VERSION 5.8 ;
BUSBITCHARS "[]" ;
DIVIDERCHAR "/" ;
UNITS
    DATABASE MICRONS 1000 ;
END UNITS

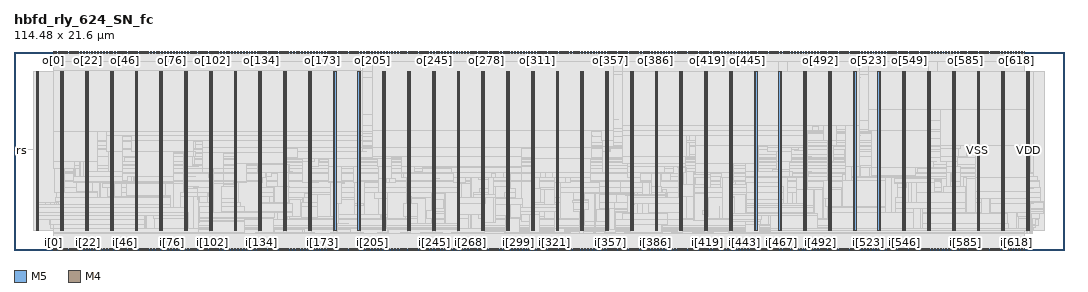
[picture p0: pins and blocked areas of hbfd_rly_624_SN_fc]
MACRO hbfd_rly_624_SN_fc
  FOREIGN hbfd_rly_624_SN_fc 0 0 ;
  CLASS BLOCK ;
  SIZE 114.48 BY 21.6 ;
  PIN clk_in
    DIRECTION INPUT ;
    USE SIGNAL ;
    PORT
      LAYER M5 ;
        RECT  57.216 0 57.24 0.192 ;
    END
  END clk_in
  PIN clk_out
    DIRECTION OUTPUT ;
    USE SIGNAL ;
    PORT
      LAYER M5 ;
        RECT  57.216 21.408 57.24 21.6 ;
    END
  END clk_out
  PIN i[0]
    DIRECTION INPUT ;
    USE SIGNAL ;
    PORT
      LAYER M5 ;
        RECT  4.32 0 4.344 0.192 ;
    END
  END i[0]
  PIN i[100]
    DIRECTION INPUT ;
    USE SIGNAL ;
    PORT
      LAYER M5 ;
        RECT  21.264 0 21.288 0.192 ;
    END
  END i[100]
  PIN i[101]
    DIRECTION INPUT ;
    USE SIGNAL ;
    PORT
      LAYER M5 ;
        RECT  21.456 0 21.48 0.192 ;
    END
  END i[101]
  PIN i[102]
    DIRECTION INPUT ;
    USE SIGNAL ;
    PORT
      LAYER M5 ;
        RECT  21.6 0 21.624 0.192 ;
    END
  END i[102]
  PIN i[103]
    DIRECTION INPUT ;
    USE SIGNAL ;
    PORT
      LAYER M5 ;
        RECT  21.792 0 21.816 0.192 ;
    END
  END i[103]
  PIN i[104]
    DIRECTION INPUT ;
    USE SIGNAL ;
    PORT
      LAYER M5 ;
        RECT  21.936 0 21.96 0.192 ;
    END
  END i[104]
  PIN i[105]
    DIRECTION INPUT ;
    USE SIGNAL ;
    PORT
      LAYER M5 ;
        RECT  22.128 0 22.152 0.192 ;
    END
  END i[105]
  PIN i[106]
    DIRECTION INPUT ;
    USE SIGNAL ;
    PORT
      LAYER M5 ;
        RECT  22.272 0 22.296 0.192 ;
    END
  END i[106]
  PIN i[107]
    DIRECTION INPUT ;
    USE SIGNAL ;
    PORT
      LAYER M5 ;
        RECT  22.464 0 22.488 0.192 ;
    END
  END i[107]
  PIN i[108]
    DIRECTION INPUT ;
    USE SIGNAL ;
    PORT
      LAYER M5 ;
        RECT  22.608 0 22.632 0.192 ;
    END
  END i[108]
  PIN i[109]
    DIRECTION INPUT ;
    USE SIGNAL ;
    PORT
      LAYER M5 ;
        RECT  22.8 0 22.824 0.192 ;
    END
  END i[109]
  PIN i[10]
    DIRECTION INPUT ;
    USE SIGNAL ;
    PORT
      LAYER M5 ;
        RECT  6 0 6.024 0.192 ;
    END
  END i[10]
  PIN i[110]
    DIRECTION INPUT ;
    USE SIGNAL ;
    PORT
      LAYER M5 ;
        RECT  22.944 0 22.968 0.192 ;
    END
  END i[110]
  PIN i[111]
    DIRECTION INPUT ;
    USE SIGNAL ;
    PORT
      LAYER M5 ;
        RECT  23.136 0 23.16 0.192 ;
    END
  END i[111]
  PIN i[112]
    DIRECTION INPUT ;
    USE SIGNAL ;
    PORT
      LAYER M5 ;
        RECT  23.328 0 23.352 0.192 ;
    END
  END i[112]
  PIN i[113]
    DIRECTION INPUT ;
    USE SIGNAL ;
    PORT
      LAYER M5 ;
        RECT  23.472 0 23.496 0.192 ;
    END
  END i[113]
  PIN i[114]
    DIRECTION INPUT ;
    USE SIGNAL ;
    PORT
      LAYER M5 ;
        RECT  23.664 0 23.688 0.192 ;
    END
  END i[114]
  PIN i[115]
    DIRECTION INPUT ;
    USE SIGNAL ;
    PORT
      LAYER M5 ;
        RECT  23.808 0 23.832 0.192 ;
    END
  END i[115]
  PIN i[116]
    DIRECTION INPUT ;
    USE SIGNAL ;
    PORT
      LAYER M5 ;
        RECT  24 0 24.024 0.192 ;
    END
  END i[116]
  PIN i[117]
    DIRECTION INPUT ;
    USE SIGNAL ;
    PORT
      LAYER M5 ;
        RECT  24.144 0 24.168 0.192 ;
    END
  END i[117]
  PIN i[118]
    DIRECTION INPUT ;
    USE SIGNAL ;
    PORT
      LAYER M5 ;
        RECT  24.336 0 24.36 0.192 ;
    END
  END i[118]
  PIN i[119]
    DIRECTION INPUT ;
    USE SIGNAL ;
    PORT
      LAYER M5 ;
        RECT  24.48 0 24.504 0.192 ;
    END
  END i[119]
  PIN i[11]
    DIRECTION INPUT ;
    USE SIGNAL ;
    PORT
      LAYER M5 ;
        RECT  6.192 0 6.216 0.192 ;
    END
  END i[11]
  PIN i[120]
    DIRECTION INPUT ;
    USE SIGNAL ;
    PORT
      LAYER M5 ;
        RECT  24.672 0 24.696 0.192 ;
    END
  END i[120]
  PIN i[121]
    DIRECTION INPUT ;
    USE SIGNAL ;
    PORT
      LAYER M5 ;
        RECT  24.816 0 24.84 0.192 ;
    END
  END i[121]
  PIN i[122]
    DIRECTION INPUT ;
    USE SIGNAL ;
    PORT
      LAYER M5 ;
        RECT  25.008 0 25.032 0.192 ;
    END
  END i[122]
  PIN i[123]
    DIRECTION INPUT ;
    USE SIGNAL ;
    PORT
      LAYER M5 ;
        RECT  25.152 0 25.176 0.192 ;
    END
  END i[123]
  PIN i[124]
    DIRECTION INPUT ;
    USE SIGNAL ;
    PORT
      LAYER M5 ;
        RECT  25.344 0 25.368 0.192 ;
    END
  END i[124]
  PIN i[125]
    DIRECTION INPUT ;
    USE SIGNAL ;
    PORT
      LAYER M5 ;
        RECT  25.488 0 25.512 0.192 ;
    END
  END i[125]
  PIN i[126]
    DIRECTION INPUT ;
    USE SIGNAL ;
    PORT
      LAYER M5 ;
        RECT  25.68 0 25.704 0.192 ;
    END
  END i[126]
  PIN i[127]
    DIRECTION INPUT ;
    USE SIGNAL ;
    PORT
      LAYER M5 ;
        RECT  25.872 0 25.896 0.192 ;
    END
  END i[127]
  PIN i[128]
    DIRECTION INPUT ;
    USE SIGNAL ;
    PORT
      LAYER M5 ;
        RECT  26.016 0 26.04 0.192 ;
    END
  END i[128]
  PIN i[129]
    DIRECTION INPUT ;
    USE SIGNAL ;
    PORT
      LAYER M5 ;
        RECT  26.208 0 26.232 0.192 ;
    END
  END i[129]
  PIN i[12]
    DIRECTION INPUT ;
    USE SIGNAL ;
    PORT
      LAYER M5 ;
        RECT  6.336 0 6.36 0.192 ;
    END
  END i[12]
  PIN i[130]
    DIRECTION INPUT ;
    USE SIGNAL ;
    PORT
      LAYER M5 ;
        RECT  26.352 0 26.376 0.192 ;
    END
  END i[130]
  PIN i[131]
    DIRECTION INPUT ;
    USE SIGNAL ;
    PORT
      LAYER M5 ;
        RECT  26.544 0 26.568 0.192 ;
    END
  END i[131]
  PIN i[132]
    DIRECTION INPUT ;
    USE SIGNAL ;
    PORT
      LAYER M5 ;
        RECT  26.688 0 26.712 0.192 ;
    END
  END i[132]
  PIN i[133]
    DIRECTION INPUT ;
    USE SIGNAL ;
    PORT
      LAYER M5 ;
        RECT  26.88 0 26.904 0.192 ;
    END
  END i[133]
  PIN i[134]
    DIRECTION INPUT ;
    USE SIGNAL ;
    PORT
      LAYER M5 ;
        RECT  27.024 0 27.048 0.192 ;
    END
  END i[134]
  PIN i[135]
    DIRECTION INPUT ;
    USE SIGNAL ;
    PORT
      LAYER M5 ;
        RECT  27.216 0 27.24 0.192 ;
    END
  END i[135]
  PIN i[136]
    DIRECTION INPUT ;
    USE SIGNAL ;
    PORT
      LAYER M5 ;
        RECT  27.36 0 27.384 0.192 ;
    END
  END i[136]
  PIN i[137]
    DIRECTION INPUT ;
    USE SIGNAL ;
    PORT
      LAYER M5 ;
        RECT  27.552 0 27.576 0.192 ;
    END
  END i[137]
  PIN i[138]
    DIRECTION INPUT ;
    USE SIGNAL ;
    PORT
      LAYER M5 ;
        RECT  27.696 0 27.72 0.192 ;
    END
  END i[138]
  PIN i[139]
    DIRECTION INPUT ;
    USE SIGNAL ;
    PORT
      LAYER M5 ;
        RECT  27.888 0 27.912 0.192 ;
    END
  END i[139]
  PIN i[13]
    DIRECTION INPUT ;
    USE SIGNAL ;
    PORT
      LAYER M5 ;
        RECT  6.528 0 6.552 0.192 ;
    END
  END i[13]
  PIN i[140]
    DIRECTION INPUT ;
    USE SIGNAL ;
    PORT
      LAYER M5 ;
        RECT  28.032 0 28.056 0.192 ;
    END
  END i[140]
  PIN i[141]
    DIRECTION INPUT ;
    USE SIGNAL ;
    PORT
      LAYER M5 ;
        RECT  28.224 0 28.248 0.192 ;
    END
  END i[141]
  PIN i[142]
    DIRECTION INPUT ;
    USE SIGNAL ;
    PORT
      LAYER M5 ;
        RECT  28.416 0 28.44 0.192 ;
    END
  END i[142]
  PIN i[143]
    DIRECTION INPUT ;
    USE SIGNAL ;
    PORT
      LAYER M5 ;
        RECT  28.56 0 28.584 0.192 ;
    END
  END i[143]
  PIN i[144]
    DIRECTION INPUT ;
    USE SIGNAL ;
    PORT
      LAYER M5 ;
        RECT  28.752 0 28.776 0.192 ;
    END
  END i[144]
  PIN i[145]
    DIRECTION INPUT ;
    USE SIGNAL ;
    PORT
      LAYER M5 ;
        RECT  28.896 0 28.92 0.192 ;
    END
  END i[145]
  PIN i[146]
    DIRECTION INPUT ;
    USE SIGNAL ;
    PORT
      LAYER M5 ;
        RECT  29.088 0 29.112 0.192 ;
    END
  END i[146]
  PIN i[147]
    DIRECTION INPUT ;
    USE SIGNAL ;
    PORT
      LAYER M5 ;
        RECT  29.232 0 29.256 0.192 ;
    END
  END i[147]
  PIN i[148]
    DIRECTION INPUT ;
    USE SIGNAL ;
    PORT
      LAYER M5 ;
        RECT  29.424 0 29.448 0.192 ;
    END
  END i[148]
  PIN i[149]
    DIRECTION INPUT ;
    USE SIGNAL ;
    PORT
      LAYER M5 ;
        RECT  29.568 0 29.592 0.192 ;
    END
  END i[149]
  PIN i[14]
    DIRECTION INPUT ;
    USE SIGNAL ;
    PORT
      LAYER M5 ;
        RECT  6.672 0 6.696 0.192 ;
    END
  END i[14]
  PIN i[150]
    DIRECTION INPUT ;
    USE SIGNAL ;
    PORT
      LAYER M5 ;
        RECT  29.76 0 29.784 0.192 ;
    END
  END i[150]
  PIN i[151]
    DIRECTION INPUT ;
    USE SIGNAL ;
    PORT
      LAYER M5 ;
        RECT  29.904 0 29.928 0.192 ;
    END
  END i[151]
  PIN i[152]
    DIRECTION INPUT ;
    USE SIGNAL ;
    PORT
      LAYER M5 ;
        RECT  30.096 0 30.12 0.192 ;
    END
  END i[152]
  PIN i[153]
    DIRECTION INPUT ;
    USE SIGNAL ;
    PORT
      LAYER M5 ;
        RECT  30.24 0 30.264 0.192 ;
    END
  END i[153]
  PIN i[154]
    DIRECTION INPUT ;
    USE SIGNAL ;
    PORT
      LAYER M5 ;
        RECT  30.432 0 30.456 0.192 ;
    END
  END i[154]
  PIN i[155]
    DIRECTION INPUT ;
    USE SIGNAL ;
    PORT
      LAYER M5 ;
        RECT  30.576 0 30.6 0.192 ;
    END
  END i[155]
  PIN i[156]
    DIRECTION INPUT ;
    USE SIGNAL ;
    PORT
      LAYER M5 ;
        RECT  30.768 0 30.792 0.192 ;
    END
  END i[156]
  PIN i[157]
    DIRECTION INPUT ;
    USE SIGNAL ;
    PORT
      LAYER M5 ;
        RECT  30.96 0 30.984 0.192 ;
    END
  END i[157]
  PIN i[158]
    DIRECTION INPUT ;
    USE SIGNAL ;
    PORT
      LAYER M5 ;
        RECT  31.104 0 31.128 0.192 ;
    END
  END i[158]
  PIN i[159]
    DIRECTION INPUT ;
    USE SIGNAL ;
    PORT
      LAYER M5 ;
        RECT  31.296 0 31.32 0.192 ;
    END
  END i[159]
  PIN i[15]
    DIRECTION INPUT ;
    USE SIGNAL ;
    PORT
      LAYER M5 ;
        RECT  6.864 0 6.888 0.192 ;
    END
  END i[15]
  PIN i[160]
    DIRECTION INPUT ;
    USE SIGNAL ;
    PORT
      LAYER M5 ;
        RECT  31.44 0 31.464 0.192 ;
    END
  END i[160]
  PIN i[161]
    DIRECTION INPUT ;
    USE SIGNAL ;
    PORT
      LAYER M5 ;
        RECT  31.632 0 31.656 0.192 ;
    END
  END i[161]
  PIN i[162]
    DIRECTION INPUT ;
    USE SIGNAL ;
    PORT
      LAYER M5 ;
        RECT  31.776 0 31.8 0.192 ;
    END
  END i[162]
  PIN i[163]
    DIRECTION INPUT ;
    USE SIGNAL ;
    PORT
      LAYER M5 ;
        RECT  31.968 0 31.992 0.192 ;
    END
  END i[163]
  PIN i[164]
    DIRECTION INPUT ;
    USE SIGNAL ;
    PORT
      LAYER M5 ;
        RECT  32.112 0 32.136 0.192 ;
    END
  END i[164]
  PIN i[165]
    DIRECTION INPUT ;
    USE SIGNAL ;
    PORT
      LAYER M5 ;
        RECT  32.304 0 32.328 0.192 ;
    END
  END i[165]
  PIN i[166]
    DIRECTION INPUT ;
    USE SIGNAL ;
    PORT
      LAYER M5 ;
        RECT  32.448 0 32.472 0.192 ;
    END
  END i[166]
  PIN i[167]
    DIRECTION INPUT ;
    USE SIGNAL ;
    PORT
      LAYER M5 ;
        RECT  32.64 0 32.664 0.192 ;
    END
  END i[167]
  PIN i[168]
    DIRECTION INPUT ;
    USE SIGNAL ;
    PORT
      LAYER M5 ;
        RECT  32.784 0 32.808 0.192 ;
    END
  END i[168]
  PIN i[169]
    DIRECTION INPUT ;
    USE SIGNAL ;
    PORT
      LAYER M5 ;
        RECT  32.976 0 33 0.192 ;
    END
  END i[169]
  PIN i[16]
    DIRECTION INPUT ;
    USE SIGNAL ;
    PORT
      LAYER M5 ;
        RECT  7.008 0 7.032 0.192 ;
    END
  END i[16]
  PIN i[170]
    DIRECTION INPUT ;
    USE SIGNAL ;
    PORT
      LAYER M5 ;
        RECT  33.12 0 33.144 0.192 ;
    END
  END i[170]
  PIN i[171]
    DIRECTION INPUT ;
    USE SIGNAL ;
    PORT
      LAYER M5 ;
        RECT  33.312 0 33.336 0.192 ;
    END
  END i[171]
  PIN i[172]
    DIRECTION INPUT ;
    USE SIGNAL ;
    PORT
      LAYER M5 ;
        RECT  33.504 0 33.528 0.192 ;
    END
  END i[172]
  PIN i[173]
    DIRECTION INPUT ;
    USE SIGNAL ;
    PORT
      LAYER M5 ;
        RECT  33.648 0 33.672 0.192 ;
    END
  END i[173]
  PIN i[174]
    DIRECTION INPUT ;
    USE SIGNAL ;
    PORT
      LAYER M5 ;
        RECT  33.84 0 33.864 0.192 ;
    END
  END i[174]
  PIN i[175]
    DIRECTION INPUT ;
    USE SIGNAL ;
    PORT
      LAYER M5 ;
        RECT  33.984 0 34.008 0.192 ;
    END
  END i[175]
  PIN i[176]
    DIRECTION INPUT ;
    USE SIGNAL ;
    PORT
      LAYER M5 ;
        RECT  34.176 0 34.2 0.192 ;
    END
  END i[176]
  PIN i[177]
    DIRECTION INPUT ;
    USE SIGNAL ;
    PORT
      LAYER M5 ;
        RECT  34.32 0 34.344 0.192 ;
    END
  END i[177]
  PIN i[178]
    DIRECTION INPUT ;
    USE SIGNAL ;
    PORT
      LAYER M5 ;
        RECT  34.512 0 34.536 0.192 ;
    END
  END i[178]
  PIN i[179]
    DIRECTION INPUT ;
    USE SIGNAL ;
    PORT
      LAYER M5 ;
        RECT  34.656 0 34.68 0.192 ;
    END
  END i[179]
  PIN i[17]
    DIRECTION INPUT ;
    USE SIGNAL ;
    PORT
      LAYER M5 ;
        RECT  7.2 0 7.224 0.192 ;
    END
  END i[17]
  PIN i[180]
    DIRECTION INPUT ;
    USE SIGNAL ;
    PORT
      LAYER M5 ;
        RECT  34.848 0 34.872 0.192 ;
    END
  END i[180]
  PIN i[181]
    DIRECTION INPUT ;
    USE SIGNAL ;
    PORT
      LAYER M5 ;
        RECT  34.992 0 35.016 0.192 ;
    END
  END i[181]
  PIN i[182]
    DIRECTION INPUT ;
    USE SIGNAL ;
    PORT
      LAYER M5 ;
        RECT  35.184 0 35.208 0.192 ;
    END
  END i[182]
  PIN i[183]
    DIRECTION INPUT ;
    USE SIGNAL ;
    PORT
      LAYER M5 ;
        RECT  35.328 0 35.352 0.192 ;
    END
  END i[183]
  PIN i[184]
    DIRECTION INPUT ;
    USE SIGNAL ;
    PORT
      LAYER M5 ;
        RECT  35.52 0 35.544 0.192 ;
    END
  END i[184]
  PIN i[185]
    DIRECTION INPUT ;
    USE SIGNAL ;
    PORT
      LAYER M5 ;
        RECT  35.664 0 35.688 0.192 ;
    END
  END i[185]
  PIN i[186]
    DIRECTION INPUT ;
    USE SIGNAL ;
    PORT
      LAYER M5 ;
        RECT  35.856 0 35.88 0.192 ;
    END
  END i[186]
  PIN i[187]
    DIRECTION INPUT ;
    USE SIGNAL ;
    PORT
      LAYER M5 ;
        RECT  36.048 0 36.072 0.192 ;
    END
  END i[187]
  PIN i[188]
    DIRECTION INPUT ;
    USE SIGNAL ;
    PORT
      LAYER M5 ;
        RECT  36.192 0 36.216 0.192 ;
    END
  END i[188]
  PIN i[189]
    DIRECTION INPUT ;
    USE SIGNAL ;
    PORT
      LAYER M5 ;
        RECT  36.384 0 36.408 0.192 ;
    END
  END i[189]
  PIN i[18]
    DIRECTION INPUT ;
    USE SIGNAL ;
    PORT
      LAYER M5 ;
        RECT  7.344 0 7.368 0.192 ;
    END
  END i[18]
  PIN i[190]
    DIRECTION INPUT ;
    USE SIGNAL ;
    PORT
      LAYER M5 ;
        RECT  36.528 0 36.552 0.192 ;
    END
  END i[190]
  PIN i[191]
    DIRECTION INPUT ;
    USE SIGNAL ;
    PORT
      LAYER M5 ;
        RECT  36.72 0 36.744 0.192 ;
    END
  END i[191]
  PIN i[192]
    DIRECTION INPUT ;
    USE SIGNAL ;
    PORT
      LAYER M5 ;
        RECT  36.864 0 36.888 0.192 ;
    END
  END i[192]
  PIN i[193]
    DIRECTION INPUT ;
    USE SIGNAL ;
    PORT
      LAYER M5 ;
        RECT  37.056 0 37.08 0.192 ;
    END
  END i[193]
  PIN i[194]
    DIRECTION INPUT ;
    USE SIGNAL ;
    PORT
      LAYER M5 ;
        RECT  37.2 0 37.224 0.192 ;
    END
  END i[194]
  PIN i[195]
    DIRECTION INPUT ;
    USE SIGNAL ;
    PORT
      LAYER M5 ;
        RECT  37.392 0 37.416 0.192 ;
    END
  END i[195]
  PIN i[196]
    DIRECTION INPUT ;
    USE SIGNAL ;
    PORT
      LAYER M5 ;
        RECT  37.536 0 37.56 0.192 ;
    END
  END i[196]
  PIN i[197]
    DIRECTION INPUT ;
    USE SIGNAL ;
    PORT
      LAYER M5 ;
        RECT  37.728 0 37.752 0.192 ;
    END
  END i[197]
  PIN i[198]
    DIRECTION INPUT ;
    USE SIGNAL ;
    PORT
      LAYER M5 ;
        RECT  37.872 0 37.896 0.192 ;
    END
  END i[198]
  PIN i[199]
    DIRECTION INPUT ;
    USE SIGNAL ;
    PORT
      LAYER M5 ;
        RECT  38.064 0 38.088 0.192 ;
    END
  END i[199]
  PIN i[19]
    DIRECTION INPUT ;
    USE SIGNAL ;
    PORT
      LAYER M5 ;
        RECT  7.536 0 7.56 0.192 ;
    END
  END i[19]
  PIN i[1]
    DIRECTION INPUT ;
    USE SIGNAL ;
    PORT
      LAYER M5 ;
        RECT  4.464 0 4.488 0.192 ;
    END
  END i[1]
  PIN i[200]
    DIRECTION INPUT ;
    USE SIGNAL ;
    PORT
      LAYER M5 ;
        RECT  38.208 0 38.232 0.192 ;
    END
  END i[200]
  PIN i[201]
    DIRECTION INPUT ;
    USE SIGNAL ;
    PORT
      LAYER M5 ;
        RECT  38.4 0 38.424 0.192 ;
    END
  END i[201]
  PIN i[202]
    DIRECTION INPUT ;
    USE SIGNAL ;
    PORT
      LAYER M5 ;
        RECT  38.592 0 38.616 0.192 ;
    END
  END i[202]
  PIN i[203]
    DIRECTION INPUT ;
    USE SIGNAL ;
    PORT
      LAYER M5 ;
        RECT  38.736 0 38.76 0.192 ;
    END
  END i[203]
  PIN i[204]
    DIRECTION INPUT ;
    USE SIGNAL ;
    PORT
      LAYER M5 ;
        RECT  38.928 0 38.952 0.192 ;
    END
  END i[204]
  PIN i[205]
    DIRECTION INPUT ;
    USE SIGNAL ;
    PORT
      LAYER M5 ;
        RECT  39.072 0 39.096 0.192 ;
    END
  END i[205]
  PIN i[206]
    DIRECTION INPUT ;
    USE SIGNAL ;
    PORT
      LAYER M5 ;
        RECT  39.264 0 39.288 0.192 ;
    END
  END i[206]
  PIN i[207]
    DIRECTION INPUT ;
    USE SIGNAL ;
    PORT
      LAYER M5 ;
        RECT  39.408 0 39.432 0.192 ;
    END
  END i[207]
  PIN i[208]
    DIRECTION INPUT ;
    USE SIGNAL ;
    PORT
      LAYER M5 ;
        RECT  39.6 0 39.624 0.192 ;
    END
  END i[208]
  PIN i[209]
    DIRECTION INPUT ;
    USE SIGNAL ;
    PORT
      LAYER M5 ;
        RECT  39.744 0 39.768 0.192 ;
    END
  END i[209]
  PIN i[20]
    DIRECTION INPUT ;
    USE SIGNAL ;
    PORT
      LAYER M5 ;
        RECT  7.68 0 7.704 0.192 ;
    END
  END i[20]
  PIN i[210]
    DIRECTION INPUT ;
    USE SIGNAL ;
    PORT
      LAYER M5 ;
        RECT  39.936 0 39.96 0.192 ;
    END
  END i[210]
  PIN i[211]
    DIRECTION INPUT ;
    USE SIGNAL ;
    PORT
      LAYER M5 ;
        RECT  40.08 0 40.104 0.192 ;
    END
  END i[211]
  PIN i[212]
    DIRECTION INPUT ;
    USE SIGNAL ;
    PORT
      LAYER M5 ;
        RECT  40.272 0 40.296 0.192 ;
    END
  END i[212]
  PIN i[213]
    DIRECTION INPUT ;
    USE SIGNAL ;
    PORT
      LAYER M5 ;
        RECT  40.416 0 40.44 0.192 ;
    END
  END i[213]
  PIN i[214]
    DIRECTION INPUT ;
    USE SIGNAL ;
    PORT
      LAYER M5 ;
        RECT  40.608 0 40.632 0.192 ;
    END
  END i[214]
  PIN i[215]
    DIRECTION INPUT ;
    USE SIGNAL ;
    PORT
      LAYER M5 ;
        RECT  40.752 0 40.776 0.192 ;
    END
  END i[215]
  PIN i[216]
    DIRECTION INPUT ;
    USE SIGNAL ;
    PORT
      LAYER M5 ;
        RECT  40.944 0 40.968 0.192 ;
    END
  END i[216]
  PIN i[217]
    DIRECTION INPUT ;
    USE SIGNAL ;
    PORT
      LAYER M5 ;
        RECT  41.136 0 41.16 0.192 ;
    END
  END i[217]
  PIN i[218]
    DIRECTION INPUT ;
    USE SIGNAL ;
    PORT
      LAYER M5 ;
        RECT  41.28 0 41.304 0.192 ;
    END
  END i[218]
  PIN i[219]
    DIRECTION INPUT ;
    USE SIGNAL ;
    PORT
      LAYER M5 ;
        RECT  41.472 0 41.496 0.192 ;
    END
  END i[219]
  PIN i[21]
    DIRECTION INPUT ;
    USE SIGNAL ;
    PORT
      LAYER M5 ;
        RECT  7.872 0 7.896 0.192 ;
    END
  END i[21]
  PIN i[220]
    DIRECTION INPUT ;
    USE SIGNAL ;
    PORT
      LAYER M5 ;
        RECT  41.616 0 41.64 0.192 ;
    END
  END i[220]
  PIN i[221]
    DIRECTION INPUT ;
    USE SIGNAL ;
    PORT
      LAYER M5 ;
        RECT  41.808 0 41.832 0.192 ;
    END
  END i[221]
  PIN i[222]
    DIRECTION INPUT ;
    USE SIGNAL ;
    PORT
      LAYER M5 ;
        RECT  41.952 0 41.976 0.192 ;
    END
  END i[222]
  PIN i[223]
    DIRECTION INPUT ;
    USE SIGNAL ;
    PORT
      LAYER M5 ;
        RECT  42.144 0 42.168 0.192 ;
    END
  END i[223]
  PIN i[224]
    DIRECTION INPUT ;
    USE SIGNAL ;
    PORT
      LAYER M5 ;
        RECT  42.288 0 42.312 0.192 ;
    END
  END i[224]
  PIN i[225]
    DIRECTION INPUT ;
    USE SIGNAL ;
    PORT
      LAYER M5 ;
        RECT  42.48 0 42.504 0.192 ;
    END
  END i[225]
  PIN i[226]
    DIRECTION INPUT ;
    USE SIGNAL ;
    PORT
      LAYER M5 ;
        RECT  42.624 0 42.648 0.192 ;
    END
  END i[226]
  PIN i[227]
    DIRECTION INPUT ;
    USE SIGNAL ;
    PORT
      LAYER M5 ;
        RECT  42.816 0 42.84 0.192 ;
    END
  END i[227]
  PIN i[228]
    DIRECTION INPUT ;
    USE SIGNAL ;
    PORT
      LAYER M5 ;
        RECT  42.96 0 42.984 0.192 ;
    END
  END i[228]
  PIN i[229]
    DIRECTION INPUT ;
    USE SIGNAL ;
    PORT
      LAYER M5 ;
        RECT  43.152 0 43.176 0.192 ;
    END
  END i[229]
  PIN i[22]
    DIRECTION INPUT ;
    USE SIGNAL ;
    PORT
      LAYER M5 ;
        RECT  8.016 0 8.04 0.192 ;
    END
  END i[22]
  PIN i[230]
    DIRECTION INPUT ;
    USE SIGNAL ;
    PORT
      LAYER M5 ;
        RECT  43.296 0 43.32 0.192 ;
    END
  END i[230]
  PIN i[231]
    DIRECTION INPUT ;
    USE SIGNAL ;
    PORT
      LAYER M5 ;
        RECT  43.488 0 43.512 0.192 ;
    END
  END i[231]
  PIN i[232]
    DIRECTION INPUT ;
    USE SIGNAL ;
    PORT
      LAYER M5 ;
        RECT  43.68 0 43.704 0.192 ;
    END
  END i[232]
  PIN i[233]
    DIRECTION INPUT ;
    USE SIGNAL ;
    PORT
      LAYER M5 ;
        RECT  43.824 0 43.848 0.192 ;
    END
  END i[233]
  PIN i[234]
    DIRECTION INPUT ;
    USE SIGNAL ;
    PORT
      LAYER M5 ;
        RECT  44.016 0 44.04 0.192 ;
    END
  END i[234]
  PIN i[235]
    DIRECTION INPUT ;
    USE SIGNAL ;
    PORT
      LAYER M5 ;
        RECT  44.16 0 44.184 0.192 ;
    END
  END i[235]
  PIN i[236]
    DIRECTION INPUT ;
    USE SIGNAL ;
    PORT
      LAYER M5 ;
        RECT  44.352 0 44.376 0.192 ;
    END
  END i[236]
  PIN i[237]
    DIRECTION INPUT ;
    USE SIGNAL ;
    PORT
      LAYER M5 ;
        RECT  44.496 0 44.52 0.192 ;
    END
  END i[237]
  PIN i[238]
    DIRECTION INPUT ;
    USE SIGNAL ;
    PORT
      LAYER M5 ;
        RECT  44.688 0 44.712 0.192 ;
    END
  END i[238]
  PIN i[239]
    DIRECTION INPUT ;
    USE SIGNAL ;
    PORT
      LAYER M5 ;
        RECT  44.832 0 44.856 0.192 ;
    END
  END i[239]
  PIN i[23]
    DIRECTION INPUT ;
    USE SIGNAL ;
    PORT
      LAYER M5 ;
        RECT  8.208 0 8.232 0.192 ;
    END
  END i[23]
  PIN i[240]
    DIRECTION INPUT ;
    USE SIGNAL ;
    PORT
      LAYER M5 ;
        RECT  45.024 0 45.048 0.192 ;
    END
  END i[240]
  PIN i[241]
    DIRECTION INPUT ;
    USE SIGNAL ;
    PORT
      LAYER M5 ;
        RECT  45.168 0 45.192 0.192 ;
    END
  END i[241]
  PIN i[242]
    DIRECTION INPUT ;
    USE SIGNAL ;
    PORT
      LAYER M5 ;
        RECT  45.36 0 45.384 0.192 ;
    END
  END i[242]
  PIN i[243]
    DIRECTION INPUT ;
    USE SIGNAL ;
    PORT
      LAYER M5 ;
        RECT  45.504 0 45.528 0.192 ;
    END
  END i[243]
  PIN i[244]
    DIRECTION INPUT ;
    USE SIGNAL ;
    PORT
      LAYER M5 ;
        RECT  45.696 0 45.72 0.192 ;
    END
  END i[244]
  PIN i[245]
    DIRECTION INPUT ;
    USE SIGNAL ;
    PORT
      LAYER M5 ;
        RECT  45.84 0 45.864 0.192 ;
    END
  END i[245]
  PIN i[246]
    DIRECTION INPUT ;
    USE SIGNAL ;
    PORT
      LAYER M5 ;
        RECT  46.032 0 46.056 0.192 ;
    END
  END i[246]
  PIN i[247]
    DIRECTION INPUT ;
    USE SIGNAL ;
    PORT
      LAYER M5 ;
        RECT  46.224 0 46.248 0.192 ;
    END
  END i[247]
  PIN i[248]
    DIRECTION INPUT ;
    USE SIGNAL ;
    PORT
      LAYER M5 ;
        RECT  46.368 0 46.392 0.192 ;
    END
  END i[248]
  PIN i[249]
    DIRECTION INPUT ;
    USE SIGNAL ;
    PORT
      LAYER M5 ;
        RECT  46.56 0 46.584 0.192 ;
    END
  END i[249]
  PIN i[24]
    DIRECTION INPUT ;
    USE SIGNAL ;
    PORT
      LAYER M5 ;
        RECT  8.4 0 8.424 0.192 ;
    END
  END i[24]
  PIN i[250]
    DIRECTION INPUT ;
    USE SIGNAL ;
    PORT
      LAYER M5 ;
        RECT  46.704 0 46.728 0.192 ;
    END
  END i[250]
  PIN i[251]
    DIRECTION INPUT ;
    USE SIGNAL ;
    PORT
      LAYER M5 ;
        RECT  46.896 0 46.92 0.192 ;
    END
  END i[251]
  PIN i[252]
    DIRECTION INPUT ;
    USE SIGNAL ;
    PORT
      LAYER M5 ;
        RECT  47.04 0 47.064 0.192 ;
    END
  END i[252]
  PIN i[253]
    DIRECTION INPUT ;
    USE SIGNAL ;
    PORT
      LAYER M5 ;
        RECT  47.232 0 47.256 0.192 ;
    END
  END i[253]
  PIN i[254]
    DIRECTION INPUT ;
    USE SIGNAL ;
    PORT
      LAYER M5 ;
        RECT  47.376 0 47.4 0.192 ;
    END
  END i[254]
  PIN i[255]
    DIRECTION INPUT ;
    USE SIGNAL ;
    PORT
      LAYER M5 ;
        RECT  47.568 0 47.592 0.192 ;
    END
  END i[255]
  PIN i[256]
    DIRECTION INPUT ;
    USE SIGNAL ;
    PORT
      LAYER M5 ;
        RECT  47.712 0 47.736 0.192 ;
    END
  END i[256]
  PIN i[257]
    DIRECTION INPUT ;
    USE SIGNAL ;
    PORT
      LAYER M5 ;
        RECT  47.904 0 47.928 0.192 ;
    END
  END i[257]
  PIN i[258]
    DIRECTION INPUT ;
    USE SIGNAL ;
    PORT
      LAYER M5 ;
        RECT  48.048 0 48.072 0.192 ;
    END
  END i[258]
  PIN i[259]
    DIRECTION INPUT ;
    USE SIGNAL ;
    PORT
      LAYER M5 ;
        RECT  48.24 0 48.264 0.192 ;
    END
  END i[259]
  PIN i[25]
    DIRECTION INPUT ;
    USE SIGNAL ;
    PORT
      LAYER M5 ;
        RECT  8.544 0 8.568 0.192 ;
    END
  END i[25]
  PIN i[260]
    DIRECTION INPUT ;
    USE SIGNAL ;
    PORT
      LAYER M5 ;
        RECT  48.384 0 48.408 0.192 ;
    END
  END i[260]
  PIN i[261]
    DIRECTION INPUT ;
    USE SIGNAL ;
    PORT
      LAYER M5 ;
        RECT  48.576 0 48.6 0.192 ;
    END
  END i[261]
  PIN i[262]
    DIRECTION INPUT ;
    USE SIGNAL ;
    PORT
      LAYER M5 ;
        RECT  48.768 0 48.792 0.192 ;
    END
  END i[262]
  PIN i[263]
    DIRECTION INPUT ;
    USE SIGNAL ;
    PORT
      LAYER M5 ;
        RECT  48.912 0 48.936 0.192 ;
    END
  END i[263]
  PIN i[264]
    DIRECTION INPUT ;
    USE SIGNAL ;
    PORT
      LAYER M5 ;
        RECT  49.104 0 49.128 0.192 ;
    END
  END i[264]
  PIN i[265]
    DIRECTION INPUT ;
    USE SIGNAL ;
    PORT
      LAYER M5 ;
        RECT  49.248 0 49.272 0.192 ;
    END
  END i[265]
  PIN i[266]
    DIRECTION INPUT ;
    USE SIGNAL ;
    PORT
      LAYER M5 ;
        RECT  49.44 0 49.464 0.192 ;
    END
  END i[266]
  PIN i[267]
    DIRECTION INPUT ;
    USE SIGNAL ;
    PORT
      LAYER M5 ;
        RECT  49.584 0 49.608 0.192 ;
    END
  END i[267]
  PIN i[268]
    DIRECTION INPUT ;
    USE SIGNAL ;
    PORT
      LAYER M5 ;
        RECT  49.776 0 49.8 0.192 ;
    END
  END i[268]
  PIN i[269]
    DIRECTION INPUT ;
    USE SIGNAL ;
    PORT
      LAYER M5 ;
        RECT  49.92 0 49.944 0.192 ;
    END
  END i[269]
  PIN i[26]
    DIRECTION INPUT ;
    USE SIGNAL ;
    PORT
      LAYER M5 ;
        RECT  8.736 0 8.76 0.192 ;
    END
  END i[26]
  PIN i[270]
    DIRECTION INPUT ;
    USE SIGNAL ;
    PORT
      LAYER M5 ;
        RECT  50.112 0 50.136 0.192 ;
    END
  END i[270]
  PIN i[271]
    DIRECTION INPUT ;
    USE SIGNAL ;
    PORT
      LAYER M5 ;
        RECT  50.256 0 50.28 0.192 ;
    END
  END i[271]
  PIN i[272]
    DIRECTION INPUT ;
    USE SIGNAL ;
    PORT
      LAYER M5 ;
        RECT  50.448 0 50.472 0.192 ;
    END
  END i[272]
  PIN i[273]
    DIRECTION INPUT ;
    USE SIGNAL ;
    PORT
      LAYER M5 ;
        RECT  50.592 0 50.616 0.192 ;
    END
  END i[273]
  PIN i[274]
    DIRECTION INPUT ;
    USE SIGNAL ;
    PORT
      LAYER M5 ;
        RECT  50.784 0 50.808 0.192 ;
    END
  END i[274]
  PIN i[275]
    DIRECTION INPUT ;
    USE SIGNAL ;
    PORT
      LAYER M5 ;
        RECT  50.976 0 51 0.192 ;
    END
  END i[275]
  PIN i[276]
    DIRECTION INPUT ;
    USE SIGNAL ;
    PORT
      LAYER M5 ;
        RECT  51.12 0 51.144 0.192 ;
    END
  END i[276]
  PIN i[277]
    DIRECTION INPUT ;
    USE SIGNAL ;
    PORT
      LAYER M5 ;
        RECT  51.312 0 51.336 0.192 ;
    END
  END i[277]
  PIN i[278]
    DIRECTION INPUT ;
    USE SIGNAL ;
    PORT
      LAYER M5 ;
        RECT  51.456 0 51.48 0.192 ;
    END
  END i[278]
  PIN i[279]
    DIRECTION INPUT ;
    USE SIGNAL ;
    PORT
      LAYER M5 ;
        RECT  51.648 0 51.672 0.192 ;
    END
  END i[279]
  PIN i[27]
    DIRECTION INPUT ;
    USE SIGNAL ;
    PORT
      LAYER M5 ;
        RECT  8.88 0 8.904 0.192 ;
    END
  END i[27]
  PIN i[280]
    DIRECTION INPUT ;
    USE SIGNAL ;
    PORT
      LAYER M5 ;
        RECT  51.792 0 51.816 0.192 ;
    END
  END i[280]
  PIN i[281]
    DIRECTION INPUT ;
    USE SIGNAL ;
    PORT
      LAYER M5 ;
        RECT  51.984 0 52.008 0.192 ;
    END
  END i[281]
  PIN i[282]
    DIRECTION INPUT ;
    USE SIGNAL ;
    PORT
      LAYER M5 ;
        RECT  52.128 0 52.152 0.192 ;
    END
  END i[282]
  PIN i[283]
    DIRECTION INPUT ;
    USE SIGNAL ;
    PORT
      LAYER M5 ;
        RECT  52.32 0 52.344 0.192 ;
    END
  END i[283]
  PIN i[284]
    DIRECTION INPUT ;
    USE SIGNAL ;
    PORT
      LAYER M5 ;
        RECT  52.464 0 52.488 0.192 ;
    END
  END i[284]
  PIN i[285]
    DIRECTION INPUT ;
    USE SIGNAL ;
    PORT
      LAYER M5 ;
        RECT  52.656 0 52.68 0.192 ;
    END
  END i[285]
  PIN i[286]
    DIRECTION INPUT ;
    USE SIGNAL ;
    PORT
      LAYER M5 ;
        RECT  52.8 0 52.824 0.192 ;
    END
  END i[286]
  PIN i[287]
    DIRECTION INPUT ;
    USE SIGNAL ;
    PORT
      LAYER M5 ;
        RECT  52.992 0 53.016 0.192 ;
    END
  END i[287]
  PIN i[288]
    DIRECTION INPUT ;
    USE SIGNAL ;
    PORT
      LAYER M5 ;
        RECT  53.136 0 53.16 0.192 ;
    END
  END i[288]
  PIN i[289]
    DIRECTION INPUT ;
    USE SIGNAL ;
    PORT
      LAYER M5 ;
        RECT  53.328 0 53.352 0.192 ;
    END
  END i[289]
  PIN i[28]
    DIRECTION INPUT ;
    USE SIGNAL ;
    PORT
      LAYER M5 ;
        RECT  9.072 0 9.096 0.192 ;
    END
  END i[28]
  PIN i[290]
    DIRECTION INPUT ;
    USE SIGNAL ;
    PORT
      LAYER M5 ;
        RECT  53.52 0 53.544 0.192 ;
    END
  END i[290]
  PIN i[291]
    DIRECTION INPUT ;
    USE SIGNAL ;
    PORT
      LAYER M5 ;
        RECT  53.664 0 53.688 0.192 ;
    END
  END i[291]
  PIN i[292]
    DIRECTION INPUT ;
    USE SIGNAL ;
    PORT
      LAYER M5 ;
        RECT  53.856 0 53.88 0.192 ;
    END
  END i[292]
  PIN i[293]
    DIRECTION INPUT ;
    USE SIGNAL ;
    PORT
      LAYER M5 ;
        RECT  54 0 54.024 0.192 ;
    END
  END i[293]
  PIN i[294]
    DIRECTION INPUT ;
    USE SIGNAL ;
    PORT
      LAYER M5 ;
        RECT  54.192 0 54.216 0.192 ;
    END
  END i[294]
  PIN i[295]
    DIRECTION INPUT ;
    USE SIGNAL ;
    PORT
      LAYER M5 ;
        RECT  54.336 0 54.36 0.192 ;
    END
  END i[295]
  PIN i[296]
    DIRECTION INPUT ;
    USE SIGNAL ;
    PORT
      LAYER M5 ;
        RECT  54.528 0 54.552 0.192 ;
    END
  END i[296]
  PIN i[297]
    DIRECTION INPUT ;
    USE SIGNAL ;
    PORT
      LAYER M5 ;
        RECT  54.672 0 54.696 0.192 ;
    END
  END i[297]
  PIN i[298]
    DIRECTION INPUT ;
    USE SIGNAL ;
    PORT
      LAYER M5 ;
        RECT  54.864 0 54.888 0.192 ;
    END
  END i[298]
  PIN i[299]
    DIRECTION INPUT ;
    USE SIGNAL ;
    PORT
      LAYER M5 ;
        RECT  55.008 0 55.032 0.192 ;
    END
  END i[299]
  PIN i[29]
    DIRECTION INPUT ;
    USE SIGNAL ;
    PORT
      LAYER M5 ;
        RECT  9.216 0 9.24 0.192 ;
    END
  END i[29]
  PIN i[2]
    DIRECTION INPUT ;
    USE SIGNAL ;
    PORT
      LAYER M5 ;
        RECT  4.656 0 4.68 0.192 ;
    END
  END i[2]
  PIN i[300]
    DIRECTION INPUT ;
    USE SIGNAL ;
    PORT
      LAYER M5 ;
        RECT  55.2 0 55.224 0.192 ;
    END
  END i[300]
  PIN i[301]
    DIRECTION INPUT ;
    USE SIGNAL ;
    PORT
      LAYER M5 ;
        RECT  55.344 0 55.368 0.192 ;
    END
  END i[301]
  PIN i[302]
    DIRECTION INPUT ;
    USE SIGNAL ;
    PORT
      LAYER M5 ;
        RECT  55.536 0 55.56 0.192 ;
    END
  END i[302]
  PIN i[303]
    DIRECTION INPUT ;
    USE SIGNAL ;
    PORT
      LAYER M5 ;
        RECT  55.68 0 55.704 0.192 ;
    END
  END i[303]
  PIN i[304]
    DIRECTION INPUT ;
    USE SIGNAL ;
    PORT
      LAYER M5 ;
        RECT  55.872 0 55.896 0.192 ;
    END
  END i[304]
  PIN i[305]
    DIRECTION INPUT ;
    USE SIGNAL ;
    PORT
      LAYER M5 ;
        RECT  56.064 0 56.088 0.192 ;
    END
  END i[305]
  PIN i[306]
    DIRECTION INPUT ;
    USE SIGNAL ;
    PORT
      LAYER M5 ;
        RECT  56.208 0 56.232 0.192 ;
    END
  END i[306]
  PIN i[307]
    DIRECTION INPUT ;
    USE SIGNAL ;
    PORT
      LAYER M5 ;
        RECT  56.4 0 56.424 0.192 ;
    END
  END i[307]
  PIN i[308]
    DIRECTION INPUT ;
    USE SIGNAL ;
    PORT
      LAYER M5 ;
        RECT  56.544 0 56.568 0.192 ;
    END
  END i[308]
  PIN i[309]
    DIRECTION INPUT ;
    USE SIGNAL ;
    PORT
      LAYER M5 ;
        RECT  56.736 0 56.76 0.192 ;
    END
  END i[309]
  PIN i[30]
    DIRECTION INPUT ;
    USE SIGNAL ;
    PORT
      LAYER M5 ;
        RECT  9.408 0 9.432 0.192 ;
    END
  END i[30]
  PIN i[310]
    DIRECTION INPUT ;
    USE SIGNAL ;
    PORT
      LAYER M5 ;
        RECT  56.88 0 56.904 0.192 ;
    END
  END i[310]
  PIN i[311]
    DIRECTION INPUT ;
    USE SIGNAL ;
    PORT
      LAYER M5 ;
        RECT  57.072 0 57.096 0.192 ;
    END
  END i[311]
  PIN i[312]
    DIRECTION INPUT ;
    USE SIGNAL ;
    PORT
      LAYER M5 ;
        RECT  57.408 0 57.432 0.192 ;
    END
  END i[312]
  PIN i[313]
    DIRECTION INPUT ;
    USE SIGNAL ;
    PORT
      LAYER M5 ;
        RECT  57.552 0 57.576 0.192 ;
    END
  END i[313]
  PIN i[314]
    DIRECTION INPUT ;
    USE SIGNAL ;
    PORT
      LAYER M5 ;
        RECT  57.744 0 57.768 0.192 ;
    END
  END i[314]
  PIN i[315]
    DIRECTION INPUT ;
    USE SIGNAL ;
    PORT
      LAYER M5 ;
        RECT  57.888 0 57.912 0.192 ;
    END
  END i[315]
  PIN i[316]
    DIRECTION INPUT ;
    USE SIGNAL ;
    PORT
      LAYER M5 ;
        RECT  58.08 0 58.104 0.192 ;
    END
  END i[316]
  PIN i[317]
    DIRECTION INPUT ;
    USE SIGNAL ;
    PORT
      LAYER M5 ;
        RECT  58.224 0 58.248 0.192 ;
    END
  END i[317]
  PIN i[318]
    DIRECTION INPUT ;
    USE SIGNAL ;
    PORT
      LAYER M5 ;
        RECT  58.416 0 58.44 0.192 ;
    END
  END i[318]
  PIN i[319]
    DIRECTION INPUT ;
    USE SIGNAL ;
    PORT
      LAYER M5 ;
        RECT  58.608 0 58.632 0.192 ;
    END
  END i[319]
  PIN i[31]
    DIRECTION INPUT ;
    USE SIGNAL ;
    PORT
      LAYER M5 ;
        RECT  9.552 0 9.576 0.192 ;
    END
  END i[31]
  PIN i[320]
    DIRECTION INPUT ;
    USE SIGNAL ;
    PORT
      LAYER M5 ;
        RECT  58.752 0 58.776 0.192 ;
    END
  END i[320]
  PIN i[321]
    DIRECTION INPUT ;
    USE SIGNAL ;
    PORT
      LAYER M5 ;
        RECT  58.944 0 58.968 0.192 ;
    END
  END i[321]
  PIN i[322]
    DIRECTION INPUT ;
    USE SIGNAL ;
    PORT
      LAYER M5 ;
        RECT  59.088 0 59.112 0.192 ;
    END
  END i[322]
  PIN i[323]
    DIRECTION INPUT ;
    USE SIGNAL ;
    PORT
      LAYER M5 ;
        RECT  59.28 0 59.304 0.192 ;
    END
  END i[323]
  PIN i[324]
    DIRECTION INPUT ;
    USE SIGNAL ;
    PORT
      LAYER M5 ;
        RECT  59.424 0 59.448 0.192 ;
    END
  END i[324]
  PIN i[325]
    DIRECTION INPUT ;
    USE SIGNAL ;
    PORT
      LAYER M5 ;
        RECT  59.616 0 59.64 0.192 ;
    END
  END i[325]
  PIN i[326]
    DIRECTION INPUT ;
    USE SIGNAL ;
    PORT
      LAYER M5 ;
        RECT  59.76 0 59.784 0.192 ;
    END
  END i[326]
  PIN i[327]
    DIRECTION INPUT ;
    USE SIGNAL ;
    PORT
      LAYER M5 ;
        RECT  59.952 0 59.976 0.192 ;
    END
  END i[327]
  PIN i[328]
    DIRECTION INPUT ;
    USE SIGNAL ;
    PORT
      LAYER M5 ;
        RECT  60.096 0 60.12 0.192 ;
    END
  END i[328]
  PIN i[329]
    DIRECTION INPUT ;
    USE SIGNAL ;
    PORT
      LAYER M5 ;
        RECT  60.288 0 60.312 0.192 ;
    END
  END i[329]
  PIN i[32]
    DIRECTION INPUT ;
    USE SIGNAL ;
    PORT
      LAYER M5 ;
        RECT  9.744 0 9.768 0.192 ;
    END
  END i[32]
  PIN i[330]
    DIRECTION INPUT ;
    USE SIGNAL ;
    PORT
      LAYER M5 ;
        RECT  60.432 0 60.456 0.192 ;
    END
  END i[330]
  PIN i[331]
    DIRECTION INPUT ;
    USE SIGNAL ;
    PORT
      LAYER M5 ;
        RECT  60.624 0 60.648 0.192 ;
    END
  END i[331]
  PIN i[332]
    DIRECTION INPUT ;
    USE SIGNAL ;
    PORT
      LAYER M5 ;
        RECT  60.768 0 60.792 0.192 ;
    END
  END i[332]
  PIN i[333]
    DIRECTION INPUT ;
    USE SIGNAL ;
    PORT
      LAYER M5 ;
        RECT  60.96 0 60.984 0.192 ;
    END
  END i[333]
  PIN i[334]
    DIRECTION INPUT ;
    USE SIGNAL ;
    PORT
      LAYER M5 ;
        RECT  61.152 0 61.176 0.192 ;
    END
  END i[334]
  PIN i[335]
    DIRECTION INPUT ;
    USE SIGNAL ;
    PORT
      LAYER M5 ;
        RECT  61.296 0 61.32 0.192 ;
    END
  END i[335]
  PIN i[336]
    DIRECTION INPUT ;
    USE SIGNAL ;
    PORT
      LAYER M5 ;
        RECT  61.488 0 61.512 0.192 ;
    END
  END i[336]
  PIN i[337]
    DIRECTION INPUT ;
    USE SIGNAL ;
    PORT
      LAYER M5 ;
        RECT  61.632 0 61.656 0.192 ;
    END
  END i[337]
  PIN i[338]
    DIRECTION INPUT ;
    USE SIGNAL ;
    PORT
      LAYER M5 ;
        RECT  61.824 0 61.848 0.192 ;
    END
  END i[338]
  PIN i[339]
    DIRECTION INPUT ;
    USE SIGNAL ;
    PORT
      LAYER M5 ;
        RECT  61.968 0 61.992 0.192 ;
    END
  END i[339]
  PIN i[33]
    DIRECTION INPUT ;
    USE SIGNAL ;
    PORT
      LAYER M5 ;
        RECT  9.888 0 9.912 0.192 ;
    END
  END i[33]
  PIN i[340]
    DIRECTION INPUT ;
    USE SIGNAL ;
    PORT
      LAYER M5 ;
        RECT  62.16 0 62.184 0.192 ;
    END
  END i[340]
  PIN i[341]
    DIRECTION INPUT ;
    USE SIGNAL ;
    PORT
      LAYER M5 ;
        RECT  62.304 0 62.328 0.192 ;
    END
  END i[341]
  PIN i[342]
    DIRECTION INPUT ;
    USE SIGNAL ;
    PORT
      LAYER M5 ;
        RECT  62.496 0 62.52 0.192 ;
    END
  END i[342]
  PIN i[343]
    DIRECTION INPUT ;
    USE SIGNAL ;
    PORT
      LAYER M5 ;
        RECT  62.64 0 62.664 0.192 ;
    END
  END i[343]
  PIN i[344]
    DIRECTION INPUT ;
    USE SIGNAL ;
    PORT
      LAYER M5 ;
        RECT  62.832 0 62.856 0.192 ;
    END
  END i[344]
  PIN i[345]
    DIRECTION INPUT ;
    USE SIGNAL ;
    PORT
      LAYER M5 ;
        RECT  62.976 0 63 0.192 ;
    END
  END i[345]
  PIN i[346]
    DIRECTION INPUT ;
    USE SIGNAL ;
    PORT
      LAYER M5 ;
        RECT  63.168 0 63.192 0.192 ;
    END
  END i[346]
  PIN i[347]
    DIRECTION INPUT ;
    USE SIGNAL ;
    PORT
      LAYER M5 ;
        RECT  63.312 0 63.336 0.192 ;
    END
  END i[347]
  PIN i[348]
    DIRECTION INPUT ;
    USE SIGNAL ;
    PORT
      LAYER M5 ;
        RECT  63.504 0 63.528 0.192 ;
    END
  END i[348]
  PIN i[349]
    DIRECTION INPUT ;
    USE SIGNAL ;
    PORT
      LAYER M5 ;
        RECT  63.696 0 63.72 0.192 ;
    END
  END i[349]
  PIN i[34]
    DIRECTION INPUT ;
    USE SIGNAL ;
    PORT
      LAYER M5 ;
        RECT  10.08 0 10.104 0.192 ;
    END
  END i[34]
  PIN i[350]
    DIRECTION INPUT ;
    USE SIGNAL ;
    PORT
      LAYER M5 ;
        RECT  63.84 0 63.864 0.192 ;
    END
  END i[350]
  PIN i[351]
    DIRECTION INPUT ;
    USE SIGNAL ;
    PORT
      LAYER M5 ;
        RECT  64.032 0 64.056 0.192 ;
    END
  END i[351]
  PIN i[352]
    DIRECTION INPUT ;
    USE SIGNAL ;
    PORT
      LAYER M5 ;
        RECT  64.176 0 64.2 0.192 ;
    END
  END i[352]
  PIN i[353]
    DIRECTION INPUT ;
    USE SIGNAL ;
    PORT
      LAYER M5 ;
        RECT  64.368 0 64.392 0.192 ;
    END
  END i[353]
  PIN i[354]
    DIRECTION INPUT ;
    USE SIGNAL ;
    PORT
      LAYER M5 ;
        RECT  64.512 0 64.536 0.192 ;
    END
  END i[354]
  PIN i[355]
    DIRECTION INPUT ;
    USE SIGNAL ;
    PORT
      LAYER M5 ;
        RECT  64.704 0 64.728 0.192 ;
    END
  END i[355]
  PIN i[356]
    DIRECTION INPUT ;
    USE SIGNAL ;
    PORT
      LAYER M5 ;
        RECT  64.848 0 64.872 0.192 ;
    END
  END i[356]
  PIN i[357]
    DIRECTION INPUT ;
    USE SIGNAL ;
    PORT
      LAYER M5 ;
        RECT  65.04 0 65.064 0.192 ;
    END
  END i[357]
  PIN i[358]
    DIRECTION INPUT ;
    USE SIGNAL ;
    PORT
      LAYER M5 ;
        RECT  65.184 0 65.208 0.192 ;
    END
  END i[358]
  PIN i[359]
    DIRECTION INPUT ;
    USE SIGNAL ;
    PORT
      LAYER M5 ;
        RECT  65.376 0 65.4 0.192 ;
    END
  END i[359]
  PIN i[35]
    DIRECTION INPUT ;
    USE SIGNAL ;
    PORT
      LAYER M5 ;
        RECT  10.224 0 10.248 0.192 ;
    END
  END i[35]
  PIN i[360]
    DIRECTION INPUT ;
    USE SIGNAL ;
    PORT
      LAYER M5 ;
        RECT  65.52 0 65.544 0.192 ;
    END
  END i[360]
  PIN i[361]
    DIRECTION INPUT ;
    USE SIGNAL ;
    PORT
      LAYER M5 ;
        RECT  65.712 0 65.736 0.192 ;
    END
  END i[361]
  PIN i[362]
    DIRECTION INPUT ;
    USE SIGNAL ;
    PORT
      LAYER M5 ;
        RECT  65.856 0 65.88 0.192 ;
    END
  END i[362]
  PIN i[363]
    DIRECTION INPUT ;
    USE SIGNAL ;
    PORT
      LAYER M5 ;
        RECT  66.048 0 66.072 0.192 ;
    END
  END i[363]
  PIN i[364]
    DIRECTION INPUT ;
    USE SIGNAL ;
    PORT
      LAYER M5 ;
        RECT  66.24 0 66.264 0.192 ;
    END
  END i[364]
  PIN i[365]
    DIRECTION INPUT ;
    USE SIGNAL ;
    PORT
      LAYER M5 ;
        RECT  66.384 0 66.408 0.192 ;
    END
  END i[365]
  PIN i[366]
    DIRECTION INPUT ;
    USE SIGNAL ;
    PORT
      LAYER M5 ;
        RECT  66.576 0 66.6 0.192 ;
    END
  END i[366]
  PIN i[367]
    DIRECTION INPUT ;
    USE SIGNAL ;
    PORT
      LAYER M5 ;
        RECT  66.72 0 66.744 0.192 ;
    END
  END i[367]
  PIN i[368]
    DIRECTION INPUT ;
    USE SIGNAL ;
    PORT
      LAYER M5 ;
        RECT  66.912 0 66.936 0.192 ;
    END
  END i[368]
  PIN i[369]
    DIRECTION INPUT ;
    USE SIGNAL ;
    PORT
      LAYER M5 ;
        RECT  67.056 0 67.08 0.192 ;
    END
  END i[369]
  PIN i[36]
    DIRECTION INPUT ;
    USE SIGNAL ;
    PORT
      LAYER M5 ;
        RECT  10.416 0 10.44 0.192 ;
    END
  END i[36]
  PIN i[370]
    DIRECTION INPUT ;
    USE SIGNAL ;
    PORT
      LAYER M5 ;
        RECT  67.248 0 67.272 0.192 ;
    END
  END i[370]
  PIN i[371]
    DIRECTION INPUT ;
    USE SIGNAL ;
    PORT
      LAYER M5 ;
        RECT  67.392 0 67.416 0.192 ;
    END
  END i[371]
  PIN i[372]
    DIRECTION INPUT ;
    USE SIGNAL ;
    PORT
      LAYER M5 ;
        RECT  67.584 0 67.608 0.192 ;
    END
  END i[372]
  PIN i[373]
    DIRECTION INPUT ;
    USE SIGNAL ;
    PORT
      LAYER M5 ;
        RECT  67.728 0 67.752 0.192 ;
    END
  END i[373]
  PIN i[374]
    DIRECTION INPUT ;
    USE SIGNAL ;
    PORT
      LAYER M5 ;
        RECT  67.92 0 67.944 0.192 ;
    END
  END i[374]
  PIN i[375]
    DIRECTION INPUT ;
    USE SIGNAL ;
    PORT
      LAYER M5 ;
        RECT  68.064 0 68.088 0.192 ;
    END
  END i[375]
  PIN i[376]
    DIRECTION INPUT ;
    USE SIGNAL ;
    PORT
      LAYER M5 ;
        RECT  68.256 0 68.28 0.192 ;
    END
  END i[376]
  PIN i[377]
    DIRECTION INPUT ;
    USE SIGNAL ;
    PORT
      LAYER M5 ;
        RECT  68.4 0 68.424 0.192 ;
    END
  END i[377]
  PIN i[378]
    DIRECTION INPUT ;
    USE SIGNAL ;
    PORT
      LAYER M5 ;
        RECT  68.592 0 68.616 0.192 ;
    END
  END i[378]
  PIN i[379]
    DIRECTION INPUT ;
    USE SIGNAL ;
    PORT
      LAYER M5 ;
        RECT  68.784 0 68.808 0.192 ;
    END
  END i[379]
  PIN i[37]
    DIRECTION INPUT ;
    USE SIGNAL ;
    PORT
      LAYER M5 ;
        RECT  10.56 0 10.584 0.192 ;
    END
  END i[37]
  PIN i[380]
    DIRECTION INPUT ;
    USE SIGNAL ;
    PORT
      LAYER M5 ;
        RECT  68.928 0 68.952 0.192 ;
    END
  END i[380]
  PIN i[381]
    DIRECTION INPUT ;
    USE SIGNAL ;
    PORT
      LAYER M5 ;
        RECT  69.12 0 69.144 0.192 ;
    END
  END i[381]
  PIN i[382]
    DIRECTION INPUT ;
    USE SIGNAL ;
    PORT
      LAYER M5 ;
        RECT  69.264 0 69.288 0.192 ;
    END
  END i[382]
  PIN i[383]
    DIRECTION INPUT ;
    USE SIGNAL ;
    PORT
      LAYER M5 ;
        RECT  69.456 0 69.48 0.192 ;
    END
  END i[383]
  PIN i[384]
    DIRECTION INPUT ;
    USE SIGNAL ;
    PORT
      LAYER M5 ;
        RECT  69.6 0 69.624 0.192 ;
    END
  END i[384]
  PIN i[385]
    DIRECTION INPUT ;
    USE SIGNAL ;
    PORT
      LAYER M5 ;
        RECT  69.792 0 69.816 0.192 ;
    END
  END i[385]
  PIN i[386]
    DIRECTION INPUT ;
    USE SIGNAL ;
    PORT
      LAYER M5 ;
        RECT  69.936 0 69.96 0.192 ;
    END
  END i[386]
  PIN i[387]
    DIRECTION INPUT ;
    USE SIGNAL ;
    PORT
      LAYER M5 ;
        RECT  70.128 0 70.152 0.192 ;
    END
  END i[387]
  PIN i[388]
    DIRECTION INPUT ;
    USE SIGNAL ;
    PORT
      LAYER M5 ;
        RECT  70.272 0 70.296 0.192 ;
    END
  END i[388]
  PIN i[389]
    DIRECTION INPUT ;
    USE SIGNAL ;
    PORT
      LAYER M5 ;
        RECT  70.464 0 70.488 0.192 ;
    END
  END i[389]
  PIN i[38]
    DIRECTION INPUT ;
    USE SIGNAL ;
    PORT
      LAYER M5 ;
        RECT  10.752 0 10.776 0.192 ;
    END
  END i[38]
  PIN i[390]
    DIRECTION INPUT ;
    USE SIGNAL ;
    PORT
      LAYER M5 ;
        RECT  70.608 0 70.632 0.192 ;
    END
  END i[390]
  PIN i[391]
    DIRECTION INPUT ;
    USE SIGNAL ;
    PORT
      LAYER M5 ;
        RECT  70.8 0 70.824 0.192 ;
    END
  END i[391]
  PIN i[392]
    DIRECTION INPUT ;
    USE SIGNAL ;
    PORT
      LAYER M5 ;
        RECT  70.944 0 70.968 0.192 ;
    END
  END i[392]
  PIN i[393]
    DIRECTION INPUT ;
    USE SIGNAL ;
    PORT
      LAYER M5 ;
        RECT  71.136 0 71.16 0.192 ;
    END
  END i[393]
  PIN i[394]
    DIRECTION INPUT ;
    USE SIGNAL ;
    PORT
      LAYER M5 ;
        RECT  71.328 0 71.352 0.192 ;
    END
  END i[394]
  PIN i[395]
    DIRECTION INPUT ;
    USE SIGNAL ;
    PORT
      LAYER M5 ;
        RECT  71.472 0 71.496 0.192 ;
    END
  END i[395]
  PIN i[396]
    DIRECTION INPUT ;
    USE SIGNAL ;
    PORT
      LAYER M5 ;
        RECT  71.664 0 71.688 0.192 ;
    END
  END i[396]
  PIN i[397]
    DIRECTION INPUT ;
    USE SIGNAL ;
    PORT
      LAYER M5 ;
        RECT  71.808 0 71.832 0.192 ;
    END
  END i[397]
  PIN i[398]
    DIRECTION INPUT ;
    USE SIGNAL ;
    PORT
      LAYER M5 ;
        RECT  72 0 72.024 0.192 ;
    END
  END i[398]
  PIN i[399]
    DIRECTION INPUT ;
    USE SIGNAL ;
    PORT
      LAYER M5 ;
        RECT  72.144 0 72.168 0.192 ;
    END
  END i[399]
  PIN i[39]
    DIRECTION INPUT ;
    USE SIGNAL ;
    PORT
      LAYER M5 ;
        RECT  10.944 0 10.968 0.192 ;
    END
  END i[39]
  PIN i[3]
    DIRECTION INPUT ;
    USE SIGNAL ;
    PORT
      LAYER M5 ;
        RECT  4.8 0 4.824 0.192 ;
    END
  END i[3]
  PIN i[400]
    DIRECTION INPUT ;
    USE SIGNAL ;
    PORT
      LAYER M5 ;
        RECT  72.336 0 72.36 0.192 ;
    END
  END i[400]
  PIN i[401]
    DIRECTION INPUT ;
    USE SIGNAL ;
    PORT
      LAYER M5 ;
        RECT  72.48 0 72.504 0.192 ;
    END
  END i[401]
  PIN i[402]
    DIRECTION INPUT ;
    USE SIGNAL ;
    PORT
      LAYER M5 ;
        RECT  72.672 0 72.696 0.192 ;
    END
  END i[402]
  PIN i[403]
    DIRECTION INPUT ;
    USE SIGNAL ;
    PORT
      LAYER M5 ;
        RECT  72.816 0 72.84 0.192 ;
    END
  END i[403]
  PIN i[404]
    DIRECTION INPUT ;
    USE SIGNAL ;
    PORT
      LAYER M5 ;
        RECT  73.008 0 73.032 0.192 ;
    END
  END i[404]
  PIN i[405]
    DIRECTION INPUT ;
    USE SIGNAL ;
    PORT
      LAYER M5 ;
        RECT  73.152 0 73.176 0.192 ;
    END
  END i[405]
  PIN i[406]
    DIRECTION INPUT ;
    USE SIGNAL ;
    PORT
      LAYER M5 ;
        RECT  73.344 0 73.368 0.192 ;
    END
  END i[406]
  PIN i[407]
    DIRECTION INPUT ;
    USE SIGNAL ;
    PORT
      LAYER M5 ;
        RECT  73.488 0 73.512 0.192 ;
    END
  END i[407]
  PIN i[408]
    DIRECTION INPUT ;
    USE SIGNAL ;
    PORT
      LAYER M5 ;
        RECT  73.68 0 73.704 0.192 ;
    END
  END i[408]
  PIN i[409]
    DIRECTION INPUT ;
    USE SIGNAL ;
    PORT
      LAYER M5 ;
        RECT  73.872 0 73.896 0.192 ;
    END
  END i[409]
  PIN i[40]
    DIRECTION INPUT ;
    USE SIGNAL ;
    PORT
      LAYER M5 ;
        RECT  11.088 0 11.112 0.192 ;
    END
  END i[40]
  PIN i[410]
    DIRECTION INPUT ;
    USE SIGNAL ;
    PORT
      LAYER M5 ;
        RECT  74.016 0 74.04 0.192 ;
    END
  END i[410]
  PIN i[411]
    DIRECTION INPUT ;
    USE SIGNAL ;
    PORT
      LAYER M5 ;
        RECT  74.208 0 74.232 0.192 ;
    END
  END i[411]
  PIN i[412]
    DIRECTION INPUT ;
    USE SIGNAL ;
    PORT
      LAYER M5 ;
        RECT  74.352 0 74.376 0.192 ;
    END
  END i[412]
  PIN i[413]
    DIRECTION INPUT ;
    USE SIGNAL ;
    PORT
      LAYER M5 ;
        RECT  74.544 0 74.568 0.192 ;
    END
  END i[413]
  PIN i[414]
    DIRECTION INPUT ;
    USE SIGNAL ;
    PORT
      LAYER M5 ;
        RECT  74.688 0 74.712 0.192 ;
    END
  END i[414]
  PIN i[415]
    DIRECTION INPUT ;
    USE SIGNAL ;
    PORT
      LAYER M5 ;
        RECT  74.88 0 74.904 0.192 ;
    END
  END i[415]
  PIN i[416]
    DIRECTION INPUT ;
    USE SIGNAL ;
    PORT
      LAYER M5 ;
        RECT  75.024 0 75.048 0.192 ;
    END
  END i[416]
  PIN i[417]
    DIRECTION INPUT ;
    USE SIGNAL ;
    PORT
      LAYER M5 ;
        RECT  75.216 0 75.24 0.192 ;
    END
  END i[417]
  PIN i[418]
    DIRECTION INPUT ;
    USE SIGNAL ;
    PORT
      LAYER M5 ;
        RECT  75.36 0 75.384 0.192 ;
    END
  END i[418]
  PIN i[419]
    DIRECTION INPUT ;
    USE SIGNAL ;
    PORT
      LAYER M5 ;
        RECT  75.552 0 75.576 0.192 ;
    END
  END i[419]
  PIN i[41]
    DIRECTION INPUT ;
    USE SIGNAL ;
    PORT
      LAYER M5 ;
        RECT  11.28 0 11.304 0.192 ;
    END
  END i[41]
  PIN i[420]
    DIRECTION INPUT ;
    USE SIGNAL ;
    PORT
      LAYER M5 ;
        RECT  75.696 0 75.72 0.192 ;
    END
  END i[420]
  PIN i[421]
    DIRECTION INPUT ;
    USE SIGNAL ;
    PORT
      LAYER M5 ;
        RECT  75.888 0 75.912 0.192 ;
    END
  END i[421]
  PIN i[422]
    DIRECTION INPUT ;
    USE SIGNAL ;
    PORT
      LAYER M5 ;
        RECT  76.032 0 76.056 0.192 ;
    END
  END i[422]
  PIN i[423]
    DIRECTION INPUT ;
    USE SIGNAL ;
    PORT
      LAYER M5 ;
        RECT  76.224 0 76.248 0.192 ;
    END
  END i[423]
  PIN i[424]
    DIRECTION INPUT ;
    USE SIGNAL ;
    PORT
      LAYER M5 ;
        RECT  76.416 0 76.44 0.192 ;
    END
  END i[424]
  PIN i[425]
    DIRECTION INPUT ;
    USE SIGNAL ;
    PORT
      LAYER M5 ;
        RECT  76.56 0 76.584 0.192 ;
    END
  END i[425]
  PIN i[426]
    DIRECTION INPUT ;
    USE SIGNAL ;
    PORT
      LAYER M5 ;
        RECT  76.752 0 76.776 0.192 ;
    END
  END i[426]
  PIN i[427]
    DIRECTION INPUT ;
    USE SIGNAL ;
    PORT
      LAYER M5 ;
        RECT  76.896 0 76.92 0.192 ;
    END
  END i[427]
  PIN i[428]
    DIRECTION INPUT ;
    USE SIGNAL ;
    PORT
      LAYER M5 ;
        RECT  77.088 0 77.112 0.192 ;
    END
  END i[428]
  PIN i[429]
    DIRECTION INPUT ;
    USE SIGNAL ;
    PORT
      LAYER M5 ;
        RECT  77.232 0 77.256 0.192 ;
    END
  END i[429]
  PIN i[42]
    DIRECTION INPUT ;
    USE SIGNAL ;
    PORT
      LAYER M5 ;
        RECT  11.424 0 11.448 0.192 ;
    END
  END i[42]
  PIN i[430]
    DIRECTION INPUT ;
    USE SIGNAL ;
    PORT
      LAYER M5 ;
        RECT  77.424 0 77.448 0.192 ;
    END
  END i[430]
  PIN i[431]
    DIRECTION INPUT ;
    USE SIGNAL ;
    PORT
      LAYER M5 ;
        RECT  77.568 0 77.592 0.192 ;
    END
  END i[431]
  PIN i[432]
    DIRECTION INPUT ;
    USE SIGNAL ;
    PORT
      LAYER M5 ;
        RECT  77.76 0 77.784 0.192 ;
    END
  END i[432]
  PIN i[433]
    DIRECTION INPUT ;
    USE SIGNAL ;
    PORT
      LAYER M5 ;
        RECT  77.904 0 77.928 0.192 ;
    END
  END i[433]
  PIN i[434]
    DIRECTION INPUT ;
    USE SIGNAL ;
    PORT
      LAYER M5 ;
        RECT  78.096 0 78.12 0.192 ;
    END
  END i[434]
  PIN i[435]
    DIRECTION INPUT ;
    USE SIGNAL ;
    PORT
      LAYER M5 ;
        RECT  78.24 0 78.264 0.192 ;
    END
  END i[435]
  PIN i[436]
    DIRECTION INPUT ;
    USE SIGNAL ;
    PORT
      LAYER M5 ;
        RECT  78.432 0 78.456 0.192 ;
    END
  END i[436]
  PIN i[437]
    DIRECTION INPUT ;
    USE SIGNAL ;
    PORT
      LAYER M5 ;
        RECT  78.576 0 78.6 0.192 ;
    END
  END i[437]
  PIN i[438]
    DIRECTION INPUT ;
    USE SIGNAL ;
    PORT
      LAYER M5 ;
        RECT  78.768 0 78.792 0.192 ;
    END
  END i[438]
  PIN i[439]
    DIRECTION INPUT ;
    USE SIGNAL ;
    PORT
      LAYER M5 ;
        RECT  78.96 0 78.984 0.192 ;
    END
  END i[439]
  PIN i[43]
    DIRECTION INPUT ;
    USE SIGNAL ;
    PORT
      LAYER M5 ;
        RECT  11.616 0 11.64 0.192 ;
    END
  END i[43]
  PIN i[440]
    DIRECTION INPUT ;
    USE SIGNAL ;
    PORT
      LAYER M5 ;
        RECT  79.104 0 79.128 0.192 ;
    END
  END i[440]
  PIN i[441]
    DIRECTION INPUT ;
    USE SIGNAL ;
    PORT
      LAYER M5 ;
        RECT  79.296 0 79.32 0.192 ;
    END
  END i[441]
  PIN i[442]
    DIRECTION INPUT ;
    USE SIGNAL ;
    PORT
      LAYER M5 ;
        RECT  79.44 0 79.464 0.192 ;
    END
  END i[442]
  PIN i[443]
    DIRECTION INPUT ;
    USE SIGNAL ;
    PORT
      LAYER M5 ;
        RECT  79.632 0 79.656 0.192 ;
    END
  END i[443]
  PIN i[444]
    DIRECTION INPUT ;
    USE SIGNAL ;
    PORT
      LAYER M5 ;
        RECT  79.776 0 79.8 0.192 ;
    END
  END i[444]
  PIN i[445]
    DIRECTION INPUT ;
    USE SIGNAL ;
    PORT
      LAYER M5 ;
        RECT  79.968 0 79.992 0.192 ;
    END
  END i[445]
  PIN i[446]
    DIRECTION INPUT ;
    USE SIGNAL ;
    PORT
      LAYER M5 ;
        RECT  80.112 0 80.136 0.192 ;
    END
  END i[446]
  PIN i[447]
    DIRECTION INPUT ;
    USE SIGNAL ;
    PORT
      LAYER M5 ;
        RECT  80.304 0 80.328 0.192 ;
    END
  END i[447]
  PIN i[448]
    DIRECTION INPUT ;
    USE SIGNAL ;
    PORT
      LAYER M5 ;
        RECT  80.448 0 80.472 0.192 ;
    END
  END i[448]
  PIN i[449]
    DIRECTION INPUT ;
    USE SIGNAL ;
    PORT
      LAYER M5 ;
        RECT  80.64 0 80.664 0.192 ;
    END
  END i[449]
  PIN i[44]
    DIRECTION INPUT ;
    USE SIGNAL ;
    PORT
      LAYER M5 ;
        RECT  11.76 0 11.784 0.192 ;
    END
  END i[44]
  PIN i[450]
    DIRECTION INPUT ;
    USE SIGNAL ;
    PORT
      LAYER M5 ;
        RECT  80.784 0 80.808 0.192 ;
    END
  END i[450]
  PIN i[451]
    DIRECTION INPUT ;
    USE SIGNAL ;
    PORT
      LAYER M5 ;
        RECT  80.976 0 81 0.192 ;
    END
  END i[451]
  PIN i[452]
    DIRECTION INPUT ;
    USE SIGNAL ;
    PORT
      LAYER M5 ;
        RECT  81.12 0 81.144 0.192 ;
    END
  END i[452]
  PIN i[453]
    DIRECTION INPUT ;
    USE SIGNAL ;
    PORT
      LAYER M5 ;
        RECT  81.312 0 81.336 0.192 ;
    END
  END i[453]
  PIN i[454]
    DIRECTION INPUT ;
    USE SIGNAL ;
    PORT
      LAYER M5 ;
        RECT  81.504 0 81.528 0.192 ;
    END
  END i[454]
  PIN i[455]
    DIRECTION INPUT ;
    USE SIGNAL ;
    PORT
      LAYER M5 ;
        RECT  81.648 0 81.672 0.192 ;
    END
  END i[455]
  PIN i[456]
    DIRECTION INPUT ;
    USE SIGNAL ;
    PORT
      LAYER M5 ;
        RECT  81.84 0 81.864 0.192 ;
    END
  END i[456]
  PIN i[457]
    DIRECTION INPUT ;
    USE SIGNAL ;
    PORT
      LAYER M5 ;
        RECT  81.984 0 82.008 0.192 ;
    END
  END i[457]
  PIN i[458]
    DIRECTION INPUT ;
    USE SIGNAL ;
    PORT
      LAYER M5 ;
        RECT  82.176 0 82.2 0.192 ;
    END
  END i[458]
  PIN i[459]
    DIRECTION INPUT ;
    USE SIGNAL ;
    PORT
      LAYER M5 ;
        RECT  82.32 0 82.344 0.192 ;
    END
  END i[459]
  PIN i[45]
    DIRECTION INPUT ;
    USE SIGNAL ;
    PORT
      LAYER M5 ;
        RECT  11.952 0 11.976 0.192 ;
    END
  END i[45]
  PIN i[460]
    DIRECTION INPUT ;
    USE SIGNAL ;
    PORT
      LAYER M5 ;
        RECT  82.512 0 82.536 0.192 ;
    END
  END i[460]
  PIN i[461]
    DIRECTION INPUT ;
    USE SIGNAL ;
    PORT
      LAYER M5 ;
        RECT  82.656 0 82.68 0.192 ;
    END
  END i[461]
  PIN i[462]
    DIRECTION INPUT ;
    USE SIGNAL ;
    PORT
      LAYER M5 ;
        RECT  82.848 0 82.872 0.192 ;
    END
  END i[462]
  PIN i[463]
    DIRECTION INPUT ;
    USE SIGNAL ;
    PORT
      LAYER M5 ;
        RECT  82.992 0 83.016 0.192 ;
    END
  END i[463]
  PIN i[464]
    DIRECTION INPUT ;
    USE SIGNAL ;
    PORT
      LAYER M5 ;
        RECT  83.184 0 83.208 0.192 ;
    END
  END i[464]
  PIN i[465]
    DIRECTION INPUT ;
    USE SIGNAL ;
    PORT
      LAYER M5 ;
        RECT  83.328 0 83.352 0.192 ;
    END
  END i[465]
  PIN i[466]
    DIRECTION INPUT ;
    USE SIGNAL ;
    PORT
      LAYER M5 ;
        RECT  83.52 0 83.544 0.192 ;
    END
  END i[466]
  PIN i[467]
    DIRECTION INPUT ;
    USE SIGNAL ;
    PORT
      LAYER M5 ;
        RECT  83.664 0 83.688 0.192 ;
    END
  END i[467]
  PIN i[468]
    DIRECTION INPUT ;
    USE SIGNAL ;
    PORT
      LAYER M5 ;
        RECT  83.856 0 83.88 0.192 ;
    END
  END i[468]
  PIN i[469]
    DIRECTION INPUT ;
    USE SIGNAL ;
    PORT
      LAYER M5 ;
        RECT  84.048 0 84.072 0.192 ;
    END
  END i[469]
  PIN i[46]
    DIRECTION INPUT ;
    USE SIGNAL ;
    PORT
      LAYER M5 ;
        RECT  12.096 0 12.12 0.192 ;
    END
  END i[46]
  PIN i[470]
    DIRECTION INPUT ;
    USE SIGNAL ;
    PORT
      LAYER M5 ;
        RECT  84.192 0 84.216 0.192 ;
    END
  END i[470]
  PIN i[471]
    DIRECTION INPUT ;
    USE SIGNAL ;
    PORT
      LAYER M5 ;
        RECT  84.384 0 84.408 0.192 ;
    END
  END i[471]
  PIN i[472]
    DIRECTION INPUT ;
    USE SIGNAL ;
    PORT
      LAYER M5 ;
        RECT  84.528 0 84.552 0.192 ;
    END
  END i[472]
  PIN i[473]
    DIRECTION INPUT ;
    USE SIGNAL ;
    PORT
      LAYER M5 ;
        RECT  84.72 0 84.744 0.192 ;
    END
  END i[473]
  PIN i[474]
    DIRECTION INPUT ;
    USE SIGNAL ;
    PORT
      LAYER M5 ;
        RECT  84.864 0 84.888 0.192 ;
    END
  END i[474]
  PIN i[475]
    DIRECTION INPUT ;
    USE SIGNAL ;
    PORT
      LAYER M5 ;
        RECT  85.056 0 85.08 0.192 ;
    END
  END i[475]
  PIN i[476]
    DIRECTION INPUT ;
    USE SIGNAL ;
    PORT
      LAYER M5 ;
        RECT  85.2 0 85.224 0.192 ;
    END
  END i[476]
  PIN i[477]
    DIRECTION INPUT ;
    USE SIGNAL ;
    PORT
      LAYER M5 ;
        RECT  85.392 0 85.416 0.192 ;
    END
  END i[477]
  PIN i[478]
    DIRECTION INPUT ;
    USE SIGNAL ;
    PORT
      LAYER M5 ;
        RECT  85.536 0 85.56 0.192 ;
    END
  END i[478]
  PIN i[479]
    DIRECTION INPUT ;
    USE SIGNAL ;
    PORT
      LAYER M5 ;
        RECT  85.728 0 85.752 0.192 ;
    END
  END i[479]
  PIN i[47]
    DIRECTION INPUT ;
    USE SIGNAL ;
    PORT
      LAYER M5 ;
        RECT  12.288 0 12.312 0.192 ;
    END
  END i[47]
  PIN i[480]
    DIRECTION INPUT ;
    USE SIGNAL ;
    PORT
      LAYER M5 ;
        RECT  85.872 0 85.896 0.192 ;
    END
  END i[480]
  PIN i[481]
    DIRECTION INPUT ;
    USE SIGNAL ;
    PORT
      LAYER M5 ;
        RECT  86.064 0 86.088 0.192 ;
    END
  END i[481]
  PIN i[482]
    DIRECTION INPUT ;
    USE SIGNAL ;
    PORT
      LAYER M5 ;
        RECT  86.256 0 86.28 0.192 ;
    END
  END i[482]
  PIN i[483]
    DIRECTION INPUT ;
    USE SIGNAL ;
    PORT
      LAYER M5 ;
        RECT  86.4 0 86.424 0.192 ;
    END
  END i[483]
  PIN i[484]
    DIRECTION INPUT ;
    USE SIGNAL ;
    PORT
      LAYER M5 ;
        RECT  86.592 0 86.616 0.192 ;
    END
  END i[484]
  PIN i[485]
    DIRECTION INPUT ;
    USE SIGNAL ;
    PORT
      LAYER M5 ;
        RECT  86.736 0 86.76 0.192 ;
    END
  END i[485]
  PIN i[486]
    DIRECTION INPUT ;
    USE SIGNAL ;
    PORT
      LAYER M5 ;
        RECT  86.928 0 86.952 0.192 ;
    END
  END i[486]
  PIN i[487]
    DIRECTION INPUT ;
    USE SIGNAL ;
    PORT
      LAYER M5 ;
        RECT  87.072 0 87.096 0.192 ;
    END
  END i[487]
  PIN i[488]
    DIRECTION INPUT ;
    USE SIGNAL ;
    PORT
      LAYER M5 ;
        RECT  87.264 0 87.288 0.192 ;
    END
  END i[488]
  PIN i[489]
    DIRECTION INPUT ;
    USE SIGNAL ;
    PORT
      LAYER M5 ;
        RECT  87.408 0 87.432 0.192 ;
    END
  END i[489]
  PIN i[48]
    DIRECTION INPUT ;
    USE SIGNAL ;
    PORT
      LAYER M5 ;
        RECT  12.432 0 12.456 0.192 ;
    END
  END i[48]
  PIN i[490]
    DIRECTION INPUT ;
    USE SIGNAL ;
    PORT
      LAYER M5 ;
        RECT  87.6 0 87.624 0.192 ;
    END
  END i[490]
  PIN i[491]
    DIRECTION INPUT ;
    USE SIGNAL ;
    PORT
      LAYER M5 ;
        RECT  87.744 0 87.768 0.192 ;
    END
  END i[491]
  PIN i[492]
    DIRECTION INPUT ;
    USE SIGNAL ;
    PORT
      LAYER M5 ;
        RECT  87.936 0 87.96 0.192 ;
    END
  END i[492]
  PIN i[493]
    DIRECTION INPUT ;
    USE SIGNAL ;
    PORT
      LAYER M5 ;
        RECT  88.08 0 88.104 0.192 ;
    END
  END i[493]
  PIN i[494]
    DIRECTION INPUT ;
    USE SIGNAL ;
    PORT
      LAYER M5 ;
        RECT  88.272 0 88.296 0.192 ;
    END
  END i[494]
  PIN i[495]
    DIRECTION INPUT ;
    USE SIGNAL ;
    PORT
      LAYER M5 ;
        RECT  88.416 0 88.44 0.192 ;
    END
  END i[495]
  PIN i[496]
    DIRECTION INPUT ;
    USE SIGNAL ;
    PORT
      LAYER M5 ;
        RECT  88.608 0 88.632 0.192 ;
    END
  END i[496]
  PIN i[497]
    DIRECTION INPUT ;
    USE SIGNAL ;
    PORT
      LAYER M5 ;
        RECT  88.8 0 88.824 0.192 ;
    END
  END i[497]
  PIN i[498]
    DIRECTION INPUT ;
    USE SIGNAL ;
    PORT
      LAYER M5 ;
        RECT  88.944 0 88.968 0.192 ;
    END
  END i[498]
  PIN i[499]
    DIRECTION INPUT ;
    USE SIGNAL ;
    PORT
      LAYER M5 ;
        RECT  89.136 0 89.16 0.192 ;
    END
  END i[499]
  PIN i[49]
    DIRECTION INPUT ;
    USE SIGNAL ;
    PORT
      LAYER M5 ;
        RECT  12.624 0 12.648 0.192 ;
    END
  END i[49]
  PIN i[4]
    DIRECTION INPUT ;
    USE SIGNAL ;
    PORT
      LAYER M5 ;
        RECT  4.992 0 5.016 0.192 ;
    END
  END i[4]
  PIN i[500]
    DIRECTION INPUT ;
    USE SIGNAL ;
    PORT
      LAYER M5 ;
        RECT  89.28 0 89.304 0.192 ;
    END
  END i[500]
  PIN i[501]
    DIRECTION INPUT ;
    USE SIGNAL ;
    PORT
      LAYER M5 ;
        RECT  89.472 0 89.496 0.192 ;
    END
  END i[501]
  PIN i[502]
    DIRECTION INPUT ;
    USE SIGNAL ;
    PORT
      LAYER M5 ;
        RECT  89.616 0 89.64 0.192 ;
    END
  END i[502]
  PIN i[503]
    DIRECTION INPUT ;
    USE SIGNAL ;
    PORT
      LAYER M5 ;
        RECT  89.808 0 89.832 0.192 ;
    END
  END i[503]
  PIN i[504]
    DIRECTION INPUT ;
    USE SIGNAL ;
    PORT
      LAYER M5 ;
        RECT  89.952 0 89.976 0.192 ;
    END
  END i[504]
  PIN i[505]
    DIRECTION INPUT ;
    USE SIGNAL ;
    PORT
      LAYER M5 ;
        RECT  90.144 0 90.168 0.192 ;
    END
  END i[505]
  PIN i[506]
    DIRECTION INPUT ;
    USE SIGNAL ;
    PORT
      LAYER M5 ;
        RECT  90.288 0 90.312 0.192 ;
    END
  END i[506]
  PIN i[507]
    DIRECTION INPUT ;
    USE SIGNAL ;
    PORT
      LAYER M5 ;
        RECT  90.48 0 90.504 0.192 ;
    END
  END i[507]
  PIN i[508]
    DIRECTION INPUT ;
    USE SIGNAL ;
    PORT
      LAYER M5 ;
        RECT  90.624 0 90.648 0.192 ;
    END
  END i[508]
  PIN i[509]
    DIRECTION INPUT ;
    USE SIGNAL ;
    PORT
      LAYER M5 ;
        RECT  90.816 0 90.84 0.192 ;
    END
  END i[509]
  PIN i[50]
    DIRECTION INPUT ;
    USE SIGNAL ;
    PORT
      LAYER M5 ;
        RECT  12.768 0 12.792 0.192 ;
    END
  END i[50]
  PIN i[510]
    DIRECTION INPUT ;
    USE SIGNAL ;
    PORT
      LAYER M5 ;
        RECT  90.96 0 90.984 0.192 ;
    END
  END i[510]
  PIN i[511]
    DIRECTION INPUT ;
    USE SIGNAL ;
    PORT
      LAYER M5 ;
        RECT  91.152 0 91.176 0.192 ;
    END
  END i[511]
  PIN i[512]
    DIRECTION INPUT ;
    USE SIGNAL ;
    PORT
      LAYER M5 ;
        RECT  91.344 0 91.368 0.192 ;
    END
  END i[512]
  PIN i[513]
    DIRECTION INPUT ;
    USE SIGNAL ;
    PORT
      LAYER M5 ;
        RECT  91.488 0 91.512 0.192 ;
    END
  END i[513]
  PIN i[514]
    DIRECTION INPUT ;
    USE SIGNAL ;
    PORT
      LAYER M5 ;
        RECT  91.68 0 91.704 0.192 ;
    END
  END i[514]
  PIN i[515]
    DIRECTION INPUT ;
    USE SIGNAL ;
    PORT
      LAYER M5 ;
        RECT  91.824 0 91.848 0.192 ;
    END
  END i[515]
  PIN i[516]
    DIRECTION INPUT ;
    USE SIGNAL ;
    PORT
      LAYER M5 ;
        RECT  92.016 0 92.04 0.192 ;
    END
  END i[516]
  PIN i[517]
    DIRECTION INPUT ;
    USE SIGNAL ;
    PORT
      LAYER M5 ;
        RECT  92.16 0 92.184 0.192 ;
    END
  END i[517]
  PIN i[518]
    DIRECTION INPUT ;
    USE SIGNAL ;
    PORT
      LAYER M5 ;
        RECT  92.352 0 92.376 0.192 ;
    END
  END i[518]
  PIN i[519]
    DIRECTION INPUT ;
    USE SIGNAL ;
    PORT
      LAYER M5 ;
        RECT  92.496 0 92.52 0.192 ;
    END
  END i[519]
  PIN i[51]
    DIRECTION INPUT ;
    USE SIGNAL ;
    PORT
      LAYER M5 ;
        RECT  12.96 0 12.984 0.192 ;
    END
  END i[51]
  PIN i[520]
    DIRECTION INPUT ;
    USE SIGNAL ;
    PORT
      LAYER M5 ;
        RECT  92.688 0 92.712 0.192 ;
    END
  END i[520]
  PIN i[521]
    DIRECTION INPUT ;
    USE SIGNAL ;
    PORT
      LAYER M5 ;
        RECT  92.832 0 92.856 0.192 ;
    END
  END i[521]
  PIN i[522]
    DIRECTION INPUT ;
    USE SIGNAL ;
    PORT
      LAYER M5 ;
        RECT  93.024 0 93.048 0.192 ;
    END
  END i[522]
  PIN i[523]
    DIRECTION INPUT ;
    USE SIGNAL ;
    PORT
      LAYER M5 ;
        RECT  93.168 0 93.192 0.192 ;
    END
  END i[523]
  PIN i[524]
    DIRECTION INPUT ;
    USE SIGNAL ;
    PORT
      LAYER M5 ;
        RECT  93.36 0 93.384 0.192 ;
    END
  END i[524]
  PIN i[525]
    DIRECTION INPUT ;
    USE SIGNAL ;
    PORT
      LAYER M5 ;
        RECT  93.504 0 93.528 0.192 ;
    END
  END i[525]
  PIN i[526]
    DIRECTION INPUT ;
    USE SIGNAL ;
    PORT
      LAYER M5 ;
        RECT  93.696 0 93.72 0.192 ;
    END
  END i[526]
  PIN i[527]
    DIRECTION INPUT ;
    USE SIGNAL ;
    PORT
      LAYER M5 ;
        RECT  93.888 0 93.912 0.192 ;
    END
  END i[527]
  PIN i[528]
    DIRECTION INPUT ;
    USE SIGNAL ;
    PORT
      LAYER M5 ;
        RECT  94.032 0 94.056 0.192 ;
    END
  END i[528]
  PIN i[529]
    DIRECTION INPUT ;
    USE SIGNAL ;
    PORT
      LAYER M5 ;
        RECT  94.224 0 94.248 0.192 ;
    END
  END i[529]
  PIN i[52]
    DIRECTION INPUT ;
    USE SIGNAL ;
    PORT
      LAYER M5 ;
        RECT  13.152 0 13.176 0.192 ;
    END
  END i[52]
  PIN i[530]
    DIRECTION INPUT ;
    USE SIGNAL ;
    PORT
      LAYER M5 ;
        RECT  94.368 0 94.392 0.192 ;
    END
  END i[530]
  PIN i[531]
    DIRECTION INPUT ;
    USE SIGNAL ;
    PORT
      LAYER M5 ;
        RECT  94.56 0 94.584 0.192 ;
    END
  END i[531]
  PIN i[532]
    DIRECTION INPUT ;
    USE SIGNAL ;
    PORT
      LAYER M5 ;
        RECT  94.704 0 94.728 0.192 ;
    END
  END i[532]
  PIN i[533]
    DIRECTION INPUT ;
    USE SIGNAL ;
    PORT
      LAYER M5 ;
        RECT  94.896 0 94.92 0.192 ;
    END
  END i[533]
  PIN i[534]
    DIRECTION INPUT ;
    USE SIGNAL ;
    PORT
      LAYER M5 ;
        RECT  95.04 0 95.064 0.192 ;
    END
  END i[534]
  PIN i[535]
    DIRECTION INPUT ;
    USE SIGNAL ;
    PORT
      LAYER M5 ;
        RECT  95.232 0 95.256 0.192 ;
    END
  END i[535]
  PIN i[536]
    DIRECTION INPUT ;
    USE SIGNAL ;
    PORT
      LAYER M5 ;
        RECT  95.376 0 95.4 0.192 ;
    END
  END i[536]
  PIN i[537]
    DIRECTION INPUT ;
    USE SIGNAL ;
    PORT
      LAYER M5 ;
        RECT  95.568 0 95.592 0.192 ;
    END
  END i[537]
  PIN i[538]
    DIRECTION INPUT ;
    USE SIGNAL ;
    PORT
      LAYER M5 ;
        RECT  95.712 0 95.736 0.192 ;
    END
  END i[538]
  PIN i[539]
    DIRECTION INPUT ;
    USE SIGNAL ;
    PORT
      LAYER M5 ;
        RECT  95.904 0 95.928 0.192 ;
    END
  END i[539]
  PIN i[53]
    DIRECTION INPUT ;
    USE SIGNAL ;
    PORT
      LAYER M5 ;
        RECT  13.296 0 13.32 0.192 ;
    END
  END i[53]
  PIN i[540]
    DIRECTION INPUT ;
    USE SIGNAL ;
    PORT
      LAYER M5 ;
        RECT  96.048 0 96.072 0.192 ;
    END
  END i[540]
  PIN i[541]
    DIRECTION INPUT ;
    USE SIGNAL ;
    PORT
      LAYER M5 ;
        RECT  96.24 0 96.264 0.192 ;
    END
  END i[541]
  PIN i[542]
    DIRECTION INPUT ;
    USE SIGNAL ;
    PORT
      LAYER M5 ;
        RECT  96.432 0 96.456 0.192 ;
    END
  END i[542]
  PIN i[543]
    DIRECTION INPUT ;
    USE SIGNAL ;
    PORT
      LAYER M5 ;
        RECT  96.576 0 96.6 0.192 ;
    END
  END i[543]
  PIN i[544]
    DIRECTION INPUT ;
    USE SIGNAL ;
    PORT
      LAYER M5 ;
        RECT  96.768 0 96.792 0.192 ;
    END
  END i[544]
  PIN i[545]
    DIRECTION INPUT ;
    USE SIGNAL ;
    PORT
      LAYER M5 ;
        RECT  96.912 0 96.936 0.192 ;
    END
  END i[545]
  PIN i[546]
    DIRECTION INPUT ;
    USE SIGNAL ;
    PORT
      LAYER M5 ;
        RECT  97.104 0 97.128 0.192 ;
    END
  END i[546]
  PIN i[547]
    DIRECTION INPUT ;
    USE SIGNAL ;
    PORT
      LAYER M5 ;
        RECT  97.248 0 97.272 0.192 ;
    END
  END i[547]
  PIN i[548]
    DIRECTION INPUT ;
    USE SIGNAL ;
    PORT
      LAYER M5 ;
        RECT  97.44 0 97.464 0.192 ;
    END
  END i[548]
  PIN i[549]
    DIRECTION INPUT ;
    USE SIGNAL ;
    PORT
      LAYER M5 ;
        RECT  97.584 0 97.608 0.192 ;
    END
  END i[549]
  PIN i[54]
    DIRECTION INPUT ;
    USE SIGNAL ;
    PORT
      LAYER M5 ;
        RECT  13.488 0 13.512 0.192 ;
    END
  END i[54]
  PIN i[550]
    DIRECTION INPUT ;
    USE SIGNAL ;
    PORT
      LAYER M5 ;
        RECT  97.776 0 97.8 0.192 ;
    END
  END i[550]
  PIN i[551]
    DIRECTION INPUT ;
    USE SIGNAL ;
    PORT
      LAYER M5 ;
        RECT  97.92 0 97.944 0.192 ;
    END
  END i[551]
  PIN i[552]
    DIRECTION INPUT ;
    USE SIGNAL ;
    PORT
      LAYER M5 ;
        RECT  98.112 0 98.136 0.192 ;
    END
  END i[552]
  PIN i[553]
    DIRECTION INPUT ;
    USE SIGNAL ;
    PORT
      LAYER M5 ;
        RECT  98.256 0 98.28 0.192 ;
    END
  END i[553]
  PIN i[554]
    DIRECTION INPUT ;
    USE SIGNAL ;
    PORT
      LAYER M5 ;
        RECT  98.448 0 98.472 0.192 ;
    END
  END i[554]
  PIN i[555]
    DIRECTION INPUT ;
    USE SIGNAL ;
    PORT
      LAYER M5 ;
        RECT  98.592 0 98.616 0.192 ;
    END
  END i[555]
  PIN i[556]
    DIRECTION INPUT ;
    USE SIGNAL ;
    PORT
      LAYER M5 ;
        RECT  98.784 0 98.808 0.192 ;
    END
  END i[556]
  PIN i[557]
    DIRECTION INPUT ;
    USE SIGNAL ;
    PORT
      LAYER M5 ;
        RECT  98.976 0 99 0.192 ;
    END
  END i[557]
  PIN i[558]
    DIRECTION INPUT ;
    USE SIGNAL ;
    PORT
      LAYER M5 ;
        RECT  99.12 0 99.144 0.192 ;
    END
  END i[558]
  PIN i[559]
    DIRECTION INPUT ;
    USE SIGNAL ;
    PORT
      LAYER M5 ;
        RECT  99.312 0 99.336 0.192 ;
    END
  END i[559]
  PIN i[55]
    DIRECTION INPUT ;
    USE SIGNAL ;
    PORT
      LAYER M5 ;
        RECT  13.632 0 13.656 0.192 ;
    END
  END i[55]
  PIN i[560]
    DIRECTION INPUT ;
    USE SIGNAL ;
    PORT
      LAYER M5 ;
        RECT  99.456 0 99.48 0.192 ;
    END
  END i[560]
  PIN i[561]
    DIRECTION INPUT ;
    USE SIGNAL ;
    PORT
      LAYER M5 ;
        RECT  99.648 0 99.672 0.192 ;
    END
  END i[561]
  PIN i[562]
    DIRECTION INPUT ;
    USE SIGNAL ;
    PORT
      LAYER M5 ;
        RECT  99.792 0 99.816 0.192 ;
    END
  END i[562]
  PIN i[563]
    DIRECTION INPUT ;
    USE SIGNAL ;
    PORT
      LAYER M5 ;
        RECT  99.984 0 100.008 0.192 ;
    END
  END i[563]
  PIN i[564]
    DIRECTION INPUT ;
    USE SIGNAL ;
    PORT
      LAYER M5 ;
        RECT  100.128 0 100.152 0.192 ;
    END
  END i[564]
  PIN i[565]
    DIRECTION INPUT ;
    USE SIGNAL ;
    PORT
      LAYER M5 ;
        RECT  100.32 0 100.344 0.192 ;
    END
  END i[565]
  PIN i[566]
    DIRECTION INPUT ;
    USE SIGNAL ;
    PORT
      LAYER M5 ;
        RECT  100.464 0 100.488 0.192 ;
    END
  END i[566]
  PIN i[567]
    DIRECTION INPUT ;
    USE SIGNAL ;
    PORT
      LAYER M5 ;
        RECT  100.656 0 100.68 0.192 ;
    END
  END i[567]
  PIN i[568]
    DIRECTION INPUT ;
    USE SIGNAL ;
    PORT
      LAYER M5 ;
        RECT  100.8 0 100.824 0.192 ;
    END
  END i[568]
  PIN i[569]
    DIRECTION INPUT ;
    USE SIGNAL ;
    PORT
      LAYER M5 ;
        RECT  100.992 0 101.016 0.192 ;
    END
  END i[569]
  PIN i[56]
    DIRECTION INPUT ;
    USE SIGNAL ;
    PORT
      LAYER M5 ;
        RECT  13.824 0 13.848 0.192 ;
    END
  END i[56]
  PIN i[570]
    DIRECTION INPUT ;
    USE SIGNAL ;
    PORT
      LAYER M5 ;
        RECT  101.136 0 101.16 0.192 ;
    END
  END i[570]
  PIN i[571]
    DIRECTION INPUT ;
    USE SIGNAL ;
    PORT
      LAYER M5 ;
        RECT  101.328 0 101.352 0.192 ;
    END
  END i[571]
  PIN i[572]
    DIRECTION INPUT ;
    USE SIGNAL ;
    PORT
      LAYER M5 ;
        RECT  101.52 0 101.544 0.192 ;
    END
  END i[572]
  PIN i[573]
    DIRECTION INPUT ;
    USE SIGNAL ;
    PORT
      LAYER M5 ;
        RECT  101.664 0 101.688 0.192 ;
    END
  END i[573]
  PIN i[574]
    DIRECTION INPUT ;
    USE SIGNAL ;
    PORT
      LAYER M5 ;
        RECT  101.856 0 101.88 0.192 ;
    END
  END i[574]
  PIN i[575]
    DIRECTION INPUT ;
    USE SIGNAL ;
    PORT
      LAYER M5 ;
        RECT  102 0 102.024 0.192 ;
    END
  END i[575]
  PIN i[576]
    DIRECTION INPUT ;
    USE SIGNAL ;
    PORT
      LAYER M5 ;
        RECT  102.192 0 102.216 0.192 ;
    END
  END i[576]
  PIN i[577]
    DIRECTION INPUT ;
    USE SIGNAL ;
    PORT
      LAYER M5 ;
        RECT  102.336 0 102.36 0.192 ;
    END
  END i[577]
  PIN i[578]
    DIRECTION INPUT ;
    USE SIGNAL ;
    PORT
      LAYER M5 ;
        RECT  102.528 0 102.552 0.192 ;
    END
  END i[578]
  PIN i[579]
    DIRECTION INPUT ;
    USE SIGNAL ;
    PORT
      LAYER M5 ;
        RECT  102.672 0 102.696 0.192 ;
    END
  END i[579]
  PIN i[57]
    DIRECTION INPUT ;
    USE SIGNAL ;
    PORT
      LAYER M5 ;
        RECT  13.968 0 13.992 0.192 ;
    END
  END i[57]
  PIN i[580]
    DIRECTION INPUT ;
    USE SIGNAL ;
    PORT
      LAYER M5 ;
        RECT  102.864 0 102.888 0.192 ;
    END
  END i[580]
  PIN i[581]
    DIRECTION INPUT ;
    USE SIGNAL ;
    PORT
      LAYER M5 ;
        RECT  103.008 0 103.032 0.192 ;
    END
  END i[581]
  PIN i[582]
    DIRECTION INPUT ;
    USE SIGNAL ;
    PORT
      LAYER M5 ;
        RECT  103.2 0 103.224 0.192 ;
    END
  END i[582]
  PIN i[583]
    DIRECTION INPUT ;
    USE SIGNAL ;
    PORT
      LAYER M5 ;
        RECT  103.344 0 103.368 0.192 ;
    END
  END i[583]
  PIN i[584]
    DIRECTION INPUT ;
    USE SIGNAL ;
    PORT
      LAYER M5 ;
        RECT  103.536 0 103.56 0.192 ;
    END
  END i[584]
  PIN i[585]
    DIRECTION INPUT ;
    USE SIGNAL ;
    PORT
      LAYER M5 ;
        RECT  103.68 0 103.704 0.192 ;
    END
  END i[585]
  PIN i[586]
    DIRECTION INPUT ;
    USE SIGNAL ;
    PORT
      LAYER M5 ;
        RECT  103.872 0 103.896 0.192 ;
    END
  END i[586]
  PIN i[587]
    DIRECTION INPUT ;
    USE SIGNAL ;
    PORT
      LAYER M5 ;
        RECT  104.064 0 104.088 0.192 ;
    END
  END i[587]
  PIN i[588]
    DIRECTION INPUT ;
    USE SIGNAL ;
    PORT
      LAYER M5 ;
        RECT  104.208 0 104.232 0.192 ;
    END
  END i[588]
  PIN i[589]
    DIRECTION INPUT ;
    USE SIGNAL ;
    PORT
      LAYER M5 ;
        RECT  104.4 0 104.424 0.192 ;
    END
  END i[589]
  PIN i[58]
    DIRECTION INPUT ;
    USE SIGNAL ;
    PORT
      LAYER M5 ;
        RECT  14.16 0 14.184 0.192 ;
    END
  END i[58]
  PIN i[590]
    DIRECTION INPUT ;
    USE SIGNAL ;
    PORT
      LAYER M5 ;
        RECT  104.544 0 104.568 0.192 ;
    END
  END i[590]
  PIN i[591]
    DIRECTION INPUT ;
    USE SIGNAL ;
    PORT
      LAYER M5 ;
        RECT  104.736 0 104.76 0.192 ;
    END
  END i[591]
  PIN i[592]
    DIRECTION INPUT ;
    USE SIGNAL ;
    PORT
      LAYER M5 ;
        RECT  104.88 0 104.904 0.192 ;
    END
  END i[592]
  PIN i[593]
    DIRECTION INPUT ;
    USE SIGNAL ;
    PORT
      LAYER M5 ;
        RECT  105.072 0 105.096 0.192 ;
    END
  END i[593]
  PIN i[594]
    DIRECTION INPUT ;
    USE SIGNAL ;
    PORT
      LAYER M5 ;
        RECT  105.216 0 105.24 0.192 ;
    END
  END i[594]
  PIN i[595]
    DIRECTION INPUT ;
    USE SIGNAL ;
    PORT
      LAYER M5 ;
        RECT  105.408 0 105.432 0.192 ;
    END
  END i[595]
  PIN i[596]
    DIRECTION INPUT ;
    USE SIGNAL ;
    PORT
      LAYER M5 ;
        RECT  105.552 0 105.576 0.192 ;
    END
  END i[596]
  PIN i[597]
    DIRECTION INPUT ;
    USE SIGNAL ;
    PORT
      LAYER M5 ;
        RECT  105.744 0 105.768 0.192 ;
    END
  END i[597]
  PIN i[598]
    DIRECTION INPUT ;
    USE SIGNAL ;
    PORT
      LAYER M5 ;
        RECT  105.888 0 105.912 0.192 ;
    END
  END i[598]
  PIN i[599]
    DIRECTION INPUT ;
    USE SIGNAL ;
    PORT
      LAYER M5 ;
        RECT  106.08 0 106.104 0.192 ;
    END
  END i[599]
  PIN i[59]
    DIRECTION INPUT ;
    USE SIGNAL ;
    PORT
      LAYER M5 ;
        RECT  14.304 0 14.328 0.192 ;
    END
  END i[59]
  PIN i[5]
    DIRECTION INPUT ;
    USE SIGNAL ;
    PORT
      LAYER M5 ;
        RECT  5.136 0 5.16 0.192 ;
    END
  END i[5]
  PIN i[600]
    DIRECTION INPUT ;
    USE SIGNAL ;
    PORT
      LAYER M5 ;
        RECT  106.224 0 106.248 0.192 ;
    END
  END i[600]
  PIN i[601]
    DIRECTION INPUT ;
    USE SIGNAL ;
    PORT
      LAYER M5 ;
        RECT  106.416 0 106.44 0.192 ;
    END
  END i[601]
  PIN i[602]
    DIRECTION INPUT ;
    USE SIGNAL ;
    PORT
      LAYER M5 ;
        RECT  106.608 0 106.632 0.192 ;
    END
  END i[602]
  PIN i[603]
    DIRECTION INPUT ;
    USE SIGNAL ;
    PORT
      LAYER M5 ;
        RECT  106.752 0 106.776 0.192 ;
    END
  END i[603]
  PIN i[604]
    DIRECTION INPUT ;
    USE SIGNAL ;
    PORT
      LAYER M5 ;
        RECT  106.944 0 106.968 0.192 ;
    END
  END i[604]
  PIN i[605]
    DIRECTION INPUT ;
    USE SIGNAL ;
    PORT
      LAYER M5 ;
        RECT  107.088 0 107.112 0.192 ;
    END
  END i[605]
  PIN i[606]
    DIRECTION INPUT ;
    USE SIGNAL ;
    PORT
      LAYER M5 ;
        RECT  107.28 0 107.304 0.192 ;
    END
  END i[606]
  PIN i[607]
    DIRECTION INPUT ;
    USE SIGNAL ;
    PORT
      LAYER M5 ;
        RECT  107.424 0 107.448 0.192 ;
    END
  END i[607]
  PIN i[608]
    DIRECTION INPUT ;
    USE SIGNAL ;
    PORT
      LAYER M5 ;
        RECT  107.616 0 107.64 0.192 ;
    END
  END i[608]
  PIN i[609]
    DIRECTION INPUT ;
    USE SIGNAL ;
    PORT
      LAYER M5 ;
        RECT  107.76 0 107.784 0.192 ;
    END
  END i[609]
  PIN i[60]
    DIRECTION INPUT ;
    USE SIGNAL ;
    PORT
      LAYER M5 ;
        RECT  14.496 0 14.52 0.192 ;
    END
  END i[60]
  PIN i[610]
    DIRECTION INPUT ;
    USE SIGNAL ;
    PORT
      LAYER M5 ;
        RECT  107.952 0 107.976 0.192 ;
    END
  END i[610]
  PIN i[611]
    DIRECTION INPUT ;
    USE SIGNAL ;
    PORT
      LAYER M5 ;
        RECT  108.096 0 108.12 0.192 ;
    END
  END i[611]
  PIN i[612]
    DIRECTION INPUT ;
    USE SIGNAL ;
    PORT
      LAYER M5 ;
        RECT  108.288 0 108.312 0.192 ;
    END
  END i[612]
  PIN i[613]
    DIRECTION INPUT ;
    USE SIGNAL ;
    PORT
      LAYER M5 ;
        RECT  108.432 0 108.456 0.192 ;
    END
  END i[613]
  PIN i[614]
    DIRECTION INPUT ;
    USE SIGNAL ;
    PORT
      LAYER M5 ;
        RECT  108.624 0 108.648 0.192 ;
    END
  END i[614]
  PIN i[615]
    DIRECTION INPUT ;
    USE SIGNAL ;
    PORT
      LAYER M5 ;
        RECT  108.768 0 108.792 0.192 ;
    END
  END i[615]
  PIN i[616]
    DIRECTION INPUT ;
    USE SIGNAL ;
    PORT
      LAYER M5 ;
        RECT  108.96 0 108.984 0.192 ;
    END
  END i[616]
  PIN i[617]
    DIRECTION INPUT ;
    USE SIGNAL ;
    PORT
      LAYER M5 ;
        RECT  109.152 0 109.176 0.192 ;
    END
  END i[617]
  PIN i[618]
    DIRECTION INPUT ;
    USE SIGNAL ;
    PORT
      LAYER M5 ;
        RECT  109.296 0 109.32 0.192 ;
    END
  END i[618]
  PIN i[619]
    DIRECTION INPUT ;
    USE SIGNAL ;
    PORT
      LAYER M5 ;
        RECT  109.488 0 109.512 0.192 ;
    END
  END i[619]
  PIN i[61]
    DIRECTION INPUT ;
    USE SIGNAL ;
    PORT
      LAYER M5 ;
        RECT  14.64 0 14.664 0.192 ;
    END
  END i[61]
  PIN i[620]
    DIRECTION INPUT ;
    USE SIGNAL ;
    PORT
      LAYER M5 ;
        RECT  109.632 0 109.656 0.192 ;
    END
  END i[620]
  PIN i[621]
    DIRECTION INPUT ;
    USE SIGNAL ;
    PORT
      LAYER M5 ;
        RECT  109.824 0 109.848 0.192 ;
    END
  END i[621]
  PIN i[622]
    DIRECTION INPUT ;
    USE SIGNAL ;
    PORT
      LAYER M5 ;
        RECT  109.968 0 109.992 0.192 ;
    END
  END i[622]
  PIN i[623]
    DIRECTION INPUT ;
    USE SIGNAL ;
    PORT
      LAYER M5 ;
        RECT  110.16 0 110.184 0.192 ;
    END
  END i[623]
  PIN i[62]
    DIRECTION INPUT ;
    USE SIGNAL ;
    PORT
      LAYER M5 ;
        RECT  14.832 0 14.856 0.192 ;
    END
  END i[62]
  PIN i[63]
    DIRECTION INPUT ;
    USE SIGNAL ;
    PORT
      LAYER M5 ;
        RECT  14.976 0 15 0.192 ;
    END
  END i[63]
  PIN i[64]
    DIRECTION INPUT ;
    USE SIGNAL ;
    PORT
      LAYER M5 ;
        RECT  15.168 0 15.192 0.192 ;
    END
  END i[64]
  PIN i[65]
    DIRECTION INPUT ;
    USE SIGNAL ;
    PORT
      LAYER M5 ;
        RECT  15.312 0 15.336 0.192 ;
    END
  END i[65]
  PIN i[66]
    DIRECTION INPUT ;
    USE SIGNAL ;
    PORT
      LAYER M5 ;
        RECT  15.504 0 15.528 0.192 ;
    END
  END i[66]
  PIN i[67]
    DIRECTION INPUT ;
    USE SIGNAL ;
    PORT
      LAYER M5 ;
        RECT  15.696 0 15.72 0.192 ;
    END
  END i[67]
  PIN i[68]
    DIRECTION INPUT ;
    USE SIGNAL ;
    PORT
      LAYER M5 ;
        RECT  15.84 0 15.864 0.192 ;
    END
  END i[68]
  PIN i[69]
    DIRECTION INPUT ;
    USE SIGNAL ;
    PORT
      LAYER M5 ;
        RECT  16.032 0 16.056 0.192 ;
    END
  END i[69]
  PIN i[6]
    DIRECTION INPUT ;
    USE SIGNAL ;
    PORT
      LAYER M5 ;
        RECT  5.328 0 5.352 0.192 ;
    END
  END i[6]
  PIN i[70]
    DIRECTION INPUT ;
    USE SIGNAL ;
    PORT
      LAYER M5 ;
        RECT  16.176 0 16.2 0.192 ;
    END
  END i[70]
  PIN i[71]
    DIRECTION INPUT ;
    USE SIGNAL ;
    PORT
      LAYER M5 ;
        RECT  16.368 0 16.392 0.192 ;
    END
  END i[71]
  PIN i[72]
    DIRECTION INPUT ;
    USE SIGNAL ;
    PORT
      LAYER M5 ;
        RECT  16.512 0 16.536 0.192 ;
    END
  END i[72]
  PIN i[73]
    DIRECTION INPUT ;
    USE SIGNAL ;
    PORT
      LAYER M5 ;
        RECT  16.704 0 16.728 0.192 ;
    END
  END i[73]
  PIN i[74]
    DIRECTION INPUT ;
    USE SIGNAL ;
    PORT
      LAYER M5 ;
        RECT  16.848 0 16.872 0.192 ;
    END
  END i[74]
  PIN i[75]
    DIRECTION INPUT ;
    USE SIGNAL ;
    PORT
      LAYER M5 ;
        RECT  17.04 0 17.064 0.192 ;
    END
  END i[75]
  PIN i[76]
    DIRECTION INPUT ;
    USE SIGNAL ;
    PORT
      LAYER M5 ;
        RECT  17.184 0 17.208 0.192 ;
    END
  END i[76]
  PIN i[77]
    DIRECTION INPUT ;
    USE SIGNAL ;
    PORT
      LAYER M5 ;
        RECT  17.376 0 17.4 0.192 ;
    END
  END i[77]
  PIN i[78]
    DIRECTION INPUT ;
    USE SIGNAL ;
    PORT
      LAYER M5 ;
        RECT  17.52 0 17.544 0.192 ;
    END
  END i[78]
  PIN i[79]
    DIRECTION INPUT ;
    USE SIGNAL ;
    PORT
      LAYER M5 ;
        RECT  17.712 0 17.736 0.192 ;
    END
  END i[79]
  PIN i[7]
    DIRECTION INPUT ;
    USE SIGNAL ;
    PORT
      LAYER M5 ;
        RECT  5.472 0 5.496 0.192 ;
    END
  END i[7]
  PIN i[80]
    DIRECTION INPUT ;
    USE SIGNAL ;
    PORT
      LAYER M5 ;
        RECT  17.856 0 17.88 0.192 ;
    END
  END i[80]
  PIN i[81]
    DIRECTION INPUT ;
    USE SIGNAL ;
    PORT
      LAYER M5 ;
        RECT  18.048 0 18.072 0.192 ;
    END
  END i[81]
  PIN i[82]
    DIRECTION INPUT ;
    USE SIGNAL ;
    PORT
      LAYER M5 ;
        RECT  18.24 0 18.264 0.192 ;
    END
  END i[82]
  PIN i[83]
    DIRECTION INPUT ;
    USE SIGNAL ;
    PORT
      LAYER M5 ;
        RECT  18.384 0 18.408 0.192 ;
    END
  END i[83]
  PIN i[84]
    DIRECTION INPUT ;
    USE SIGNAL ;
    PORT
      LAYER M5 ;
        RECT  18.576 0 18.6 0.192 ;
    END
  END i[84]
  PIN i[85]
    DIRECTION INPUT ;
    USE SIGNAL ;
    PORT
      LAYER M5 ;
        RECT  18.72 0 18.744 0.192 ;
    END
  END i[85]
  PIN i[86]
    DIRECTION INPUT ;
    USE SIGNAL ;
    PORT
      LAYER M5 ;
        RECT  18.912 0 18.936 0.192 ;
    END
  END i[86]
  PIN i[87]
    DIRECTION INPUT ;
    USE SIGNAL ;
    PORT
      LAYER M5 ;
        RECT  19.056 0 19.08 0.192 ;
    END
  END i[87]
  PIN i[88]
    DIRECTION INPUT ;
    USE SIGNAL ;
    PORT
      LAYER M5 ;
        RECT  19.248 0 19.272 0.192 ;
    END
  END i[88]
  PIN i[89]
    DIRECTION INPUT ;
    USE SIGNAL ;
    PORT
      LAYER M5 ;
        RECT  19.392 0 19.416 0.192 ;
    END
  END i[89]
  PIN i[8]
    DIRECTION INPUT ;
    USE SIGNAL ;
    PORT
      LAYER M5 ;
        RECT  5.664 0 5.688 0.192 ;
    END
  END i[8]
  PIN i[90]
    DIRECTION INPUT ;
    USE SIGNAL ;
    PORT
      LAYER M5 ;
        RECT  19.584 0 19.608 0.192 ;
    END
  END i[90]
  PIN i[91]
    DIRECTION INPUT ;
    USE SIGNAL ;
    PORT
      LAYER M5 ;
        RECT  19.728 0 19.752 0.192 ;
    END
  END i[91]
  PIN i[92]
    DIRECTION INPUT ;
    USE SIGNAL ;
    PORT
      LAYER M5 ;
        RECT  19.92 0 19.944 0.192 ;
    END
  END i[92]
  PIN i[93]
    DIRECTION INPUT ;
    USE SIGNAL ;
    PORT
      LAYER M5 ;
        RECT  20.064 0 20.088 0.192 ;
    END
  END i[93]
  PIN i[94]
    DIRECTION INPUT ;
    USE SIGNAL ;
    PORT
      LAYER M5 ;
        RECT  20.256 0 20.28 0.192 ;
    END
  END i[94]
  PIN i[95]
    DIRECTION INPUT ;
    USE SIGNAL ;
    PORT
      LAYER M5 ;
        RECT  20.4 0 20.424 0.192 ;
    END
  END i[95]
  PIN i[96]
    DIRECTION INPUT ;
    USE SIGNAL ;
    PORT
      LAYER M5 ;
        RECT  20.592 0 20.616 0.192 ;
    END
  END i[96]
  PIN i[97]
    DIRECTION INPUT ;
    USE SIGNAL ;
    PORT
      LAYER M5 ;
        RECT  20.784 0 20.808 0.192 ;
    END
  END i[97]
  PIN i[98]
    DIRECTION INPUT ;
    USE SIGNAL ;
    PORT
      LAYER M5 ;
        RECT  20.928 0 20.952 0.192 ;
    END
  END i[98]
  PIN i[99]
    DIRECTION INPUT ;
    USE SIGNAL ;
    PORT
      LAYER M5 ;
        RECT  21.12 0 21.144 0.192 ;
    END
  END i[99]
  PIN i[9]
    DIRECTION INPUT ;
    USE SIGNAL ;
    PORT
      LAYER M5 ;
        RECT  5.856 0 5.88 0.192 ;
    END
  END i[9]
  PIN o[0]
    DIRECTION OUTPUT ;
    USE SIGNAL ;
    PORT
      LAYER M5 ;
        RECT  4.32 21.408 4.344 21.6 ;
    END
  END o[0]
  PIN o[100]
    DIRECTION OUTPUT ;
    USE SIGNAL ;
    PORT
      LAYER M5 ;
        RECT  21.264 21.408 21.288 21.6 ;
    END
  END o[100]
  PIN o[101]
    DIRECTION OUTPUT ;
    USE SIGNAL ;
    PORT
      LAYER M5 ;
        RECT  21.456 21.408 21.48 21.6 ;
    END
  END o[101]
  PIN o[102]
    DIRECTION OUTPUT ;
    USE SIGNAL ;
    PORT
      LAYER M5 ;
        RECT  21.6 21.408 21.624 21.6 ;
    END
  END o[102]
  PIN o[103]
    DIRECTION OUTPUT ;
    USE SIGNAL ;
    PORT
      LAYER M5 ;
        RECT  21.792 21.408 21.816 21.6 ;
    END
  END o[103]
  PIN o[104]
    DIRECTION OUTPUT ;
    USE SIGNAL ;
    PORT
      LAYER M5 ;
        RECT  21.936 21.408 21.96 21.6 ;
    END
  END o[104]
  PIN o[105]
    DIRECTION OUTPUT ;
    USE SIGNAL ;
    PORT
      LAYER M5 ;
        RECT  22.128 21.408 22.152 21.6 ;
    END
  END o[105]
  PIN o[106]
    DIRECTION OUTPUT ;
    USE SIGNAL ;
    PORT
      LAYER M5 ;
        RECT  22.272 21.408 22.296 21.6 ;
    END
  END o[106]
  PIN o[107]
    DIRECTION OUTPUT ;
    USE SIGNAL ;
    PORT
      LAYER M5 ;
        RECT  22.464 21.408 22.488 21.6 ;
    END
  END o[107]
  PIN o[108]
    DIRECTION OUTPUT ;
    USE SIGNAL ;
    PORT
      LAYER M5 ;
        RECT  22.608 21.408 22.632 21.6 ;
    END
  END o[108]
  PIN o[109]
    DIRECTION OUTPUT ;
    USE SIGNAL ;
    PORT
      LAYER M5 ;
        RECT  22.8 21.408 22.824 21.6 ;
    END
  END o[109]
  PIN o[10]
    DIRECTION OUTPUT ;
    USE SIGNAL ;
    PORT
      LAYER M5 ;
        RECT  6 21.408 6.024 21.6 ;
    END
  END o[10]
  PIN o[110]
    DIRECTION OUTPUT ;
    USE SIGNAL ;
    PORT
      LAYER M5 ;
        RECT  22.944 21.408 22.968 21.6 ;
    END
  END o[110]
  PIN o[111]
    DIRECTION OUTPUT ;
    USE SIGNAL ;
    PORT
      LAYER M5 ;
        RECT  23.136 21.408 23.16 21.6 ;
    END
  END o[111]
  PIN o[112]
    DIRECTION OUTPUT ;
    USE SIGNAL ;
    PORT
      LAYER M5 ;
        RECT  23.328 21.408 23.352 21.6 ;
    END
  END o[112]
  PIN o[113]
    DIRECTION OUTPUT ;
    USE SIGNAL ;
    PORT
      LAYER M5 ;
        RECT  23.472 21.408 23.496 21.6 ;
    END
  END o[113]
  PIN o[114]
    DIRECTION OUTPUT ;
    USE SIGNAL ;
    PORT
      LAYER M5 ;
        RECT  23.664 21.408 23.688 21.6 ;
    END
  END o[114]
  PIN o[115]
    DIRECTION OUTPUT ;
    USE SIGNAL ;
    PORT
      LAYER M5 ;
        RECT  23.808 21.408 23.832 21.6 ;
    END
  END o[115]
  PIN o[116]
    DIRECTION OUTPUT ;
    USE SIGNAL ;
    PORT
      LAYER M5 ;
        RECT  24 21.408 24.024 21.6 ;
    END
  END o[116]
  PIN o[117]
    DIRECTION OUTPUT ;
    USE SIGNAL ;
    PORT
      LAYER M5 ;
        RECT  24.144 21.408 24.168 21.6 ;
    END
  END o[117]
  PIN o[118]
    DIRECTION OUTPUT ;
    USE SIGNAL ;
    PORT
      LAYER M5 ;
        RECT  24.336 21.408 24.36 21.6 ;
    END
  END o[118]
  PIN o[119]
    DIRECTION OUTPUT ;
    USE SIGNAL ;
    PORT
      LAYER M5 ;
        RECT  24.48 21.408 24.504 21.6 ;
    END
  END o[119]
  PIN o[11]
    DIRECTION OUTPUT ;
    USE SIGNAL ;
    PORT
      LAYER M5 ;
        RECT  6.192 21.408 6.216 21.6 ;
    END
  END o[11]
  PIN o[120]
    DIRECTION OUTPUT ;
    USE SIGNAL ;
    PORT
      LAYER M5 ;
        RECT  24.672 21.408 24.696 21.6 ;
    END
  END o[120]
  PIN o[121]
    DIRECTION OUTPUT ;
    USE SIGNAL ;
    PORT
      LAYER M5 ;
        RECT  24.816 21.408 24.84 21.6 ;
    END
  END o[121]
  PIN o[122]
    DIRECTION OUTPUT ;
    USE SIGNAL ;
    PORT
      LAYER M5 ;
        RECT  25.008 21.408 25.032 21.6 ;
    END
  END o[122]
  PIN o[123]
    DIRECTION OUTPUT ;
    USE SIGNAL ;
    PORT
      LAYER M5 ;
        RECT  25.152 21.408 25.176 21.6 ;
    END
  END o[123]
  PIN o[124]
    DIRECTION OUTPUT ;
    USE SIGNAL ;
    PORT
      LAYER M5 ;
        RECT  25.344 21.408 25.368 21.6 ;
    END
  END o[124]
  PIN o[125]
    DIRECTION OUTPUT ;
    USE SIGNAL ;
    PORT
      LAYER M5 ;
        RECT  25.488 21.408 25.512 21.6 ;
    END
  END o[125]
  PIN o[126]
    DIRECTION OUTPUT ;
    USE SIGNAL ;
    PORT
      LAYER M5 ;
        RECT  25.68 21.408 25.704 21.6 ;
    END
  END o[126]
  PIN o[127]
    DIRECTION OUTPUT ;
    USE SIGNAL ;
    PORT
      LAYER M5 ;
        RECT  25.872 21.408 25.896 21.6 ;
    END
  END o[127]
  PIN o[128]
    DIRECTION OUTPUT ;
    USE SIGNAL ;
    PORT
      LAYER M5 ;
        RECT  26.016 21.408 26.04 21.6 ;
    END
  END o[128]
  PIN o[129]
    DIRECTION OUTPUT ;
    USE SIGNAL ;
    PORT
      LAYER M5 ;
        RECT  26.208 21.408 26.232 21.6 ;
    END
  END o[129]
  PIN o[12]
    DIRECTION OUTPUT ;
    USE SIGNAL ;
    PORT
      LAYER M5 ;
        RECT  6.336 21.408 6.36 21.6 ;
    END
  END o[12]
  PIN o[130]
    DIRECTION OUTPUT ;
    USE SIGNAL ;
    PORT
      LAYER M5 ;
        RECT  26.352 21.408 26.376 21.6 ;
    END
  END o[130]
  PIN o[131]
    DIRECTION OUTPUT ;
    USE SIGNAL ;
    PORT
      LAYER M5 ;
        RECT  26.544 21.408 26.568 21.6 ;
    END
  END o[131]
  PIN o[132]
    DIRECTION OUTPUT ;
    USE SIGNAL ;
    PORT
      LAYER M5 ;
        RECT  26.688 21.408 26.712 21.6 ;
    END
  END o[132]
  PIN o[133]
    DIRECTION OUTPUT ;
    USE SIGNAL ;
    PORT
      LAYER M5 ;
        RECT  26.88 21.408 26.904 21.6 ;
    END
  END o[133]
  PIN o[134]
    DIRECTION OUTPUT ;
    USE SIGNAL ;
    PORT
      LAYER M5 ;
        RECT  27.024 21.408 27.048 21.6 ;
    END
  END o[134]
  PIN o[135]
    DIRECTION OUTPUT ;
    USE SIGNAL ;
    PORT
      LAYER M5 ;
        RECT  27.216 21.408 27.24 21.6 ;
    END
  END o[135]
  PIN o[136]
    DIRECTION OUTPUT ;
    USE SIGNAL ;
    PORT
      LAYER M5 ;
        RECT  27.36 21.408 27.384 21.6 ;
    END
  END o[136]
  PIN o[137]
    DIRECTION OUTPUT ;
    USE SIGNAL ;
    PORT
      LAYER M5 ;
        RECT  27.552 21.408 27.576 21.6 ;
    END
  END o[137]
  PIN o[138]
    DIRECTION OUTPUT ;
    USE SIGNAL ;
    PORT
      LAYER M5 ;
        RECT  27.696 21.408 27.72 21.6 ;
    END
  END o[138]
  PIN o[139]
    DIRECTION OUTPUT ;
    USE SIGNAL ;
    PORT
      LAYER M5 ;
        RECT  27.888 21.408 27.912 21.6 ;
    END
  END o[139]
  PIN o[13]
    DIRECTION OUTPUT ;
    USE SIGNAL ;
    PORT
      LAYER M5 ;
        RECT  6.528 21.408 6.552 21.6 ;
    END
  END o[13]
  PIN o[140]
    DIRECTION OUTPUT ;
    USE SIGNAL ;
    PORT
      LAYER M5 ;
        RECT  28.032 21.408 28.056 21.6 ;
    END
  END o[140]
  PIN o[141]
    DIRECTION OUTPUT ;
    USE SIGNAL ;
    PORT
      LAYER M5 ;
        RECT  28.224 21.408 28.248 21.6 ;
    END
  END o[141]
  PIN o[142]
    DIRECTION OUTPUT ;
    USE SIGNAL ;
    PORT
      LAYER M5 ;
        RECT  28.416 21.408 28.44 21.6 ;
    END
  END o[142]
  PIN o[143]
    DIRECTION OUTPUT ;
    USE SIGNAL ;
    PORT
      LAYER M5 ;
        RECT  28.56 21.408 28.584 21.6 ;
    END
  END o[143]
  PIN o[144]
    DIRECTION OUTPUT ;
    USE SIGNAL ;
    PORT
      LAYER M5 ;
        RECT  28.752 21.408 28.776 21.6 ;
    END
  END o[144]
  PIN o[145]
    DIRECTION OUTPUT ;
    USE SIGNAL ;
    PORT
      LAYER M5 ;
        RECT  28.896 21.408 28.92 21.6 ;
    END
  END o[145]
  PIN o[146]
    DIRECTION OUTPUT ;
    USE SIGNAL ;
    PORT
      LAYER M5 ;
        RECT  29.088 21.408 29.112 21.6 ;
    END
  END o[146]
  PIN o[147]
    DIRECTION OUTPUT ;
    USE SIGNAL ;
    PORT
      LAYER M5 ;
        RECT  29.232 21.408 29.256 21.6 ;
    END
  END o[147]
  PIN o[148]
    DIRECTION OUTPUT ;
    USE SIGNAL ;
    PORT
      LAYER M5 ;
        RECT  29.424 21.408 29.448 21.6 ;
    END
  END o[148]
  PIN o[149]
    DIRECTION OUTPUT ;
    USE SIGNAL ;
    PORT
      LAYER M5 ;
        RECT  29.568 21.408 29.592 21.6 ;
    END
  END o[149]
  PIN o[14]
    DIRECTION OUTPUT ;
    USE SIGNAL ;
    PORT
      LAYER M5 ;
        RECT  6.672 21.408 6.696 21.6 ;
    END
  END o[14]
  PIN o[150]
    DIRECTION OUTPUT ;
    USE SIGNAL ;
    PORT
      LAYER M5 ;
        RECT  29.76 21.408 29.784 21.6 ;
    END
  END o[150]
  PIN o[151]
    DIRECTION OUTPUT ;
    USE SIGNAL ;
    PORT
      LAYER M5 ;
        RECT  29.904 21.408 29.928 21.6 ;
    END
  END o[151]
  PIN o[152]
    DIRECTION OUTPUT ;
    USE SIGNAL ;
    PORT
      LAYER M5 ;
        RECT  30.096 21.408 30.12 21.6 ;
    END
  END o[152]
  PIN o[153]
    DIRECTION OUTPUT ;
    USE SIGNAL ;
    PORT
      LAYER M5 ;
        RECT  30.24 21.408 30.264 21.6 ;
    END
  END o[153]
  PIN o[154]
    DIRECTION OUTPUT ;
    USE SIGNAL ;
    PORT
      LAYER M5 ;
        RECT  30.432 21.408 30.456 21.6 ;
    END
  END o[154]
  PIN o[155]
    DIRECTION OUTPUT ;
    USE SIGNAL ;
    PORT
      LAYER M5 ;
        RECT  30.576 21.408 30.6 21.6 ;
    END
  END o[155]
  PIN o[156]
    DIRECTION OUTPUT ;
    USE SIGNAL ;
    PORT
      LAYER M5 ;
        RECT  30.768 21.408 30.792 21.6 ;
    END
  END o[156]
  PIN o[157]
    DIRECTION OUTPUT ;
    USE SIGNAL ;
    PORT
      LAYER M5 ;
        RECT  30.96 21.408 30.984 21.6 ;
    END
  END o[157]
  PIN o[158]
    DIRECTION OUTPUT ;
    USE SIGNAL ;
    PORT
      LAYER M5 ;
        RECT  31.104 21.408 31.128 21.6 ;
    END
  END o[158]
  PIN o[159]
    DIRECTION OUTPUT ;
    USE SIGNAL ;
    PORT
      LAYER M5 ;
        RECT  31.296 21.408 31.32 21.6 ;
    END
  END o[159]
  PIN o[15]
    DIRECTION OUTPUT ;
    USE SIGNAL ;
    PORT
      LAYER M5 ;
        RECT  6.864 21.408 6.888 21.6 ;
    END
  END o[15]
  PIN o[160]
    DIRECTION OUTPUT ;
    USE SIGNAL ;
    PORT
      LAYER M5 ;
        RECT  31.44 21.408 31.464 21.6 ;
    END
  END o[160]
  PIN o[161]
    DIRECTION OUTPUT ;
    USE SIGNAL ;
    PORT
      LAYER M5 ;
        RECT  31.632 21.408 31.656 21.6 ;
    END
  END o[161]
  PIN o[162]
    DIRECTION OUTPUT ;
    USE SIGNAL ;
    PORT
      LAYER M5 ;
        RECT  31.776 21.408 31.8 21.6 ;
    END
  END o[162]
  PIN o[163]
    DIRECTION OUTPUT ;
    USE SIGNAL ;
    PORT
      LAYER M5 ;
        RECT  31.968 21.408 31.992 21.6 ;
    END
  END o[163]
  PIN o[164]
    DIRECTION OUTPUT ;
    USE SIGNAL ;
    PORT
      LAYER M5 ;
        RECT  32.112 21.408 32.136 21.6 ;
    END
  END o[164]
  PIN o[165]
    DIRECTION OUTPUT ;
    USE SIGNAL ;
    PORT
      LAYER M5 ;
        RECT  32.304 21.408 32.328 21.6 ;
    END
  END o[165]
  PIN o[166]
    DIRECTION OUTPUT ;
    USE SIGNAL ;
    PORT
      LAYER M5 ;
        RECT  32.448 21.408 32.472 21.6 ;
    END
  END o[166]
  PIN o[167]
    DIRECTION OUTPUT ;
    USE SIGNAL ;
    PORT
      LAYER M5 ;
        RECT  32.64 21.408 32.664 21.6 ;
    END
  END o[167]
  PIN o[168]
    DIRECTION OUTPUT ;
    USE SIGNAL ;
    PORT
      LAYER M5 ;
        RECT  32.784 21.408 32.808 21.6 ;
    END
  END o[168]
  PIN o[169]
    DIRECTION OUTPUT ;
    USE SIGNAL ;
    PORT
      LAYER M5 ;
        RECT  32.976 21.408 33 21.6 ;
    END
  END o[169]
  PIN o[16]
    DIRECTION OUTPUT ;
    USE SIGNAL ;
    PORT
      LAYER M5 ;
        RECT  7.008 21.408 7.032 21.6 ;
    END
  END o[16]
  PIN o[170]
    DIRECTION OUTPUT ;
    USE SIGNAL ;
    PORT
      LAYER M5 ;
        RECT  33.12 21.408 33.144 21.6 ;
    END
  END o[170]
  PIN o[171]
    DIRECTION OUTPUT ;
    USE SIGNAL ;
    PORT
      LAYER M5 ;
        RECT  33.312 21.408 33.336 21.6 ;
    END
  END o[171]
  PIN o[172]
    DIRECTION OUTPUT ;
    USE SIGNAL ;
    PORT
      LAYER M5 ;
        RECT  33.504 21.408 33.528 21.6 ;
    END
  END o[172]
  PIN o[173]
    DIRECTION OUTPUT ;
    USE SIGNAL ;
    PORT
      LAYER M5 ;
        RECT  33.648 21.408 33.672 21.6 ;
    END
  END o[173]
  PIN o[174]
    DIRECTION OUTPUT ;
    USE SIGNAL ;
    PORT
      LAYER M5 ;
        RECT  33.84 21.408 33.864 21.6 ;
    END
  END o[174]
  PIN o[175]
    DIRECTION OUTPUT ;
    USE SIGNAL ;
    PORT
      LAYER M5 ;
        RECT  33.984 21.408 34.008 21.6 ;
    END
  END o[175]
  PIN o[176]
    DIRECTION OUTPUT ;
    USE SIGNAL ;
    PORT
      LAYER M5 ;
        RECT  34.176 21.408 34.2 21.6 ;
    END
  END o[176]
  PIN o[177]
    DIRECTION OUTPUT ;
    USE SIGNAL ;
    PORT
      LAYER M5 ;
        RECT  34.32 21.408 34.344 21.6 ;
    END
  END o[177]
  PIN o[178]
    DIRECTION OUTPUT ;
    USE SIGNAL ;
    PORT
      LAYER M5 ;
        RECT  34.512 21.408 34.536 21.6 ;
    END
  END o[178]
  PIN o[179]
    DIRECTION OUTPUT ;
    USE SIGNAL ;
    PORT
      LAYER M5 ;
        RECT  34.656 21.408 34.68 21.6 ;
    END
  END o[179]
  PIN o[17]
    DIRECTION OUTPUT ;
    USE SIGNAL ;
    PORT
      LAYER M5 ;
        RECT  7.2 21.408 7.224 21.6 ;
    END
  END o[17]
  PIN o[180]
    DIRECTION OUTPUT ;
    USE SIGNAL ;
    PORT
      LAYER M5 ;
        RECT  34.848 21.408 34.872 21.6 ;
    END
  END o[180]
  PIN o[181]
    DIRECTION OUTPUT ;
    USE SIGNAL ;
    PORT
      LAYER M5 ;
        RECT  34.992 21.408 35.016 21.6 ;
    END
  END o[181]
  PIN o[182]
    DIRECTION OUTPUT ;
    USE SIGNAL ;
    PORT
      LAYER M5 ;
        RECT  35.184 21.408 35.208 21.6 ;
    END
  END o[182]
  PIN o[183]
    DIRECTION OUTPUT ;
    USE SIGNAL ;
    PORT
      LAYER M5 ;
        RECT  35.328 21.408 35.352 21.6 ;
    END
  END o[183]
  PIN o[184]
    DIRECTION OUTPUT ;
    USE SIGNAL ;
    PORT
      LAYER M5 ;
        RECT  35.52 21.408 35.544 21.6 ;
    END
  END o[184]
  PIN o[185]
    DIRECTION OUTPUT ;
    USE SIGNAL ;
    PORT
      LAYER M5 ;
        RECT  35.664 21.408 35.688 21.6 ;
    END
  END o[185]
  PIN o[186]
    DIRECTION OUTPUT ;
    USE SIGNAL ;
    PORT
      LAYER M5 ;
        RECT  35.856 21.408 35.88 21.6 ;
    END
  END o[186]
  PIN o[187]
    DIRECTION OUTPUT ;
    USE SIGNAL ;
    PORT
      LAYER M5 ;
        RECT  36.048 21.408 36.072 21.6 ;
    END
  END o[187]
  PIN o[188]
    DIRECTION OUTPUT ;
    USE SIGNAL ;
    PORT
      LAYER M5 ;
        RECT  36.192 21.408 36.216 21.6 ;
    END
  END o[188]
  PIN o[189]
    DIRECTION OUTPUT ;
    USE SIGNAL ;
    PORT
      LAYER M5 ;
        RECT  36.384 21.408 36.408 21.6 ;
    END
  END o[189]
  PIN o[18]
    DIRECTION OUTPUT ;
    USE SIGNAL ;
    PORT
      LAYER M5 ;
        RECT  7.344 21.408 7.368 21.6 ;
    END
  END o[18]
  PIN o[190]
    DIRECTION OUTPUT ;
    USE SIGNAL ;
    PORT
      LAYER M5 ;
        RECT  36.528 21.408 36.552 21.6 ;
    END
  END o[190]
  PIN o[191]
    DIRECTION OUTPUT ;
    USE SIGNAL ;
    PORT
      LAYER M5 ;
        RECT  36.72 21.408 36.744 21.6 ;
    END
  END o[191]
  PIN o[192]
    DIRECTION OUTPUT ;
    USE SIGNAL ;
    PORT
      LAYER M5 ;
        RECT  36.864 21.408 36.888 21.6 ;
    END
  END o[192]
  PIN o[193]
    DIRECTION OUTPUT ;
    USE SIGNAL ;
    PORT
      LAYER M5 ;
        RECT  37.056 21.408 37.08 21.6 ;
    END
  END o[193]
  PIN o[194]
    DIRECTION OUTPUT ;
    USE SIGNAL ;
    PORT
      LAYER M5 ;
        RECT  37.2 21.408 37.224 21.6 ;
    END
  END o[194]
  PIN o[195]
    DIRECTION OUTPUT ;
    USE SIGNAL ;
    PORT
      LAYER M5 ;
        RECT  37.392 21.408 37.416 21.6 ;
    END
  END o[195]
  PIN o[196]
    DIRECTION OUTPUT ;
    USE SIGNAL ;
    PORT
      LAYER M5 ;
        RECT  37.536 21.408 37.56 21.6 ;
    END
  END o[196]
  PIN o[197]
    DIRECTION OUTPUT ;
    USE SIGNAL ;
    PORT
      LAYER M5 ;
        RECT  37.728 21.408 37.752 21.6 ;
    END
  END o[197]
  PIN o[198]
    DIRECTION OUTPUT ;
    USE SIGNAL ;
    PORT
      LAYER M5 ;
        RECT  37.872 21.408 37.896 21.6 ;
    END
  END o[198]
  PIN o[199]
    DIRECTION OUTPUT ;
    USE SIGNAL ;
    PORT
      LAYER M5 ;
        RECT  38.064 21.408 38.088 21.6 ;
    END
  END o[199]
  PIN o[19]
    DIRECTION OUTPUT ;
    USE SIGNAL ;
    PORT
      LAYER M5 ;
        RECT  7.536 21.408 7.56 21.6 ;
    END
  END o[19]
  PIN o[1]
    DIRECTION OUTPUT ;
    USE SIGNAL ;
    PORT
      LAYER M5 ;
        RECT  4.464 21.408 4.488 21.6 ;
    END
  END o[1]
  PIN o[200]
    DIRECTION OUTPUT ;
    USE SIGNAL ;
    PORT
      LAYER M5 ;
        RECT  38.208 21.408 38.232 21.6 ;
    END
  END o[200]
  PIN o[201]
    DIRECTION OUTPUT ;
    USE SIGNAL ;
    PORT
      LAYER M5 ;
        RECT  38.4 21.408 38.424 21.6 ;
    END
  END o[201]
  PIN o[202]
    DIRECTION OUTPUT ;
    USE SIGNAL ;
    PORT
      LAYER M5 ;
        RECT  38.592 21.408 38.616 21.6 ;
    END
  END o[202]
  PIN o[203]
    DIRECTION OUTPUT ;
    USE SIGNAL ;
    PORT
      LAYER M5 ;
        RECT  38.736 21.408 38.76 21.6 ;
    END
  END o[203]
  PIN o[204]
    DIRECTION OUTPUT ;
    USE SIGNAL ;
    PORT
      LAYER M5 ;
        RECT  38.928 21.408 38.952 21.6 ;
    END
  END o[204]
  PIN o[205]
    DIRECTION OUTPUT ;
    USE SIGNAL ;
    PORT
      LAYER M5 ;
        RECT  39.072 21.408 39.096 21.6 ;
    END
  END o[205]
  PIN o[206]
    DIRECTION OUTPUT ;
    USE SIGNAL ;
    PORT
      LAYER M5 ;
        RECT  39.264 21.408 39.288 21.6 ;
    END
  END o[206]
  PIN o[207]
    DIRECTION OUTPUT ;
    USE SIGNAL ;
    PORT
      LAYER M5 ;
        RECT  39.408 21.408 39.432 21.6 ;
    END
  END o[207]
  PIN o[208]
    DIRECTION OUTPUT ;
    USE SIGNAL ;
    PORT
      LAYER M5 ;
        RECT  39.6 21.408 39.624 21.6 ;
    END
  END o[208]
  PIN o[209]
    DIRECTION OUTPUT ;
    USE SIGNAL ;
    PORT
      LAYER M5 ;
        RECT  39.744 21.408 39.768 21.6 ;
    END
  END o[209]
  PIN o[20]
    DIRECTION OUTPUT ;
    USE SIGNAL ;
    PORT
      LAYER M5 ;
        RECT  7.68 21.408 7.704 21.6 ;
    END
  END o[20]
  PIN o[210]
    DIRECTION OUTPUT ;
    USE SIGNAL ;
    PORT
      LAYER M5 ;
        RECT  39.936 21.408 39.96 21.6 ;
    END
  END o[210]
  PIN o[211]
    DIRECTION OUTPUT ;
    USE SIGNAL ;
    PORT
      LAYER M5 ;
        RECT  40.08 21.408 40.104 21.6 ;
    END
  END o[211]
  PIN o[212]
    DIRECTION OUTPUT ;
    USE SIGNAL ;
    PORT
      LAYER M5 ;
        RECT  40.272 21.408 40.296 21.6 ;
    END
  END o[212]
  PIN o[213]
    DIRECTION OUTPUT ;
    USE SIGNAL ;
    PORT
      LAYER M5 ;
        RECT  40.416 21.408 40.44 21.6 ;
    END
  END o[213]
  PIN o[214]
    DIRECTION OUTPUT ;
    USE SIGNAL ;
    PORT
      LAYER M5 ;
        RECT  40.608 21.408 40.632 21.6 ;
    END
  END o[214]
  PIN o[215]
    DIRECTION OUTPUT ;
    USE SIGNAL ;
    PORT
      LAYER M5 ;
        RECT  40.752 21.408 40.776 21.6 ;
    END
  END o[215]
  PIN o[216]
    DIRECTION OUTPUT ;
    USE SIGNAL ;
    PORT
      LAYER M5 ;
        RECT  40.944 21.408 40.968 21.6 ;
    END
  END o[216]
  PIN o[217]
    DIRECTION OUTPUT ;
    USE SIGNAL ;
    PORT
      LAYER M5 ;
        RECT  41.136 21.408 41.16 21.6 ;
    END
  END o[217]
  PIN o[218]
    DIRECTION OUTPUT ;
    USE SIGNAL ;
    PORT
      LAYER M5 ;
        RECT  41.28 21.408 41.304 21.6 ;
    END
  END o[218]
  PIN o[219]
    DIRECTION OUTPUT ;
    USE SIGNAL ;
    PORT
      LAYER M5 ;
        RECT  41.472 21.408 41.496 21.6 ;
    END
  END o[219]
  PIN o[21]
    DIRECTION OUTPUT ;
    USE SIGNAL ;
    PORT
      LAYER M5 ;
        RECT  7.872 21.408 7.896 21.6 ;
    END
  END o[21]
  PIN o[220]
    DIRECTION OUTPUT ;
    USE SIGNAL ;
    PORT
      LAYER M5 ;
        RECT  41.616 21.408 41.64 21.6 ;
    END
  END o[220]
  PIN o[221]
    DIRECTION OUTPUT ;
    USE SIGNAL ;
    PORT
      LAYER M5 ;
        RECT  41.808 21.408 41.832 21.6 ;
    END
  END o[221]
  PIN o[222]
    DIRECTION OUTPUT ;
    USE SIGNAL ;
    PORT
      LAYER M5 ;
        RECT  41.952 21.408 41.976 21.6 ;
    END
  END o[222]
  PIN o[223]
    DIRECTION OUTPUT ;
    USE SIGNAL ;
    PORT
      LAYER M5 ;
        RECT  42.144 21.408 42.168 21.6 ;
    END
  END o[223]
  PIN o[224]
    DIRECTION OUTPUT ;
    USE SIGNAL ;
    PORT
      LAYER M5 ;
        RECT  42.288 21.408 42.312 21.6 ;
    END
  END o[224]
  PIN o[225]
    DIRECTION OUTPUT ;
    USE SIGNAL ;
    PORT
      LAYER M5 ;
        RECT  42.48 21.408 42.504 21.6 ;
    END
  END o[225]
  PIN o[226]
    DIRECTION OUTPUT ;
    USE SIGNAL ;
    PORT
      LAYER M5 ;
        RECT  42.624 21.408 42.648 21.6 ;
    END
  END o[226]
  PIN o[227]
    DIRECTION OUTPUT ;
    USE SIGNAL ;
    PORT
      LAYER M5 ;
        RECT  42.816 21.408 42.84 21.6 ;
    END
  END o[227]
  PIN o[228]
    DIRECTION OUTPUT ;
    USE SIGNAL ;
    PORT
      LAYER M5 ;
        RECT  42.96 21.408 42.984 21.6 ;
    END
  END o[228]
  PIN o[229]
    DIRECTION OUTPUT ;
    USE SIGNAL ;
    PORT
      LAYER M5 ;
        RECT  43.152 21.408 43.176 21.6 ;
    END
  END o[229]
  PIN o[22]
    DIRECTION OUTPUT ;
    USE SIGNAL ;
    PORT
      LAYER M5 ;
        RECT  8.016 21.408 8.04 21.6 ;
    END
  END o[22]
  PIN o[230]
    DIRECTION OUTPUT ;
    USE SIGNAL ;
    PORT
      LAYER M5 ;
        RECT  43.296 21.408 43.32 21.6 ;
    END
  END o[230]
  PIN o[231]
    DIRECTION OUTPUT ;
    USE SIGNAL ;
    PORT
      LAYER M5 ;
        RECT  43.488 21.408 43.512 21.6 ;
    END
  END o[231]
  PIN o[232]
    DIRECTION OUTPUT ;
    USE SIGNAL ;
    PORT
      LAYER M5 ;
        RECT  43.68 21.408 43.704 21.6 ;
    END
  END o[232]
  PIN o[233]
    DIRECTION OUTPUT ;
    USE SIGNAL ;
    PORT
      LAYER M5 ;
        RECT  43.824 21.408 43.848 21.6 ;
    END
  END o[233]
  PIN o[234]
    DIRECTION OUTPUT ;
    USE SIGNAL ;
    PORT
      LAYER M5 ;
        RECT  44.016 21.408 44.04 21.6 ;
    END
  END o[234]
  PIN o[235]
    DIRECTION OUTPUT ;
    USE SIGNAL ;
    PORT
      LAYER M5 ;
        RECT  44.16 21.408 44.184 21.6 ;
    END
  END o[235]
  PIN o[236]
    DIRECTION OUTPUT ;
    USE SIGNAL ;
    PORT
      LAYER M5 ;
        RECT  44.352 21.408 44.376 21.6 ;
    END
  END o[236]
  PIN o[237]
    DIRECTION OUTPUT ;
    USE SIGNAL ;
    PORT
      LAYER M5 ;
        RECT  44.496 21.408 44.52 21.6 ;
    END
  END o[237]
  PIN o[238]
    DIRECTION OUTPUT ;
    USE SIGNAL ;
    PORT
      LAYER M5 ;
        RECT  44.688 21.408 44.712 21.6 ;
    END
  END o[238]
  PIN o[239]
    DIRECTION OUTPUT ;
    USE SIGNAL ;
    PORT
      LAYER M5 ;
        RECT  44.832 21.408 44.856 21.6 ;
    END
  END o[239]
  PIN o[23]
    DIRECTION OUTPUT ;
    USE SIGNAL ;
    PORT
      LAYER M5 ;
        RECT  8.208 21.408 8.232 21.6 ;
    END
  END o[23]
  PIN o[240]
    DIRECTION OUTPUT ;
    USE SIGNAL ;
    PORT
      LAYER M5 ;
        RECT  45.024 21.408 45.048 21.6 ;
    END
  END o[240]
  PIN o[241]
    DIRECTION OUTPUT ;
    USE SIGNAL ;
    PORT
      LAYER M5 ;
        RECT  45.168 21.408 45.192 21.6 ;
    END
  END o[241]
  PIN o[242]
    DIRECTION OUTPUT ;
    USE SIGNAL ;
    PORT
      LAYER M5 ;
        RECT  45.36 21.408 45.384 21.6 ;
    END
  END o[242]
  PIN o[243]
    DIRECTION OUTPUT ;
    USE SIGNAL ;
    PORT
      LAYER M5 ;
        RECT  45.504 21.408 45.528 21.6 ;
    END
  END o[243]
  PIN o[244]
    DIRECTION OUTPUT ;
    USE SIGNAL ;
    PORT
      LAYER M5 ;
        RECT  45.696 21.408 45.72 21.6 ;
    END
  END o[244]
  PIN o[245]
    DIRECTION OUTPUT ;
    USE SIGNAL ;
    PORT
      LAYER M5 ;
        RECT  45.84 21.408 45.864 21.6 ;
    END
  END o[245]
  PIN o[246]
    DIRECTION OUTPUT ;
    USE SIGNAL ;
    PORT
      LAYER M5 ;
        RECT  46.032 21.408 46.056 21.6 ;
    END
  END o[246]
  PIN o[247]
    DIRECTION OUTPUT ;
    USE SIGNAL ;
    PORT
      LAYER M5 ;
        RECT  46.224 21.408 46.248 21.6 ;
    END
  END o[247]
  PIN o[248]
    DIRECTION OUTPUT ;
    USE SIGNAL ;
    PORT
      LAYER M5 ;
        RECT  46.368 21.408 46.392 21.6 ;
    END
  END o[248]
  PIN o[249]
    DIRECTION OUTPUT ;
    USE SIGNAL ;
    PORT
      LAYER M5 ;
        RECT  46.56 21.408 46.584 21.6 ;
    END
  END o[249]
  PIN o[24]
    DIRECTION OUTPUT ;
    USE SIGNAL ;
    PORT
      LAYER M5 ;
        RECT  8.4 21.408 8.424 21.6 ;
    END
  END o[24]
  PIN o[250]
    DIRECTION OUTPUT ;
    USE SIGNAL ;
    PORT
      LAYER M5 ;
        RECT  46.704 21.408 46.728 21.6 ;
    END
  END o[250]
  PIN o[251]
    DIRECTION OUTPUT ;
    USE SIGNAL ;
    PORT
      LAYER M5 ;
        RECT  46.896 21.408 46.92 21.6 ;
    END
  END o[251]
  PIN o[252]
    DIRECTION OUTPUT ;
    USE SIGNAL ;
    PORT
      LAYER M5 ;
        RECT  47.04 21.408 47.064 21.6 ;
    END
  END o[252]
  PIN o[253]
    DIRECTION OUTPUT ;
    USE SIGNAL ;
    PORT
      LAYER M5 ;
        RECT  47.232 21.408 47.256 21.6 ;
    END
  END o[253]
  PIN o[254]
    DIRECTION OUTPUT ;
    USE SIGNAL ;
    PORT
      LAYER M5 ;
        RECT  47.376 21.408 47.4 21.6 ;
    END
  END o[254]
  PIN o[255]
    DIRECTION OUTPUT ;
    USE SIGNAL ;
    PORT
      LAYER M5 ;
        RECT  47.568 21.408 47.592 21.6 ;
    END
  END o[255]
  PIN o[256]
    DIRECTION OUTPUT ;
    USE SIGNAL ;
    PORT
      LAYER M5 ;
        RECT  47.712 21.408 47.736 21.6 ;
    END
  END o[256]
  PIN o[257]
    DIRECTION OUTPUT ;
    USE SIGNAL ;
    PORT
      LAYER M5 ;
        RECT  47.904 21.408 47.928 21.6 ;
    END
  END o[257]
  PIN o[258]
    DIRECTION OUTPUT ;
    USE SIGNAL ;
    PORT
      LAYER M5 ;
        RECT  48.048 21.408 48.072 21.6 ;
    END
  END o[258]
  PIN o[259]
    DIRECTION OUTPUT ;
    USE SIGNAL ;
    PORT
      LAYER M5 ;
        RECT  48.24 21.408 48.264 21.6 ;
    END
  END o[259]
  PIN o[25]
    DIRECTION OUTPUT ;
    USE SIGNAL ;
    PORT
      LAYER M5 ;
        RECT  8.544 21.408 8.568 21.6 ;
    END
  END o[25]
  PIN o[260]
    DIRECTION OUTPUT ;
    USE SIGNAL ;
    PORT
      LAYER M5 ;
        RECT  48.384 21.408 48.408 21.6 ;
    END
  END o[260]
  PIN o[261]
    DIRECTION OUTPUT ;
    USE SIGNAL ;
    PORT
      LAYER M5 ;
        RECT  48.576 21.408 48.6 21.6 ;
    END
  END o[261]
  PIN o[262]
    DIRECTION OUTPUT ;
    USE SIGNAL ;
    PORT
      LAYER M5 ;
        RECT  48.768 21.408 48.792 21.6 ;
    END
  END o[262]
  PIN o[263]
    DIRECTION OUTPUT ;
    USE SIGNAL ;
    PORT
      LAYER M5 ;
        RECT  48.912 21.408 48.936 21.6 ;
    END
  END o[263]
  PIN o[264]
    DIRECTION OUTPUT ;
    USE SIGNAL ;
    PORT
      LAYER M5 ;
        RECT  49.104 21.408 49.128 21.6 ;
    END
  END o[264]
  PIN o[265]
    DIRECTION OUTPUT ;
    USE SIGNAL ;
    PORT
      LAYER M5 ;
        RECT  49.248 21.408 49.272 21.6 ;
    END
  END o[265]
  PIN o[266]
    DIRECTION OUTPUT ;
    USE SIGNAL ;
    PORT
      LAYER M5 ;
        RECT  49.44 21.408 49.464 21.6 ;
    END
  END o[266]
  PIN o[267]
    DIRECTION OUTPUT ;
    USE SIGNAL ;
    PORT
      LAYER M5 ;
        RECT  49.584 21.408 49.608 21.6 ;
    END
  END o[267]
  PIN o[268]
    DIRECTION OUTPUT ;
    USE SIGNAL ;
    PORT
      LAYER M5 ;
        RECT  49.776 21.408 49.8 21.6 ;
    END
  END o[268]
  PIN o[269]
    DIRECTION OUTPUT ;
    USE SIGNAL ;
    PORT
      LAYER M5 ;
        RECT  49.92 21.408 49.944 21.6 ;
    END
  END o[269]
  PIN o[26]
    DIRECTION OUTPUT ;
    USE SIGNAL ;
    PORT
      LAYER M5 ;
        RECT  8.736 21.408 8.76 21.6 ;
    END
  END o[26]
  PIN o[270]
    DIRECTION OUTPUT ;
    USE SIGNAL ;
    PORT
      LAYER M5 ;
        RECT  50.112 21.408 50.136 21.6 ;
    END
  END o[270]
  PIN o[271]
    DIRECTION OUTPUT ;
    USE SIGNAL ;
    PORT
      LAYER M5 ;
        RECT  50.256 21.408 50.28 21.6 ;
    END
  END o[271]
  PIN o[272]
    DIRECTION OUTPUT ;
    USE SIGNAL ;
    PORT
      LAYER M5 ;
        RECT  50.448 21.408 50.472 21.6 ;
    END
  END o[272]
  PIN o[273]
    DIRECTION OUTPUT ;
    USE SIGNAL ;
    PORT
      LAYER M5 ;
        RECT  50.592 21.408 50.616 21.6 ;
    END
  END o[273]
  PIN o[274]
    DIRECTION OUTPUT ;
    USE SIGNAL ;
    PORT
      LAYER M5 ;
        RECT  50.784 21.408 50.808 21.6 ;
    END
  END o[274]
  PIN o[275]
    DIRECTION OUTPUT ;
    USE SIGNAL ;
    PORT
      LAYER M5 ;
        RECT  50.976 21.408 51 21.6 ;
    END
  END o[275]
  PIN o[276]
    DIRECTION OUTPUT ;
    USE SIGNAL ;
    PORT
      LAYER M5 ;
        RECT  51.12 21.408 51.144 21.6 ;
    END
  END o[276]
  PIN o[277]
    DIRECTION OUTPUT ;
    USE SIGNAL ;
    PORT
      LAYER M5 ;
        RECT  51.312 21.408 51.336 21.6 ;
    END
  END o[277]
  PIN o[278]
    DIRECTION OUTPUT ;
    USE SIGNAL ;
    PORT
      LAYER M5 ;
        RECT  51.456 21.408 51.48 21.6 ;
    END
  END o[278]
  PIN o[279]
    DIRECTION OUTPUT ;
    USE SIGNAL ;
    PORT
      LAYER M5 ;
        RECT  51.648 21.408 51.672 21.6 ;
    END
  END o[279]
  PIN o[27]
    DIRECTION OUTPUT ;
    USE SIGNAL ;
    PORT
      LAYER M5 ;
        RECT  8.88 21.408 8.904 21.6 ;
    END
  END o[27]
  PIN o[280]
    DIRECTION OUTPUT ;
    USE SIGNAL ;
    PORT
      LAYER M5 ;
        RECT  51.792 21.408 51.816 21.6 ;
    END
  END o[280]
  PIN o[281]
    DIRECTION OUTPUT ;
    USE SIGNAL ;
    PORT
      LAYER M5 ;
        RECT  51.984 21.408 52.008 21.6 ;
    END
  END o[281]
  PIN o[282]
    DIRECTION OUTPUT ;
    USE SIGNAL ;
    PORT
      LAYER M5 ;
        RECT  52.128 21.408 52.152 21.6 ;
    END
  END o[282]
  PIN o[283]
    DIRECTION OUTPUT ;
    USE SIGNAL ;
    PORT
      LAYER M5 ;
        RECT  52.32 21.408 52.344 21.6 ;
    END
  END o[283]
  PIN o[284]
    DIRECTION OUTPUT ;
    USE SIGNAL ;
    PORT
      LAYER M5 ;
        RECT  52.464 21.408 52.488 21.6 ;
    END
  END o[284]
  PIN o[285]
    DIRECTION OUTPUT ;
    USE SIGNAL ;
    PORT
      LAYER M5 ;
        RECT  52.656 21.408 52.68 21.6 ;
    END
  END o[285]
  PIN o[286]
    DIRECTION OUTPUT ;
    USE SIGNAL ;
    PORT
      LAYER M5 ;
        RECT  52.8 21.408 52.824 21.6 ;
    END
  END o[286]
  PIN o[287]
    DIRECTION OUTPUT ;
    USE SIGNAL ;
    PORT
      LAYER M5 ;
        RECT  52.992 21.408 53.016 21.6 ;
    END
  END o[287]
  PIN o[288]
    DIRECTION OUTPUT ;
    USE SIGNAL ;
    PORT
      LAYER M5 ;
        RECT  53.136 21.408 53.16 21.6 ;
    END
  END o[288]
  PIN o[289]
    DIRECTION OUTPUT ;
    USE SIGNAL ;
    PORT
      LAYER M5 ;
        RECT  53.328 21.408 53.352 21.6 ;
    END
  END o[289]
  PIN o[28]
    DIRECTION OUTPUT ;
    USE SIGNAL ;
    PORT
      LAYER M5 ;
        RECT  9.072 21.408 9.096 21.6 ;
    END
  END o[28]
  PIN o[290]
    DIRECTION OUTPUT ;
    USE SIGNAL ;
    PORT
      LAYER M5 ;
        RECT  53.52 21.408 53.544 21.6 ;
    END
  END o[290]
  PIN o[291]
    DIRECTION OUTPUT ;
    USE SIGNAL ;
    PORT
      LAYER M5 ;
        RECT  53.664 21.408 53.688 21.6 ;
    END
  END o[291]
  PIN o[292]
    DIRECTION OUTPUT ;
    USE SIGNAL ;
    PORT
      LAYER M5 ;
        RECT  53.856 21.408 53.88 21.6 ;
    END
  END o[292]
  PIN o[293]
    DIRECTION OUTPUT ;
    USE SIGNAL ;
    PORT
      LAYER M5 ;
        RECT  54 21.408 54.024 21.6 ;
    END
  END o[293]
  PIN o[294]
    DIRECTION OUTPUT ;
    USE SIGNAL ;
    PORT
      LAYER M5 ;
        RECT  54.192 21.408 54.216 21.6 ;
    END
  END o[294]
  PIN o[295]
    DIRECTION OUTPUT ;
    USE SIGNAL ;
    PORT
      LAYER M5 ;
        RECT  54.336 21.408 54.36 21.6 ;
    END
  END o[295]
  PIN o[296]
    DIRECTION OUTPUT ;
    USE SIGNAL ;
    PORT
      LAYER M5 ;
        RECT  54.528 21.408 54.552 21.6 ;
    END
  END o[296]
  PIN o[297]
    DIRECTION OUTPUT ;
    USE SIGNAL ;
    PORT
      LAYER M5 ;
        RECT  54.672 21.408 54.696 21.6 ;
    END
  END o[297]
  PIN o[298]
    DIRECTION OUTPUT ;
    USE SIGNAL ;
    PORT
      LAYER M5 ;
        RECT  54.864 21.408 54.888 21.6 ;
    END
  END o[298]
  PIN o[299]
    DIRECTION OUTPUT ;
    USE SIGNAL ;
    PORT
      LAYER M5 ;
        RECT  55.008 21.408 55.032 21.6 ;
    END
  END o[299]
  PIN o[29]
    DIRECTION OUTPUT ;
    USE SIGNAL ;
    PORT
      LAYER M5 ;
        RECT  9.216 21.408 9.24 21.6 ;
    END
  END o[29]
  PIN o[2]
    DIRECTION OUTPUT ;
    USE SIGNAL ;
    PORT
      LAYER M5 ;
        RECT  4.656 21.408 4.68 21.6 ;
    END
  END o[2]
  PIN o[300]
    DIRECTION OUTPUT ;
    USE SIGNAL ;
    PORT
      LAYER M5 ;
        RECT  55.2 21.408 55.224 21.6 ;
    END
  END o[300]
  PIN o[301]
    DIRECTION OUTPUT ;
    USE SIGNAL ;
    PORT
      LAYER M5 ;
        RECT  55.344 21.408 55.368 21.6 ;
    END
  END o[301]
  PIN o[302]
    DIRECTION OUTPUT ;
    USE SIGNAL ;
    PORT
      LAYER M5 ;
        RECT  55.536 21.408 55.56 21.6 ;
    END
  END o[302]
  PIN o[303]
    DIRECTION OUTPUT ;
    USE SIGNAL ;
    PORT
      LAYER M5 ;
        RECT  55.68 21.408 55.704 21.6 ;
    END
  END o[303]
  PIN o[304]
    DIRECTION OUTPUT ;
    USE SIGNAL ;
    PORT
      LAYER M5 ;
        RECT  55.872 21.408 55.896 21.6 ;
    END
  END o[304]
  PIN o[305]
    DIRECTION OUTPUT ;
    USE SIGNAL ;
    PORT
      LAYER M5 ;
        RECT  56.064 21.408 56.088 21.6 ;
    END
  END o[305]
  PIN o[306]
    DIRECTION OUTPUT ;
    USE SIGNAL ;
    PORT
      LAYER M5 ;
        RECT  56.208 21.408 56.232 21.6 ;
    END
  END o[306]
  PIN o[307]
    DIRECTION OUTPUT ;
    USE SIGNAL ;
    PORT
      LAYER M5 ;
        RECT  56.4 21.408 56.424 21.6 ;
    END
  END o[307]
  PIN o[308]
    DIRECTION OUTPUT ;
    USE SIGNAL ;
    PORT
      LAYER M5 ;
        RECT  56.544 21.408 56.568 21.6 ;
    END
  END o[308]
  PIN o[309]
    DIRECTION OUTPUT ;
    USE SIGNAL ;
    PORT
      LAYER M5 ;
        RECT  56.736 21.408 56.76 21.6 ;
    END
  END o[309]
  PIN o[30]
    DIRECTION OUTPUT ;
    USE SIGNAL ;
    PORT
      LAYER M5 ;
        RECT  9.408 21.408 9.432 21.6 ;
    END
  END o[30]
  PIN o[310]
    DIRECTION OUTPUT ;
    USE SIGNAL ;
    PORT
      LAYER M5 ;
        RECT  56.88 21.408 56.904 21.6 ;
    END
  END o[310]
  PIN o[311]
    DIRECTION OUTPUT ;
    USE SIGNAL ;
    PORT
      LAYER M5 ;
        RECT  57.072 21.408 57.096 21.6 ;
    END
  END o[311]
  PIN o[312]
    DIRECTION OUTPUT ;
    USE SIGNAL ;
    PORT
      LAYER M5 ;
        RECT  57.408 21.408 57.432 21.6 ;
    END
  END o[312]
  PIN o[313]
    DIRECTION OUTPUT ;
    USE SIGNAL ;
    PORT
      LAYER M5 ;
        RECT  57.552 21.408 57.576 21.6 ;
    END
  END o[313]
  PIN o[314]
    DIRECTION OUTPUT ;
    USE SIGNAL ;
    PORT
      LAYER M5 ;
        RECT  57.744 21.408 57.768 21.6 ;
    END
  END o[314]
  PIN o[315]
    DIRECTION OUTPUT ;
    USE SIGNAL ;
    PORT
      LAYER M5 ;
        RECT  57.888 21.408 57.912 21.6 ;
    END
  END o[315]
  PIN o[316]
    DIRECTION OUTPUT ;
    USE SIGNAL ;
    PORT
      LAYER M5 ;
        RECT  58.08 21.408 58.104 21.6 ;
    END
  END o[316]
  PIN o[317]
    DIRECTION OUTPUT ;
    USE SIGNAL ;
    PORT
      LAYER M5 ;
        RECT  58.224 21.408 58.248 21.6 ;
    END
  END o[317]
  PIN o[318]
    DIRECTION OUTPUT ;
    USE SIGNAL ;
    PORT
      LAYER M5 ;
        RECT  58.416 21.408 58.44 21.6 ;
    END
  END o[318]
  PIN o[319]
    DIRECTION OUTPUT ;
    USE SIGNAL ;
    PORT
      LAYER M5 ;
        RECT  58.608 21.408 58.632 21.6 ;
    END
  END o[319]
  PIN o[31]
    DIRECTION OUTPUT ;
    USE SIGNAL ;
    PORT
      LAYER M5 ;
        RECT  9.552 21.408 9.576 21.6 ;
    END
  END o[31]
  PIN o[320]
    DIRECTION OUTPUT ;
    USE SIGNAL ;
    PORT
      LAYER M5 ;
        RECT  58.752 21.408 58.776 21.6 ;
    END
  END o[320]
  PIN o[321]
    DIRECTION OUTPUT ;
    USE SIGNAL ;
    PORT
      LAYER M5 ;
        RECT  58.944 21.408 58.968 21.6 ;
    END
  END o[321]
  PIN o[322]
    DIRECTION OUTPUT ;
    USE SIGNAL ;
    PORT
      LAYER M5 ;
        RECT  59.088 21.408 59.112 21.6 ;
    END
  END o[322]
  PIN o[323]
    DIRECTION OUTPUT ;
    USE SIGNAL ;
    PORT
      LAYER M5 ;
        RECT  59.28 21.408 59.304 21.6 ;
    END
  END o[323]
  PIN o[324]
    DIRECTION OUTPUT ;
    USE SIGNAL ;
    PORT
      LAYER M5 ;
        RECT  59.424 21.408 59.448 21.6 ;
    END
  END o[324]
  PIN o[325]
    DIRECTION OUTPUT ;
    USE SIGNAL ;
    PORT
      LAYER M5 ;
        RECT  59.616 21.408 59.64 21.6 ;
    END
  END o[325]
  PIN o[326]
    DIRECTION OUTPUT ;
    USE SIGNAL ;
    PORT
      LAYER M5 ;
        RECT  59.76 21.408 59.784 21.6 ;
    END
  END o[326]
  PIN o[327]
    DIRECTION OUTPUT ;
    USE SIGNAL ;
    PORT
      LAYER M5 ;
        RECT  59.952 21.408 59.976 21.6 ;
    END
  END o[327]
  PIN o[328]
    DIRECTION OUTPUT ;
    USE SIGNAL ;
    PORT
      LAYER M5 ;
        RECT  60.096 21.408 60.12 21.6 ;
    END
  END o[328]
  PIN o[329]
    DIRECTION OUTPUT ;
    USE SIGNAL ;
    PORT
      LAYER M5 ;
        RECT  60.288 21.408 60.312 21.6 ;
    END
  END o[329]
  PIN o[32]
    DIRECTION OUTPUT ;
    USE SIGNAL ;
    PORT
      LAYER M5 ;
        RECT  9.744 21.408 9.768 21.6 ;
    END
  END o[32]
  PIN o[330]
    DIRECTION OUTPUT ;
    USE SIGNAL ;
    PORT
      LAYER M5 ;
        RECT  60.432 21.408 60.456 21.6 ;
    END
  END o[330]
  PIN o[331]
    DIRECTION OUTPUT ;
    USE SIGNAL ;
    PORT
      LAYER M5 ;
        RECT  60.624 21.408 60.648 21.6 ;
    END
  END o[331]
  PIN o[332]
    DIRECTION OUTPUT ;
    USE SIGNAL ;
    PORT
      LAYER M5 ;
        RECT  60.768 21.408 60.792 21.6 ;
    END
  END o[332]
  PIN o[333]
    DIRECTION OUTPUT ;
    USE SIGNAL ;
    PORT
      LAYER M5 ;
        RECT  60.96 21.408 60.984 21.6 ;
    END
  END o[333]
  PIN o[334]
    DIRECTION OUTPUT ;
    USE SIGNAL ;
    PORT
      LAYER M5 ;
        RECT  61.152 21.408 61.176 21.6 ;
    END
  END o[334]
  PIN o[335]
    DIRECTION OUTPUT ;
    USE SIGNAL ;
    PORT
      LAYER M5 ;
        RECT  61.296 21.408 61.32 21.6 ;
    END
  END o[335]
  PIN o[336]
    DIRECTION OUTPUT ;
    USE SIGNAL ;
    PORT
      LAYER M5 ;
        RECT  61.488 21.408 61.512 21.6 ;
    END
  END o[336]
  PIN o[337]
    DIRECTION OUTPUT ;
    USE SIGNAL ;
    PORT
      LAYER M5 ;
        RECT  61.632 21.408 61.656 21.6 ;
    END
  END o[337]
  PIN o[338]
    DIRECTION OUTPUT ;
    USE SIGNAL ;
    PORT
      LAYER M5 ;
        RECT  61.824 21.408 61.848 21.6 ;
    END
  END o[338]
  PIN o[339]
    DIRECTION OUTPUT ;
    USE SIGNAL ;
    PORT
      LAYER M5 ;
        RECT  61.968 21.408 61.992 21.6 ;
    END
  END o[339]
  PIN o[33]
    DIRECTION OUTPUT ;
    USE SIGNAL ;
    PORT
      LAYER M5 ;
        RECT  9.888 21.408 9.912 21.6 ;
    END
  END o[33]
  PIN o[340]
    DIRECTION OUTPUT ;
    USE SIGNAL ;
    PORT
      LAYER M5 ;
        RECT  62.16 21.408 62.184 21.6 ;
    END
  END o[340]
  PIN o[341]
    DIRECTION OUTPUT ;
    USE SIGNAL ;
    PORT
      LAYER M5 ;
        RECT  62.304 21.408 62.328 21.6 ;
    END
  END o[341]
  PIN o[342]
    DIRECTION OUTPUT ;
    USE SIGNAL ;
    PORT
      LAYER M5 ;
        RECT  62.496 21.408 62.52 21.6 ;
    END
  END o[342]
  PIN o[343]
    DIRECTION OUTPUT ;
    USE SIGNAL ;
    PORT
      LAYER M5 ;
        RECT  62.64 21.408 62.664 21.6 ;
    END
  END o[343]
  PIN o[344]
    DIRECTION OUTPUT ;
    USE SIGNAL ;
    PORT
      LAYER M5 ;
        RECT  62.832 21.408 62.856 21.6 ;
    END
  END o[344]
  PIN o[345]
    DIRECTION OUTPUT ;
    USE SIGNAL ;
    PORT
      LAYER M5 ;
        RECT  62.976 21.408 63 21.6 ;
    END
  END o[345]
  PIN o[346]
    DIRECTION OUTPUT ;
    USE SIGNAL ;
    PORT
      LAYER M5 ;
        RECT  63.168 21.408 63.192 21.6 ;
    END
  END o[346]
  PIN o[347]
    DIRECTION OUTPUT ;
    USE SIGNAL ;
    PORT
      LAYER M5 ;
        RECT  63.312 21.408 63.336 21.6 ;
    END
  END o[347]
  PIN o[348]
    DIRECTION OUTPUT ;
    USE SIGNAL ;
    PORT
      LAYER M5 ;
        RECT  63.504 21.408 63.528 21.6 ;
    END
  END o[348]
  PIN o[349]
    DIRECTION OUTPUT ;
    USE SIGNAL ;
    PORT
      LAYER M5 ;
        RECT  63.696 21.408 63.72 21.6 ;
    END
  END o[349]
  PIN o[34]
    DIRECTION OUTPUT ;
    USE SIGNAL ;
    PORT
      LAYER M5 ;
        RECT  10.08 21.408 10.104 21.6 ;
    END
  END o[34]
  PIN o[350]
    DIRECTION OUTPUT ;
    USE SIGNAL ;
    PORT
      LAYER M5 ;
        RECT  63.84 21.408 63.864 21.6 ;
    END
  END o[350]
  PIN o[351]
    DIRECTION OUTPUT ;
    USE SIGNAL ;
    PORT
      LAYER M5 ;
        RECT  64.032 21.408 64.056 21.6 ;
    END
  END o[351]
  PIN o[352]
    DIRECTION OUTPUT ;
    USE SIGNAL ;
    PORT
      LAYER M5 ;
        RECT  64.176 21.408 64.2 21.6 ;
    END
  END o[352]
  PIN o[353]
    DIRECTION OUTPUT ;
    USE SIGNAL ;
    PORT
      LAYER M5 ;
        RECT  64.368 21.408 64.392 21.6 ;
    END
  END o[353]
  PIN o[354]
    DIRECTION OUTPUT ;
    USE SIGNAL ;
    PORT
      LAYER M5 ;
        RECT  64.512 21.408 64.536 21.6 ;
    END
  END o[354]
  PIN o[355]
    DIRECTION OUTPUT ;
    USE SIGNAL ;
    PORT
      LAYER M5 ;
        RECT  64.704 21.408 64.728 21.6 ;
    END
  END o[355]
  PIN o[356]
    DIRECTION OUTPUT ;
    USE SIGNAL ;
    PORT
      LAYER M5 ;
        RECT  64.848 21.408 64.872 21.6 ;
    END
  END o[356]
  PIN o[357]
    DIRECTION OUTPUT ;
    USE SIGNAL ;
    PORT
      LAYER M5 ;
        RECT  65.04 21.408 65.064 21.6 ;
    END
  END o[357]
  PIN o[358]
    DIRECTION OUTPUT ;
    USE SIGNAL ;
    PORT
      LAYER M5 ;
        RECT  65.184 21.408 65.208 21.6 ;
    END
  END o[358]
  PIN o[359]
    DIRECTION OUTPUT ;
    USE SIGNAL ;
    PORT
      LAYER M5 ;
        RECT  65.376 21.408 65.4 21.6 ;
    END
  END o[359]
  PIN o[35]
    DIRECTION OUTPUT ;
    USE SIGNAL ;
    PORT
      LAYER M5 ;
        RECT  10.224 21.408 10.248 21.6 ;
    END
  END o[35]
  PIN o[360]
    DIRECTION OUTPUT ;
    USE SIGNAL ;
    PORT
      LAYER M5 ;
        RECT  65.52 21.408 65.544 21.6 ;
    END
  END o[360]
  PIN o[361]
    DIRECTION OUTPUT ;
    USE SIGNAL ;
    PORT
      LAYER M5 ;
        RECT  65.712 21.408 65.736 21.6 ;
    END
  END o[361]
  PIN o[362]
    DIRECTION OUTPUT ;
    USE SIGNAL ;
    PORT
      LAYER M5 ;
        RECT  65.856 21.408 65.88 21.6 ;
    END
  END o[362]
  PIN o[363]
    DIRECTION OUTPUT ;
    USE SIGNAL ;
    PORT
      LAYER M5 ;
        RECT  66.048 21.408 66.072 21.6 ;
    END
  END o[363]
  PIN o[364]
    DIRECTION OUTPUT ;
    USE SIGNAL ;
    PORT
      LAYER M5 ;
        RECT  66.24 21.408 66.264 21.6 ;
    END
  END o[364]
  PIN o[365]
    DIRECTION OUTPUT ;
    USE SIGNAL ;
    PORT
      LAYER M5 ;
        RECT  66.384 21.408 66.408 21.6 ;
    END
  END o[365]
  PIN o[366]
    DIRECTION OUTPUT ;
    USE SIGNAL ;
    PORT
      LAYER M5 ;
        RECT  66.576 21.408 66.6 21.6 ;
    END
  END o[366]
  PIN o[367]
    DIRECTION OUTPUT ;
    USE SIGNAL ;
    PORT
      LAYER M5 ;
        RECT  66.72 21.408 66.744 21.6 ;
    END
  END o[367]
  PIN o[368]
    DIRECTION OUTPUT ;
    USE SIGNAL ;
    PORT
      LAYER M5 ;
        RECT  66.912 21.408 66.936 21.6 ;
    END
  END o[368]
  PIN o[369]
    DIRECTION OUTPUT ;
    USE SIGNAL ;
    PORT
      LAYER M5 ;
        RECT  67.056 21.408 67.08 21.6 ;
    END
  END o[369]
  PIN o[36]
    DIRECTION OUTPUT ;
    USE SIGNAL ;
    PORT
      LAYER M5 ;
        RECT  10.416 21.408 10.44 21.6 ;
    END
  END o[36]
  PIN o[370]
    DIRECTION OUTPUT ;
    USE SIGNAL ;
    PORT
      LAYER M5 ;
        RECT  67.248 21.408 67.272 21.6 ;
    END
  END o[370]
  PIN o[371]
    DIRECTION OUTPUT ;
    USE SIGNAL ;
    PORT
      LAYER M5 ;
        RECT  67.392 21.408 67.416 21.6 ;
    END
  END o[371]
  PIN o[372]
    DIRECTION OUTPUT ;
    USE SIGNAL ;
    PORT
      LAYER M5 ;
        RECT  67.584 21.408 67.608 21.6 ;
    END
  END o[372]
  PIN o[373]
    DIRECTION OUTPUT ;
    USE SIGNAL ;
    PORT
      LAYER M5 ;
        RECT  67.728 21.408 67.752 21.6 ;
    END
  END o[373]
  PIN o[374]
    DIRECTION OUTPUT ;
    USE SIGNAL ;
    PORT
      LAYER M5 ;
        RECT  67.92 21.408 67.944 21.6 ;
    END
  END o[374]
  PIN o[375]
    DIRECTION OUTPUT ;
    USE SIGNAL ;
    PORT
      LAYER M5 ;
        RECT  68.064 21.408 68.088 21.6 ;
    END
  END o[375]
  PIN o[376]
    DIRECTION OUTPUT ;
    USE SIGNAL ;
    PORT
      LAYER M5 ;
        RECT  68.256 21.408 68.28 21.6 ;
    END
  END o[376]
  PIN o[377]
    DIRECTION OUTPUT ;
    USE SIGNAL ;
    PORT
      LAYER M5 ;
        RECT  68.4 21.408 68.424 21.6 ;
    END
  END o[377]
  PIN o[378]
    DIRECTION OUTPUT ;
    USE SIGNAL ;
    PORT
      LAYER M5 ;
        RECT  68.592 21.408 68.616 21.6 ;
    END
  END o[378]
  PIN o[379]
    DIRECTION OUTPUT ;
    USE SIGNAL ;
    PORT
      LAYER M5 ;
        RECT  68.784 21.408 68.808 21.6 ;
    END
  END o[379]
  PIN o[37]
    DIRECTION OUTPUT ;
    USE SIGNAL ;
    PORT
      LAYER M5 ;
        RECT  10.56 21.408 10.584 21.6 ;
    END
  END o[37]
  PIN o[380]
    DIRECTION OUTPUT ;
    USE SIGNAL ;
    PORT
      LAYER M5 ;
        RECT  68.928 21.408 68.952 21.6 ;
    END
  END o[380]
  PIN o[381]
    DIRECTION OUTPUT ;
    USE SIGNAL ;
    PORT
      LAYER M5 ;
        RECT  69.12 21.408 69.144 21.6 ;
    END
  END o[381]
  PIN o[382]
    DIRECTION OUTPUT ;
    USE SIGNAL ;
    PORT
      LAYER M5 ;
        RECT  69.264 21.408 69.288 21.6 ;
    END
  END o[382]
  PIN o[383]
    DIRECTION OUTPUT ;
    USE SIGNAL ;
    PORT
      LAYER M5 ;
        RECT  69.456 21.408 69.48 21.6 ;
    END
  END o[383]
  PIN o[384]
    DIRECTION OUTPUT ;
    USE SIGNAL ;
    PORT
      LAYER M5 ;
        RECT  69.6 21.408 69.624 21.6 ;
    END
  END o[384]
  PIN o[385]
    DIRECTION OUTPUT ;
    USE SIGNAL ;
    PORT
      LAYER M5 ;
        RECT  69.792 21.408 69.816 21.6 ;
    END
  END o[385]
  PIN o[386]
    DIRECTION OUTPUT ;
    USE SIGNAL ;
    PORT
      LAYER M5 ;
        RECT  69.936 21.408 69.96 21.6 ;
    END
  END o[386]
  PIN o[387]
    DIRECTION OUTPUT ;
    USE SIGNAL ;
    PORT
      LAYER M5 ;
        RECT  70.128 21.408 70.152 21.6 ;
    END
  END o[387]
  PIN o[388]
    DIRECTION OUTPUT ;
    USE SIGNAL ;
    PORT
      LAYER M5 ;
        RECT  70.272 21.408 70.296 21.6 ;
    END
  END o[388]
  PIN o[389]
    DIRECTION OUTPUT ;
    USE SIGNAL ;
    PORT
      LAYER M5 ;
        RECT  70.464 21.408 70.488 21.6 ;
    END
  END o[389]
  PIN o[38]
    DIRECTION OUTPUT ;
    USE SIGNAL ;
    PORT
      LAYER M5 ;
        RECT  10.752 21.408 10.776 21.6 ;
    END
  END o[38]
  PIN o[390]
    DIRECTION OUTPUT ;
    USE SIGNAL ;
    PORT
      LAYER M5 ;
        RECT  70.608 21.408 70.632 21.6 ;
    END
  END o[390]
  PIN o[391]
    DIRECTION OUTPUT ;
    USE SIGNAL ;
    PORT
      LAYER M5 ;
        RECT  70.8 21.408 70.824 21.6 ;
    END
  END o[391]
  PIN o[392]
    DIRECTION OUTPUT ;
    USE SIGNAL ;
    PORT
      LAYER M5 ;
        RECT  70.944 21.408 70.968 21.6 ;
    END
  END o[392]
  PIN o[393]
    DIRECTION OUTPUT ;
    USE SIGNAL ;
    PORT
      LAYER M5 ;
        RECT  71.136 21.408 71.16 21.6 ;
    END
  END o[393]
  PIN o[394]
    DIRECTION OUTPUT ;
    USE SIGNAL ;
    PORT
      LAYER M5 ;
        RECT  71.328 21.408 71.352 21.6 ;
    END
  END o[394]
  PIN o[395]
    DIRECTION OUTPUT ;
    USE SIGNAL ;
    PORT
      LAYER M5 ;
        RECT  71.472 21.408 71.496 21.6 ;
    END
  END o[395]
  PIN o[396]
    DIRECTION OUTPUT ;
    USE SIGNAL ;
    PORT
      LAYER M5 ;
        RECT  71.664 21.408 71.688 21.6 ;
    END
  END o[396]
  PIN o[397]
    DIRECTION OUTPUT ;
    USE SIGNAL ;
    PORT
      LAYER M5 ;
        RECT  71.808 21.408 71.832 21.6 ;
    END
  END o[397]
  PIN o[398]
    DIRECTION OUTPUT ;
    USE SIGNAL ;
    PORT
      LAYER M5 ;
        RECT  72 21.408 72.024 21.6 ;
    END
  END o[398]
  PIN o[399]
    DIRECTION OUTPUT ;
    USE SIGNAL ;
    PORT
      LAYER M5 ;
        RECT  72.144 21.408 72.168 21.6 ;
    END
  END o[399]
  PIN o[39]
    DIRECTION OUTPUT ;
    USE SIGNAL ;
    PORT
      LAYER M5 ;
        RECT  10.944 21.408 10.968 21.6 ;
    END
  END o[39]
  PIN o[3]
    DIRECTION OUTPUT ;
    USE SIGNAL ;
    PORT
      LAYER M5 ;
        RECT  4.8 21.408 4.824 21.6 ;
    END
  END o[3]
  PIN o[400]
    DIRECTION OUTPUT ;
    USE SIGNAL ;
    PORT
      LAYER M5 ;
        RECT  72.336 21.408 72.36 21.6 ;
    END
  END o[400]
  PIN o[401]
    DIRECTION OUTPUT ;
    USE SIGNAL ;
    PORT
      LAYER M5 ;
        RECT  72.48 21.408 72.504 21.6 ;
    END
  END o[401]
  PIN o[402]
    DIRECTION OUTPUT ;
    USE SIGNAL ;
    PORT
      LAYER M5 ;
        RECT  72.672 21.408 72.696 21.6 ;
    END
  END o[402]
  PIN o[403]
    DIRECTION OUTPUT ;
    USE SIGNAL ;
    PORT
      LAYER M5 ;
        RECT  72.816 21.408 72.84 21.6 ;
    END
  END o[403]
  PIN o[404]
    DIRECTION OUTPUT ;
    USE SIGNAL ;
    PORT
      LAYER M5 ;
        RECT  73.008 21.408 73.032 21.6 ;
    END
  END o[404]
  PIN o[405]
    DIRECTION OUTPUT ;
    USE SIGNAL ;
    PORT
      LAYER M5 ;
        RECT  73.152 21.408 73.176 21.6 ;
    END
  END o[405]
  PIN o[406]
    DIRECTION OUTPUT ;
    USE SIGNAL ;
    PORT
      LAYER M5 ;
        RECT  73.344 21.408 73.368 21.6 ;
    END
  END o[406]
  PIN o[407]
    DIRECTION OUTPUT ;
    USE SIGNAL ;
    PORT
      LAYER M5 ;
        RECT  73.488 21.408 73.512 21.6 ;
    END
  END o[407]
  PIN o[408]
    DIRECTION OUTPUT ;
    USE SIGNAL ;
    PORT
      LAYER M5 ;
        RECT  73.68 21.408 73.704 21.6 ;
    END
  END o[408]
  PIN o[409]
    DIRECTION OUTPUT ;
    USE SIGNAL ;
    PORT
      LAYER M5 ;
        RECT  73.872 21.408 73.896 21.6 ;
    END
  END o[409]
  PIN o[40]
    DIRECTION OUTPUT ;
    USE SIGNAL ;
    PORT
      LAYER M5 ;
        RECT  11.088 21.408 11.112 21.6 ;
    END
  END o[40]
  PIN o[410]
    DIRECTION OUTPUT ;
    USE SIGNAL ;
    PORT
      LAYER M5 ;
        RECT  74.016 21.408 74.04 21.6 ;
    END
  END o[410]
  PIN o[411]
    DIRECTION OUTPUT ;
    USE SIGNAL ;
    PORT
      LAYER M5 ;
        RECT  74.208 21.408 74.232 21.6 ;
    END
  END o[411]
  PIN o[412]
    DIRECTION OUTPUT ;
    USE SIGNAL ;
    PORT
      LAYER M5 ;
        RECT  74.352 21.408 74.376 21.6 ;
    END
  END o[412]
  PIN o[413]
    DIRECTION OUTPUT ;
    USE SIGNAL ;
    PORT
      LAYER M5 ;
        RECT  74.544 21.408 74.568 21.6 ;
    END
  END o[413]
  PIN o[414]
    DIRECTION OUTPUT ;
    USE SIGNAL ;
    PORT
      LAYER M5 ;
        RECT  74.688 21.408 74.712 21.6 ;
    END
  END o[414]
  PIN o[415]
    DIRECTION OUTPUT ;
    USE SIGNAL ;
    PORT
      LAYER M5 ;
        RECT  74.88 21.408 74.904 21.6 ;
    END
  END o[415]
  PIN o[416]
    DIRECTION OUTPUT ;
    USE SIGNAL ;
    PORT
      LAYER M5 ;
        RECT  75.024 21.408 75.048 21.6 ;
    END
  END o[416]
  PIN o[417]
    DIRECTION OUTPUT ;
    USE SIGNAL ;
    PORT
      LAYER M5 ;
        RECT  75.216 21.408 75.24 21.6 ;
    END
  END o[417]
  PIN o[418]
    DIRECTION OUTPUT ;
    USE SIGNAL ;
    PORT
      LAYER M5 ;
        RECT  75.36 21.408 75.384 21.6 ;
    END
  END o[418]
  PIN o[419]
    DIRECTION OUTPUT ;
    USE SIGNAL ;
    PORT
      LAYER M5 ;
        RECT  75.552 21.408 75.576 21.6 ;
    END
  END o[419]
  PIN o[41]
    DIRECTION OUTPUT ;
    USE SIGNAL ;
    PORT
      LAYER M5 ;
        RECT  11.28 21.408 11.304 21.6 ;
    END
  END o[41]
  PIN o[420]
    DIRECTION OUTPUT ;
    USE SIGNAL ;
    PORT
      LAYER M5 ;
        RECT  75.696 21.408 75.72 21.6 ;
    END
  END o[420]
  PIN o[421]
    DIRECTION OUTPUT ;
    USE SIGNAL ;
    PORT
      LAYER M5 ;
        RECT  75.888 21.408 75.912 21.6 ;
    END
  END o[421]
  PIN o[422]
    DIRECTION OUTPUT ;
    USE SIGNAL ;
    PORT
      LAYER M5 ;
        RECT  76.032 21.408 76.056 21.6 ;
    END
  END o[422]
  PIN o[423]
    DIRECTION OUTPUT ;
    USE SIGNAL ;
    PORT
      LAYER M5 ;
        RECT  76.224 21.408 76.248 21.6 ;
    END
  END o[423]
  PIN o[424]
    DIRECTION OUTPUT ;
    USE SIGNAL ;
    PORT
      LAYER M5 ;
        RECT  76.416 21.408 76.44 21.6 ;
    END
  END o[424]
  PIN o[425]
    DIRECTION OUTPUT ;
    USE SIGNAL ;
    PORT
      LAYER M5 ;
        RECT  76.56 21.408 76.584 21.6 ;
    END
  END o[425]
  PIN o[426]
    DIRECTION OUTPUT ;
    USE SIGNAL ;
    PORT
      LAYER M5 ;
        RECT  76.752 21.408 76.776 21.6 ;
    END
  END o[426]
  PIN o[427]
    DIRECTION OUTPUT ;
    USE SIGNAL ;
    PORT
      LAYER M5 ;
        RECT  76.896 21.408 76.92 21.6 ;
    END
  END o[427]
  PIN o[428]
    DIRECTION OUTPUT ;
    USE SIGNAL ;
    PORT
      LAYER M5 ;
        RECT  77.088 21.408 77.112 21.6 ;
    END
  END o[428]
  PIN o[429]
    DIRECTION OUTPUT ;
    USE SIGNAL ;
    PORT
      LAYER M5 ;
        RECT  77.232 21.408 77.256 21.6 ;
    END
  END o[429]
  PIN o[42]
    DIRECTION OUTPUT ;
    USE SIGNAL ;
    PORT
      LAYER M5 ;
        RECT  11.424 21.408 11.448 21.6 ;
    END
  END o[42]
  PIN o[430]
    DIRECTION OUTPUT ;
    USE SIGNAL ;
    PORT
      LAYER M5 ;
        RECT  77.424 21.408 77.448 21.6 ;
    END
  END o[430]
  PIN o[431]
    DIRECTION OUTPUT ;
    USE SIGNAL ;
    PORT
      LAYER M5 ;
        RECT  77.568 21.408 77.592 21.6 ;
    END
  END o[431]
  PIN o[432]
    DIRECTION OUTPUT ;
    USE SIGNAL ;
    PORT
      LAYER M5 ;
        RECT  77.76 21.408 77.784 21.6 ;
    END
  END o[432]
  PIN o[433]
    DIRECTION OUTPUT ;
    USE SIGNAL ;
    PORT
      LAYER M5 ;
        RECT  77.904 21.408 77.928 21.6 ;
    END
  END o[433]
  PIN o[434]
    DIRECTION OUTPUT ;
    USE SIGNAL ;
    PORT
      LAYER M5 ;
        RECT  78.096 21.408 78.12 21.6 ;
    END
  END o[434]
  PIN o[435]
    DIRECTION OUTPUT ;
    USE SIGNAL ;
    PORT
      LAYER M5 ;
        RECT  78.24 21.408 78.264 21.6 ;
    END
  END o[435]
  PIN o[436]
    DIRECTION OUTPUT ;
    USE SIGNAL ;
    PORT
      LAYER M5 ;
        RECT  78.432 21.408 78.456 21.6 ;
    END
  END o[436]
  PIN o[437]
    DIRECTION OUTPUT ;
    USE SIGNAL ;
    PORT
      LAYER M5 ;
        RECT  78.576 21.408 78.6 21.6 ;
    END
  END o[437]
  PIN o[438]
    DIRECTION OUTPUT ;
    USE SIGNAL ;
    PORT
      LAYER M5 ;
        RECT  78.768 21.408 78.792 21.6 ;
    END
  END o[438]
  PIN o[439]
    DIRECTION OUTPUT ;
    USE SIGNAL ;
    PORT
      LAYER M5 ;
        RECT  78.96 21.408 78.984 21.6 ;
    END
  END o[439]
  PIN o[43]
    DIRECTION OUTPUT ;
    USE SIGNAL ;
    PORT
      LAYER M5 ;
        RECT  11.616 21.408 11.64 21.6 ;
    END
  END o[43]
  PIN o[440]
    DIRECTION OUTPUT ;
    USE SIGNAL ;
    PORT
      LAYER M5 ;
        RECT  79.104 21.408 79.128 21.6 ;
    END
  END o[440]
  PIN o[441]
    DIRECTION OUTPUT ;
    USE SIGNAL ;
    PORT
      LAYER M5 ;
        RECT  79.296 21.408 79.32 21.6 ;
    END
  END o[441]
  PIN o[442]
    DIRECTION OUTPUT ;
    USE SIGNAL ;
    PORT
      LAYER M5 ;
        RECT  79.44 21.408 79.464 21.6 ;
    END
  END o[442]
  PIN o[443]
    DIRECTION OUTPUT ;
    USE SIGNAL ;
    PORT
      LAYER M5 ;
        RECT  79.632 21.408 79.656 21.6 ;
    END
  END o[443]
  PIN o[444]
    DIRECTION OUTPUT ;
    USE SIGNAL ;
    PORT
      LAYER M5 ;
        RECT  79.776 21.408 79.8 21.6 ;
    END
  END o[444]
  PIN o[445]
    DIRECTION OUTPUT ;
    USE SIGNAL ;
    PORT
      LAYER M5 ;
        RECT  79.968 21.408 79.992 21.6 ;
    END
  END o[445]
  PIN o[446]
    DIRECTION OUTPUT ;
    USE SIGNAL ;
    PORT
      LAYER M5 ;
        RECT  80.112 21.408 80.136 21.6 ;
    END
  END o[446]
  PIN o[447]
    DIRECTION OUTPUT ;
    USE SIGNAL ;
    PORT
      LAYER M5 ;
        RECT  80.304 21.408 80.328 21.6 ;
    END
  END o[447]
  PIN o[448]
    DIRECTION OUTPUT ;
    USE SIGNAL ;
    PORT
      LAYER M5 ;
        RECT  80.448 21.408 80.472 21.6 ;
    END
  END o[448]
  PIN o[449]
    DIRECTION OUTPUT ;
    USE SIGNAL ;
    PORT
      LAYER M5 ;
        RECT  80.64 21.408 80.664 21.6 ;
    END
  END o[449]
  PIN o[44]
    DIRECTION OUTPUT ;
    USE SIGNAL ;
    PORT
      LAYER M5 ;
        RECT  11.76 21.408 11.784 21.6 ;
    END
  END o[44]
  PIN o[450]
    DIRECTION OUTPUT ;
    USE SIGNAL ;
    PORT
      LAYER M5 ;
        RECT  80.784 21.408 80.808 21.6 ;
    END
  END o[450]
  PIN o[451]
    DIRECTION OUTPUT ;
    USE SIGNAL ;
    PORT
      LAYER M5 ;
        RECT  80.976 21.408 81 21.6 ;
    END
  END o[451]
  PIN o[452]
    DIRECTION OUTPUT ;
    USE SIGNAL ;
    PORT
      LAYER M5 ;
        RECT  81.12 21.408 81.144 21.6 ;
    END
  END o[452]
  PIN o[453]
    DIRECTION OUTPUT ;
    USE SIGNAL ;
    PORT
      LAYER M5 ;
        RECT  81.312 21.408 81.336 21.6 ;
    END
  END o[453]
  PIN o[454]
    DIRECTION OUTPUT ;
    USE SIGNAL ;
    PORT
      LAYER M5 ;
        RECT  81.504 21.408 81.528 21.6 ;
    END
  END o[454]
  PIN o[455]
    DIRECTION OUTPUT ;
    USE SIGNAL ;
    PORT
      LAYER M5 ;
        RECT  81.648 21.408 81.672 21.6 ;
    END
  END o[455]
  PIN o[456]
    DIRECTION OUTPUT ;
    USE SIGNAL ;
    PORT
      LAYER M5 ;
        RECT  81.84 21.408 81.864 21.6 ;
    END
  END o[456]
  PIN o[457]
    DIRECTION OUTPUT ;
    USE SIGNAL ;
    PORT
      LAYER M5 ;
        RECT  81.984 21.408 82.008 21.6 ;
    END
  END o[457]
  PIN o[458]
    DIRECTION OUTPUT ;
    USE SIGNAL ;
    PORT
      LAYER M5 ;
        RECT  82.176 21.408 82.2 21.6 ;
    END
  END o[458]
  PIN o[459]
    DIRECTION OUTPUT ;
    USE SIGNAL ;
    PORT
      LAYER M5 ;
        RECT  82.32 21.408 82.344 21.6 ;
    END
  END o[459]
  PIN o[45]
    DIRECTION OUTPUT ;
    USE SIGNAL ;
    PORT
      LAYER M5 ;
        RECT  11.952 21.408 11.976 21.6 ;
    END
  END o[45]
  PIN o[460]
    DIRECTION OUTPUT ;
    USE SIGNAL ;
    PORT
      LAYER M5 ;
        RECT  82.512 21.408 82.536 21.6 ;
    END
  END o[460]
  PIN o[461]
    DIRECTION OUTPUT ;
    USE SIGNAL ;
    PORT
      LAYER M5 ;
        RECT  82.656 21.408 82.68 21.6 ;
    END
  END o[461]
  PIN o[462]
    DIRECTION OUTPUT ;
    USE SIGNAL ;
    PORT
      LAYER M5 ;
        RECT  82.848 21.408 82.872 21.6 ;
    END
  END o[462]
  PIN o[463]
    DIRECTION OUTPUT ;
    USE SIGNAL ;
    PORT
      LAYER M5 ;
        RECT  82.992 21.408 83.016 21.6 ;
    END
  END o[463]
  PIN o[464]
    DIRECTION OUTPUT ;
    USE SIGNAL ;
    PORT
      LAYER M5 ;
        RECT  83.184 21.408 83.208 21.6 ;
    END
  END o[464]
  PIN o[465]
    DIRECTION OUTPUT ;
    USE SIGNAL ;
    PORT
      LAYER M5 ;
        RECT  83.328 21.408 83.352 21.6 ;
    END
  END o[465]
  PIN o[466]
    DIRECTION OUTPUT ;
    USE SIGNAL ;
    PORT
      LAYER M5 ;
        RECT  83.52 21.408 83.544 21.6 ;
    END
  END o[466]
  PIN o[467]
    DIRECTION OUTPUT ;
    USE SIGNAL ;
    PORT
      LAYER M5 ;
        RECT  83.664 21.408 83.688 21.6 ;
    END
  END o[467]
  PIN o[468]
    DIRECTION OUTPUT ;
    USE SIGNAL ;
    PORT
      LAYER M5 ;
        RECT  83.856 21.408 83.88 21.6 ;
    END
  END o[468]
  PIN o[469]
    DIRECTION OUTPUT ;
    USE SIGNAL ;
    PORT
      LAYER M5 ;
        RECT  84.048 21.408 84.072 21.6 ;
    END
  END o[469]
  PIN o[46]
    DIRECTION OUTPUT ;
    USE SIGNAL ;
    PORT
      LAYER M5 ;
        RECT  12.096 21.408 12.12 21.6 ;
    END
  END o[46]
  PIN o[470]
    DIRECTION OUTPUT ;
    USE SIGNAL ;
    PORT
      LAYER M5 ;
        RECT  84.192 21.408 84.216 21.6 ;
    END
  END o[470]
  PIN o[471]
    DIRECTION OUTPUT ;
    USE SIGNAL ;
    PORT
      LAYER M5 ;
        RECT  84.384 21.408 84.408 21.6 ;
    END
  END o[471]
  PIN o[472]
    DIRECTION OUTPUT ;
    USE SIGNAL ;
    PORT
      LAYER M5 ;
        RECT  84.528 21.408 84.552 21.6 ;
    END
  END o[472]
  PIN o[473]
    DIRECTION OUTPUT ;
    USE SIGNAL ;
    PORT
      LAYER M5 ;
        RECT  84.72 21.408 84.744 21.6 ;
    END
  END o[473]
  PIN o[474]
    DIRECTION OUTPUT ;
    USE SIGNAL ;
    PORT
      LAYER M5 ;
        RECT  84.864 21.408 84.888 21.6 ;
    END
  END o[474]
  PIN o[475]
    DIRECTION OUTPUT ;
    USE SIGNAL ;
    PORT
      LAYER M5 ;
        RECT  85.056 21.408 85.08 21.6 ;
    END
  END o[475]
  PIN o[476]
    DIRECTION OUTPUT ;
    USE SIGNAL ;
    PORT
      LAYER M5 ;
        RECT  85.2 21.408 85.224 21.6 ;
    END
  END o[476]
  PIN o[477]
    DIRECTION OUTPUT ;
    USE SIGNAL ;
    PORT
      LAYER M5 ;
        RECT  85.392 21.408 85.416 21.6 ;
    END
  END o[477]
  PIN o[478]
    DIRECTION OUTPUT ;
    USE SIGNAL ;
    PORT
      LAYER M5 ;
        RECT  85.536 21.408 85.56 21.6 ;
    END
  END o[478]
  PIN o[479]
    DIRECTION OUTPUT ;
    USE SIGNAL ;
    PORT
      LAYER M5 ;
        RECT  85.728 21.408 85.752 21.6 ;
    END
  END o[479]
  PIN o[47]
    DIRECTION OUTPUT ;
    USE SIGNAL ;
    PORT
      LAYER M5 ;
        RECT  12.288 21.408 12.312 21.6 ;
    END
  END o[47]
  PIN o[480]
    DIRECTION OUTPUT ;
    USE SIGNAL ;
    PORT
      LAYER M5 ;
        RECT  85.872 21.408 85.896 21.6 ;
    END
  END o[480]
  PIN o[481]
    DIRECTION OUTPUT ;
    USE SIGNAL ;
    PORT
      LAYER M5 ;
        RECT  86.064 21.408 86.088 21.6 ;
    END
  END o[481]
  PIN o[482]
    DIRECTION OUTPUT ;
    USE SIGNAL ;
    PORT
      LAYER M5 ;
        RECT  86.256 21.408 86.28 21.6 ;
    END
  END o[482]
  PIN o[483]
    DIRECTION OUTPUT ;
    USE SIGNAL ;
    PORT
      LAYER M5 ;
        RECT  86.4 21.408 86.424 21.6 ;
    END
  END o[483]
  PIN o[484]
    DIRECTION OUTPUT ;
    USE SIGNAL ;
    PORT
      LAYER M5 ;
        RECT  86.592 21.408 86.616 21.6 ;
    END
  END o[484]
  PIN o[485]
    DIRECTION OUTPUT ;
    USE SIGNAL ;
    PORT
      LAYER M5 ;
        RECT  86.736 21.408 86.76 21.6 ;
    END
  END o[485]
  PIN o[486]
    DIRECTION OUTPUT ;
    USE SIGNAL ;
    PORT
      LAYER M5 ;
        RECT  86.928 21.408 86.952 21.6 ;
    END
  END o[486]
  PIN o[487]
    DIRECTION OUTPUT ;
    USE SIGNAL ;
    PORT
      LAYER M5 ;
        RECT  87.072 21.408 87.096 21.6 ;
    END
  END o[487]
  PIN o[488]
    DIRECTION OUTPUT ;
    USE SIGNAL ;
    PORT
      LAYER M5 ;
        RECT  87.264 21.408 87.288 21.6 ;
    END
  END o[488]
  PIN o[489]
    DIRECTION OUTPUT ;
    USE SIGNAL ;
    PORT
      LAYER M5 ;
        RECT  87.408 21.408 87.432 21.6 ;
    END
  END o[489]
  PIN o[48]
    DIRECTION OUTPUT ;
    USE SIGNAL ;
    PORT
      LAYER M5 ;
        RECT  12.432 21.408 12.456 21.6 ;
    END
  END o[48]
  PIN o[490]
    DIRECTION OUTPUT ;
    USE SIGNAL ;
    PORT
      LAYER M5 ;
        RECT  87.6 21.408 87.624 21.6 ;
    END
  END o[490]
  PIN o[491]
    DIRECTION OUTPUT ;
    USE SIGNAL ;
    PORT
      LAYER M5 ;
        RECT  87.744 21.408 87.768 21.6 ;
    END
  END o[491]
  PIN o[492]
    DIRECTION OUTPUT ;
    USE SIGNAL ;
    PORT
      LAYER M5 ;
        RECT  87.936 21.408 87.96 21.6 ;
    END
  END o[492]
  PIN o[493]
    DIRECTION OUTPUT ;
    USE SIGNAL ;
    PORT
      LAYER M5 ;
        RECT  88.08 21.408 88.104 21.6 ;
    END
  END o[493]
  PIN o[494]
    DIRECTION OUTPUT ;
    USE SIGNAL ;
    PORT
      LAYER M5 ;
        RECT  88.272 21.408 88.296 21.6 ;
    END
  END o[494]
  PIN o[495]
    DIRECTION OUTPUT ;
    USE SIGNAL ;
    PORT
      LAYER M5 ;
        RECT  88.416 21.408 88.44 21.6 ;
    END
  END o[495]
  PIN o[496]
    DIRECTION OUTPUT ;
    USE SIGNAL ;
    PORT
      LAYER M5 ;
        RECT  88.608 21.408 88.632 21.6 ;
    END
  END o[496]
  PIN o[497]
    DIRECTION OUTPUT ;
    USE SIGNAL ;
    PORT
      LAYER M5 ;
        RECT  88.8 21.408 88.824 21.6 ;
    END
  END o[497]
  PIN o[498]
    DIRECTION OUTPUT ;
    USE SIGNAL ;
    PORT
      LAYER M5 ;
        RECT  88.944 21.408 88.968 21.6 ;
    END
  END o[498]
  PIN o[499]
    DIRECTION OUTPUT ;
    USE SIGNAL ;
    PORT
      LAYER M5 ;
        RECT  89.136 21.408 89.16 21.6 ;
    END
  END o[499]
  PIN o[49]
    DIRECTION OUTPUT ;
    USE SIGNAL ;
    PORT
      LAYER M5 ;
        RECT  12.624 21.408 12.648 21.6 ;
    END
  END o[49]
  PIN o[4]
    DIRECTION OUTPUT ;
    USE SIGNAL ;
    PORT
      LAYER M5 ;
        RECT  4.992 21.408 5.016 21.6 ;
    END
  END o[4]
  PIN o[500]
    DIRECTION OUTPUT ;
    USE SIGNAL ;
    PORT
      LAYER M5 ;
        RECT  89.28 21.408 89.304 21.6 ;
    END
  END o[500]
  PIN o[501]
    DIRECTION OUTPUT ;
    USE SIGNAL ;
    PORT
      LAYER M5 ;
        RECT  89.472 21.408 89.496 21.6 ;
    END
  END o[501]
  PIN o[502]
    DIRECTION OUTPUT ;
    USE SIGNAL ;
    PORT
      LAYER M5 ;
        RECT  89.616 21.408 89.64 21.6 ;
    END
  END o[502]
  PIN o[503]
    DIRECTION OUTPUT ;
    USE SIGNAL ;
    PORT
      LAYER M5 ;
        RECT  89.808 21.408 89.832 21.6 ;
    END
  END o[503]
  PIN o[504]
    DIRECTION OUTPUT ;
    USE SIGNAL ;
    PORT
      LAYER M5 ;
        RECT  89.952 21.408 89.976 21.6 ;
    END
  END o[504]
  PIN o[505]
    DIRECTION OUTPUT ;
    USE SIGNAL ;
    PORT
      LAYER M5 ;
        RECT  90.144 21.408 90.168 21.6 ;
    END
  END o[505]
  PIN o[506]
    DIRECTION OUTPUT ;
    USE SIGNAL ;
    PORT
      LAYER M5 ;
        RECT  90.288 21.408 90.312 21.6 ;
    END
  END o[506]
  PIN o[507]
    DIRECTION OUTPUT ;
    USE SIGNAL ;
    PORT
      LAYER M5 ;
        RECT  90.48 21.408 90.504 21.6 ;
    END
  END o[507]
  PIN o[508]
    DIRECTION OUTPUT ;
    USE SIGNAL ;
    PORT
      LAYER M5 ;
        RECT  90.624 21.408 90.648 21.6 ;
    END
  END o[508]
  PIN o[509]
    DIRECTION OUTPUT ;
    USE SIGNAL ;
    PORT
      LAYER M5 ;
        RECT  90.816 21.408 90.84 21.6 ;
    END
  END o[509]
  PIN o[50]
    DIRECTION OUTPUT ;
    USE SIGNAL ;
    PORT
      LAYER M5 ;
        RECT  12.768 21.408 12.792 21.6 ;
    END
  END o[50]
  PIN o[510]
    DIRECTION OUTPUT ;
    USE SIGNAL ;
    PORT
      LAYER M5 ;
        RECT  90.96 21.408 90.984 21.6 ;
    END
  END o[510]
  PIN o[511]
    DIRECTION OUTPUT ;
    USE SIGNAL ;
    PORT
      LAYER M5 ;
        RECT  91.152 21.408 91.176 21.6 ;
    END
  END o[511]
  PIN o[512]
    DIRECTION OUTPUT ;
    USE SIGNAL ;
    PORT
      LAYER M5 ;
        RECT  91.344 21.408 91.368 21.6 ;
    END
  END o[512]
  PIN o[513]
    DIRECTION OUTPUT ;
    USE SIGNAL ;
    PORT
      LAYER M5 ;
        RECT  91.488 21.408 91.512 21.6 ;
    END
  END o[513]
  PIN o[514]
    DIRECTION OUTPUT ;
    USE SIGNAL ;
    PORT
      LAYER M5 ;
        RECT  91.68 21.408 91.704 21.6 ;
    END
  END o[514]
  PIN o[515]
    DIRECTION OUTPUT ;
    USE SIGNAL ;
    PORT
      LAYER M5 ;
        RECT  91.824 21.408 91.848 21.6 ;
    END
  END o[515]
  PIN o[516]
    DIRECTION OUTPUT ;
    USE SIGNAL ;
    PORT
      LAYER M5 ;
        RECT  92.016 21.408 92.04 21.6 ;
    END
  END o[516]
  PIN o[517]
    DIRECTION OUTPUT ;
    USE SIGNAL ;
    PORT
      LAYER M5 ;
        RECT  92.16 21.408 92.184 21.6 ;
    END
  END o[517]
  PIN o[518]
    DIRECTION OUTPUT ;
    USE SIGNAL ;
    PORT
      LAYER M5 ;
        RECT  92.352 21.408 92.376 21.6 ;
    END
  END o[518]
  PIN o[519]
    DIRECTION OUTPUT ;
    USE SIGNAL ;
    PORT
      LAYER M5 ;
        RECT  92.496 21.408 92.52 21.6 ;
    END
  END o[519]
  PIN o[51]
    DIRECTION OUTPUT ;
    USE SIGNAL ;
    PORT
      LAYER M5 ;
        RECT  12.96 21.408 12.984 21.6 ;
    END
  END o[51]
  PIN o[520]
    DIRECTION OUTPUT ;
    USE SIGNAL ;
    PORT
      LAYER M5 ;
        RECT  92.688 21.408 92.712 21.6 ;
    END
  END o[520]
  PIN o[521]
    DIRECTION OUTPUT ;
    USE SIGNAL ;
    PORT
      LAYER M5 ;
        RECT  92.832 21.408 92.856 21.6 ;
    END
  END o[521]
  PIN o[522]
    DIRECTION OUTPUT ;
    USE SIGNAL ;
    PORT
      LAYER M5 ;
        RECT  93.024 21.408 93.048 21.6 ;
    END
  END o[522]
  PIN o[523]
    DIRECTION OUTPUT ;
    USE SIGNAL ;
    PORT
      LAYER M5 ;
        RECT  93.168 21.408 93.192 21.6 ;
    END
  END o[523]
  PIN o[524]
    DIRECTION OUTPUT ;
    USE SIGNAL ;
    PORT
      LAYER M5 ;
        RECT  93.36 21.408 93.384 21.6 ;
    END
  END o[524]
  PIN o[525]
    DIRECTION OUTPUT ;
    USE SIGNAL ;
    PORT
      LAYER M5 ;
        RECT  93.504 21.408 93.528 21.6 ;
    END
  END o[525]
  PIN o[526]
    DIRECTION OUTPUT ;
    USE SIGNAL ;
    PORT
      LAYER M5 ;
        RECT  93.696 21.408 93.72 21.6 ;
    END
  END o[526]
  PIN o[527]
    DIRECTION OUTPUT ;
    USE SIGNAL ;
    PORT
      LAYER M5 ;
        RECT  93.888 21.408 93.912 21.6 ;
    END
  END o[527]
  PIN o[528]
    DIRECTION OUTPUT ;
    USE SIGNAL ;
    PORT
      LAYER M5 ;
        RECT  94.032 21.408 94.056 21.6 ;
    END
  END o[528]
  PIN o[529]
    DIRECTION OUTPUT ;
    USE SIGNAL ;
    PORT
      LAYER M5 ;
        RECT  94.224 21.408 94.248 21.6 ;
    END
  END o[529]
  PIN o[52]
    DIRECTION OUTPUT ;
    USE SIGNAL ;
    PORT
      LAYER M5 ;
        RECT  13.152 21.408 13.176 21.6 ;
    END
  END o[52]
  PIN o[530]
    DIRECTION OUTPUT ;
    USE SIGNAL ;
    PORT
      LAYER M5 ;
        RECT  94.368 21.408 94.392 21.6 ;
    END
  END o[530]
  PIN o[531]
    DIRECTION OUTPUT ;
    USE SIGNAL ;
    PORT
      LAYER M5 ;
        RECT  94.56 21.408 94.584 21.6 ;
    END
  END o[531]
  PIN o[532]
    DIRECTION OUTPUT ;
    USE SIGNAL ;
    PORT
      LAYER M5 ;
        RECT  94.704 21.408 94.728 21.6 ;
    END
  END o[532]
  PIN o[533]
    DIRECTION OUTPUT ;
    USE SIGNAL ;
    PORT
      LAYER M5 ;
        RECT  94.896 21.408 94.92 21.6 ;
    END
  END o[533]
  PIN o[534]
    DIRECTION OUTPUT ;
    USE SIGNAL ;
    PORT
      LAYER M5 ;
        RECT  95.04 21.408 95.064 21.6 ;
    END
  END o[534]
  PIN o[535]
    DIRECTION OUTPUT ;
    USE SIGNAL ;
    PORT
      LAYER M5 ;
        RECT  95.232 21.408 95.256 21.6 ;
    END
  END o[535]
  PIN o[536]
    DIRECTION OUTPUT ;
    USE SIGNAL ;
    PORT
      LAYER M5 ;
        RECT  95.376 21.408 95.4 21.6 ;
    END
  END o[536]
  PIN o[537]
    DIRECTION OUTPUT ;
    USE SIGNAL ;
    PORT
      LAYER M5 ;
        RECT  95.568 21.408 95.592 21.6 ;
    END
  END o[537]
  PIN o[538]
    DIRECTION OUTPUT ;
    USE SIGNAL ;
    PORT
      LAYER M5 ;
        RECT  95.712 21.408 95.736 21.6 ;
    END
  END o[538]
  PIN o[539]
    DIRECTION OUTPUT ;
    USE SIGNAL ;
    PORT
      LAYER M5 ;
        RECT  95.904 21.408 95.928 21.6 ;
    END
  END o[539]
  PIN o[53]
    DIRECTION OUTPUT ;
    USE SIGNAL ;
    PORT
      LAYER M5 ;
        RECT  13.296 21.408 13.32 21.6 ;
    END
  END o[53]
  PIN o[540]
    DIRECTION OUTPUT ;
    USE SIGNAL ;
    PORT
      LAYER M5 ;
        RECT  96.048 21.408 96.072 21.6 ;
    END
  END o[540]
  PIN o[541]
    DIRECTION OUTPUT ;
    USE SIGNAL ;
    PORT
      LAYER M5 ;
        RECT  96.24 21.408 96.264 21.6 ;
    END
  END o[541]
  PIN o[542]
    DIRECTION OUTPUT ;
    USE SIGNAL ;
    PORT
      LAYER M5 ;
        RECT  96.432 21.408 96.456 21.6 ;
    END
  END o[542]
  PIN o[543]
    DIRECTION OUTPUT ;
    USE SIGNAL ;
    PORT
      LAYER M5 ;
        RECT  96.576 21.408 96.6 21.6 ;
    END
  END o[543]
  PIN o[544]
    DIRECTION OUTPUT ;
    USE SIGNAL ;
    PORT
      LAYER M5 ;
        RECT  96.768 21.408 96.792 21.6 ;
    END
  END o[544]
  PIN o[545]
    DIRECTION OUTPUT ;
    USE SIGNAL ;
    PORT
      LAYER M5 ;
        RECT  96.912 21.408 96.936 21.6 ;
    END
  END o[545]
  PIN o[546]
    DIRECTION OUTPUT ;
    USE SIGNAL ;
    PORT
      LAYER M5 ;
        RECT  97.104 21.408 97.128 21.6 ;
    END
  END o[546]
  PIN o[547]
    DIRECTION OUTPUT ;
    USE SIGNAL ;
    PORT
      LAYER M5 ;
        RECT  97.248 21.408 97.272 21.6 ;
    END
  END o[547]
  PIN o[548]
    DIRECTION OUTPUT ;
    USE SIGNAL ;
    PORT
      LAYER M5 ;
        RECT  97.44 21.408 97.464 21.6 ;
    END
  END o[548]
  PIN o[549]
    DIRECTION OUTPUT ;
    USE SIGNAL ;
    PORT
      LAYER M5 ;
        RECT  97.584 21.408 97.608 21.6 ;
    END
  END o[549]
  PIN o[54]
    DIRECTION OUTPUT ;
    USE SIGNAL ;
    PORT
      LAYER M5 ;
        RECT  13.488 21.408 13.512 21.6 ;
    END
  END o[54]
  PIN o[550]
    DIRECTION OUTPUT ;
    USE SIGNAL ;
    PORT
      LAYER M5 ;
        RECT  97.776 21.408 97.8 21.6 ;
    END
  END o[550]
  PIN o[551]
    DIRECTION OUTPUT ;
    USE SIGNAL ;
    PORT
      LAYER M5 ;
        RECT  97.92 21.408 97.944 21.6 ;
    END
  END o[551]
  PIN o[552]
    DIRECTION OUTPUT ;
    USE SIGNAL ;
    PORT
      LAYER M5 ;
        RECT  98.112 21.408 98.136 21.6 ;
    END
  END o[552]
  PIN o[553]
    DIRECTION OUTPUT ;
    USE SIGNAL ;
    PORT
      LAYER M5 ;
        RECT  98.256 21.408 98.28 21.6 ;
    END
  END o[553]
  PIN o[554]
    DIRECTION OUTPUT ;
    USE SIGNAL ;
    PORT
      LAYER M5 ;
        RECT  98.448 21.408 98.472 21.6 ;
    END
  END o[554]
  PIN o[555]
    DIRECTION OUTPUT ;
    USE SIGNAL ;
    PORT
      LAYER M5 ;
        RECT  98.592 21.408 98.616 21.6 ;
    END
  END o[555]
  PIN o[556]
    DIRECTION OUTPUT ;
    USE SIGNAL ;
    PORT
      LAYER M5 ;
        RECT  98.784 21.408 98.808 21.6 ;
    END
  END o[556]
  PIN o[557]
    DIRECTION OUTPUT ;
    USE SIGNAL ;
    PORT
      LAYER M5 ;
        RECT  98.976 21.408 99 21.6 ;
    END
  END o[557]
  PIN o[558]
    DIRECTION OUTPUT ;
    USE SIGNAL ;
    PORT
      LAYER M5 ;
        RECT  99.12 21.408 99.144 21.6 ;
    END
  END o[558]
  PIN o[559]
    DIRECTION OUTPUT ;
    USE SIGNAL ;
    PORT
      LAYER M5 ;
        RECT  99.312 21.408 99.336 21.6 ;
    END
  END o[559]
  PIN o[55]
    DIRECTION OUTPUT ;
    USE SIGNAL ;
    PORT
      LAYER M5 ;
        RECT  13.632 21.408 13.656 21.6 ;
    END
  END o[55]
  PIN o[560]
    DIRECTION OUTPUT ;
    USE SIGNAL ;
    PORT
      LAYER M5 ;
        RECT  99.456 21.408 99.48 21.6 ;
    END
  END o[560]
  PIN o[561]
    DIRECTION OUTPUT ;
    USE SIGNAL ;
    PORT
      LAYER M5 ;
        RECT  99.648 21.408 99.672 21.6 ;
    END
  END o[561]
  PIN o[562]
    DIRECTION OUTPUT ;
    USE SIGNAL ;
    PORT
      LAYER M5 ;
        RECT  99.792 21.408 99.816 21.6 ;
    END
  END o[562]
  PIN o[563]
    DIRECTION OUTPUT ;
    USE SIGNAL ;
    PORT
      LAYER M5 ;
        RECT  99.984 21.408 100.008 21.6 ;
    END
  END o[563]
  PIN o[564]
    DIRECTION OUTPUT ;
    USE SIGNAL ;
    PORT
      LAYER M5 ;
        RECT  100.128 21.408 100.152 21.6 ;
    END
  END o[564]
  PIN o[565]
    DIRECTION OUTPUT ;
    USE SIGNAL ;
    PORT
      LAYER M5 ;
        RECT  100.32 21.408 100.344 21.6 ;
    END
  END o[565]
  PIN o[566]
    DIRECTION OUTPUT ;
    USE SIGNAL ;
    PORT
      LAYER M5 ;
        RECT  100.464 21.408 100.488 21.6 ;
    END
  END o[566]
  PIN o[567]
    DIRECTION OUTPUT ;
    USE SIGNAL ;
    PORT
      LAYER M5 ;
        RECT  100.656 21.408 100.68 21.6 ;
    END
  END o[567]
  PIN o[568]
    DIRECTION OUTPUT ;
    USE SIGNAL ;
    PORT
      LAYER M5 ;
        RECT  100.8 21.408 100.824 21.6 ;
    END
  END o[568]
  PIN o[569]
    DIRECTION OUTPUT ;
    USE SIGNAL ;
    PORT
      LAYER M5 ;
        RECT  100.992 21.408 101.016 21.6 ;
    END
  END o[569]
  PIN o[56]
    DIRECTION OUTPUT ;
    USE SIGNAL ;
    PORT
      LAYER M5 ;
        RECT  13.824 21.408 13.848 21.6 ;
    END
  END o[56]
  PIN o[570]
    DIRECTION OUTPUT ;
    USE SIGNAL ;
    PORT
      LAYER M5 ;
        RECT  101.136 21.408 101.16 21.6 ;
    END
  END o[570]
  PIN o[571]
    DIRECTION OUTPUT ;
    USE SIGNAL ;
    PORT
      LAYER M5 ;
        RECT  101.328 21.408 101.352 21.6 ;
    END
  END o[571]
  PIN o[572]
    DIRECTION OUTPUT ;
    USE SIGNAL ;
    PORT
      LAYER M5 ;
        RECT  101.52 21.408 101.544 21.6 ;
    END
  END o[572]
  PIN o[573]
    DIRECTION OUTPUT ;
    USE SIGNAL ;
    PORT
      LAYER M5 ;
        RECT  101.664 21.408 101.688 21.6 ;
    END
  END o[573]
  PIN o[574]
    DIRECTION OUTPUT ;
    USE SIGNAL ;
    PORT
      LAYER M5 ;
        RECT  101.856 21.408 101.88 21.6 ;
    END
  END o[574]
  PIN o[575]
    DIRECTION OUTPUT ;
    USE SIGNAL ;
    PORT
      LAYER M5 ;
        RECT  102 21.408 102.024 21.6 ;
    END
  END o[575]
  PIN o[576]
    DIRECTION OUTPUT ;
    USE SIGNAL ;
    PORT
      LAYER M5 ;
        RECT  102.192 21.408 102.216 21.6 ;
    END
  END o[576]
  PIN o[577]
    DIRECTION OUTPUT ;
    USE SIGNAL ;
    PORT
      LAYER M5 ;
        RECT  102.336 21.408 102.36 21.6 ;
    END
  END o[577]
  PIN o[578]
    DIRECTION OUTPUT ;
    USE SIGNAL ;
    PORT
      LAYER M5 ;
        RECT  102.528 21.408 102.552 21.6 ;
    END
  END o[578]
  PIN o[579]
    DIRECTION OUTPUT ;
    USE SIGNAL ;
    PORT
      LAYER M5 ;
        RECT  102.672 21.408 102.696 21.6 ;
    END
  END o[579]
  PIN o[57]
    DIRECTION OUTPUT ;
    USE SIGNAL ;
    PORT
      LAYER M5 ;
        RECT  13.968 21.408 13.992 21.6 ;
    END
  END o[57]
  PIN o[580]
    DIRECTION OUTPUT ;
    USE SIGNAL ;
    PORT
      LAYER M5 ;
        RECT  102.864 21.408 102.888 21.6 ;
    END
  END o[580]
  PIN o[581]
    DIRECTION OUTPUT ;
    USE SIGNAL ;
    PORT
      LAYER M5 ;
        RECT  103.008 21.408 103.032 21.6 ;
    END
  END o[581]
  PIN o[582]
    DIRECTION OUTPUT ;
    USE SIGNAL ;
    PORT
      LAYER M5 ;
        RECT  103.2 21.408 103.224 21.6 ;
    END
  END o[582]
  PIN o[583]
    DIRECTION OUTPUT ;
    USE SIGNAL ;
    PORT
      LAYER M5 ;
        RECT  103.344 21.408 103.368 21.6 ;
    END
  END o[583]
  PIN o[584]
    DIRECTION OUTPUT ;
    USE SIGNAL ;
    PORT
      LAYER M5 ;
        RECT  103.536 21.408 103.56 21.6 ;
    END
  END o[584]
  PIN o[585]
    DIRECTION OUTPUT ;
    USE SIGNAL ;
    PORT
      LAYER M5 ;
        RECT  103.68 21.408 103.704 21.6 ;
    END
  END o[585]
  PIN o[586]
    DIRECTION OUTPUT ;
    USE SIGNAL ;
    PORT
      LAYER M5 ;
        RECT  103.872 21.408 103.896 21.6 ;
    END
  END o[586]
  PIN o[587]
    DIRECTION OUTPUT ;
    USE SIGNAL ;
    PORT
      LAYER M5 ;
        RECT  104.064 21.408 104.088 21.6 ;
    END
  END o[587]
  PIN o[588]
    DIRECTION OUTPUT ;
    USE SIGNAL ;
    PORT
      LAYER M5 ;
        RECT  104.208 21.408 104.232 21.6 ;
    END
  END o[588]
  PIN o[589]
    DIRECTION OUTPUT ;
    USE SIGNAL ;
    PORT
      LAYER M5 ;
        RECT  104.4 21.408 104.424 21.6 ;
    END
  END o[589]
  PIN o[58]
    DIRECTION OUTPUT ;
    USE SIGNAL ;
    PORT
      LAYER M5 ;
        RECT  14.16 21.408 14.184 21.6 ;
    END
  END o[58]
  PIN o[590]
    DIRECTION OUTPUT ;
    USE SIGNAL ;
    PORT
      LAYER M5 ;
        RECT  104.544 21.408 104.568 21.6 ;
    END
  END o[590]
  PIN o[591]
    DIRECTION OUTPUT ;
    USE SIGNAL ;
    PORT
      LAYER M5 ;
        RECT  104.736 21.408 104.76 21.6 ;
    END
  END o[591]
  PIN o[592]
    DIRECTION OUTPUT ;
    USE SIGNAL ;
    PORT
      LAYER M5 ;
        RECT  104.88 21.408 104.904 21.6 ;
    END
  END o[592]
  PIN o[593]
    DIRECTION OUTPUT ;
    USE SIGNAL ;
    PORT
      LAYER M5 ;
        RECT  105.072 21.408 105.096 21.6 ;
    END
  END o[593]
  PIN o[594]
    DIRECTION OUTPUT ;
    USE SIGNAL ;
    PORT
      LAYER M5 ;
        RECT  105.216 21.408 105.24 21.6 ;
    END
  END o[594]
  PIN o[595]
    DIRECTION OUTPUT ;
    USE SIGNAL ;
    PORT
      LAYER M5 ;
        RECT  105.408 21.408 105.432 21.6 ;
    END
  END o[595]
  PIN o[596]
    DIRECTION OUTPUT ;
    USE SIGNAL ;
    PORT
      LAYER M5 ;
        RECT  105.552 21.408 105.576 21.6 ;
    END
  END o[596]
  PIN o[597]
    DIRECTION OUTPUT ;
    USE SIGNAL ;
    PORT
      LAYER M5 ;
        RECT  105.744 21.408 105.768 21.6 ;
    END
  END o[597]
  PIN o[598]
    DIRECTION OUTPUT ;
    USE SIGNAL ;
    PORT
      LAYER M5 ;
        RECT  105.888 21.408 105.912 21.6 ;
    END
  END o[598]
  PIN o[599]
    DIRECTION OUTPUT ;
    USE SIGNAL ;
    PORT
      LAYER M5 ;
        RECT  106.08 21.408 106.104 21.6 ;
    END
  END o[599]
  PIN o[59]
    DIRECTION OUTPUT ;
    USE SIGNAL ;
    PORT
      LAYER M5 ;
        RECT  14.304 21.408 14.328 21.6 ;
    END
  END o[59]
  PIN o[5]
    DIRECTION OUTPUT ;
    USE SIGNAL ;
    PORT
      LAYER M5 ;
        RECT  5.136 21.408 5.16 21.6 ;
    END
  END o[5]
  PIN o[600]
    DIRECTION OUTPUT ;
    USE SIGNAL ;
    PORT
      LAYER M5 ;
        RECT  106.224 21.408 106.248 21.6 ;
    END
  END o[600]
  PIN o[601]
    DIRECTION OUTPUT ;
    USE SIGNAL ;
    PORT
      LAYER M5 ;
        RECT  106.416 21.408 106.44 21.6 ;
    END
  END o[601]
  PIN o[602]
    DIRECTION OUTPUT ;
    USE SIGNAL ;
    PORT
      LAYER M5 ;
        RECT  106.608 21.408 106.632 21.6 ;
    END
  END o[602]
  PIN o[603]
    DIRECTION OUTPUT ;
    USE SIGNAL ;
    PORT
      LAYER M5 ;
        RECT  106.752 21.408 106.776 21.6 ;
    END
  END o[603]
  PIN o[604]
    DIRECTION OUTPUT ;
    USE SIGNAL ;
    PORT
      LAYER M5 ;
        RECT  106.944 21.408 106.968 21.6 ;
    END
  END o[604]
  PIN o[605]
    DIRECTION OUTPUT ;
    USE SIGNAL ;
    PORT
      LAYER M5 ;
        RECT  107.088 21.408 107.112 21.6 ;
    END
  END o[605]
  PIN o[606]
    DIRECTION OUTPUT ;
    USE SIGNAL ;
    PORT
      LAYER M5 ;
        RECT  107.28 21.408 107.304 21.6 ;
    END
  END o[606]
  PIN o[607]
    DIRECTION OUTPUT ;
    USE SIGNAL ;
    PORT
      LAYER M5 ;
        RECT  107.424 21.408 107.448 21.6 ;
    END
  END o[607]
  PIN o[608]
    DIRECTION OUTPUT ;
    USE SIGNAL ;
    PORT
      LAYER M5 ;
        RECT  107.616 21.408 107.64 21.6 ;
    END
  END o[608]
  PIN o[609]
    DIRECTION OUTPUT ;
    USE SIGNAL ;
    PORT
      LAYER M5 ;
        RECT  107.76 21.408 107.784 21.6 ;
    END
  END o[609]
  PIN o[60]
    DIRECTION OUTPUT ;
    USE SIGNAL ;
    PORT
      LAYER M5 ;
        RECT  14.496 21.408 14.52 21.6 ;
    END
  END o[60]
  PIN o[610]
    DIRECTION OUTPUT ;
    USE SIGNAL ;
    PORT
      LAYER M5 ;
        RECT  107.952 21.408 107.976 21.6 ;
    END
  END o[610]
  PIN o[611]
    DIRECTION OUTPUT ;
    USE SIGNAL ;
    PORT
      LAYER M5 ;
        RECT  108.096 21.408 108.12 21.6 ;
    END
  END o[611]
  PIN o[612]
    DIRECTION OUTPUT ;
    USE SIGNAL ;
    PORT
      LAYER M5 ;
        RECT  108.288 21.408 108.312 21.6 ;
    END
  END o[612]
  PIN o[613]
    DIRECTION OUTPUT ;
    USE SIGNAL ;
    PORT
      LAYER M5 ;
        RECT  108.432 21.408 108.456 21.6 ;
    END
  END o[613]
  PIN o[614]
    DIRECTION OUTPUT ;
    USE SIGNAL ;
    PORT
      LAYER M5 ;
        RECT  108.624 21.408 108.648 21.6 ;
    END
  END o[614]
  PIN o[615]
    DIRECTION OUTPUT ;
    USE SIGNAL ;
    PORT
      LAYER M5 ;
        RECT  108.768 21.408 108.792 21.6 ;
    END
  END o[615]
  PIN o[616]
    DIRECTION OUTPUT ;
    USE SIGNAL ;
    PORT
      LAYER M5 ;
        RECT  108.96 21.408 108.984 21.6 ;
    END
  END o[616]
  PIN o[617]
    DIRECTION OUTPUT ;
    USE SIGNAL ;
    PORT
      LAYER M5 ;
        RECT  109.152 21.408 109.176 21.6 ;
    END
  END o[617]
  PIN o[618]
    DIRECTION OUTPUT ;
    USE SIGNAL ;
    PORT
      LAYER M5 ;
        RECT  109.296 21.408 109.32 21.6 ;
    END
  END o[618]
  PIN o[619]
    DIRECTION OUTPUT ;
    USE SIGNAL ;
    PORT
      LAYER M5 ;
        RECT  109.488 21.408 109.512 21.6 ;
    END
  END o[619]
  PIN o[61]
    DIRECTION OUTPUT ;
    USE SIGNAL ;
    PORT
      LAYER M5 ;
        RECT  14.64 21.408 14.664 21.6 ;
    END
  END o[61]
  PIN o[620]
    DIRECTION OUTPUT ;
    USE SIGNAL ;
    PORT
      LAYER M5 ;
        RECT  109.632 21.408 109.656 21.6 ;
    END
  END o[620]
  PIN o[621]
    DIRECTION OUTPUT ;
    USE SIGNAL ;
    PORT
      LAYER M5 ;
        RECT  109.824 21.408 109.848 21.6 ;
    END
  END o[621]
  PIN o[622]
    DIRECTION OUTPUT ;
    USE SIGNAL ;
    PORT
      LAYER M5 ;
        RECT  109.968 21.408 109.992 21.6 ;
    END
  END o[622]
  PIN o[623]
    DIRECTION OUTPUT ;
    USE SIGNAL ;
    PORT
      LAYER M5 ;
        RECT  110.16 21.408 110.184 21.6 ;
    END
  END o[623]
  PIN o[62]
    DIRECTION OUTPUT ;
    USE SIGNAL ;
    PORT
      LAYER M5 ;
        RECT  14.832 21.408 14.856 21.6 ;
    END
  END o[62]
  PIN o[63]
    DIRECTION OUTPUT ;
    USE SIGNAL ;
    PORT
      LAYER M5 ;
        RECT  14.976 21.408 15 21.6 ;
    END
  END o[63]
  PIN o[64]
    DIRECTION OUTPUT ;
    USE SIGNAL ;
    PORT
      LAYER M5 ;
        RECT  15.168 21.408 15.192 21.6 ;
    END
  END o[64]
  PIN o[65]
    DIRECTION OUTPUT ;
    USE SIGNAL ;
    PORT
      LAYER M5 ;
        RECT  15.312 21.408 15.336 21.6 ;
    END
  END o[65]
  PIN o[66]
    DIRECTION OUTPUT ;
    USE SIGNAL ;
    PORT
      LAYER M5 ;
        RECT  15.504 21.408 15.528 21.6 ;
    END
  END o[66]
  PIN o[67]
    DIRECTION OUTPUT ;
    USE SIGNAL ;
    PORT
      LAYER M5 ;
        RECT  15.696 21.408 15.72 21.6 ;
    END
  END o[67]
  PIN o[68]
    DIRECTION OUTPUT ;
    USE SIGNAL ;
    PORT
      LAYER M5 ;
        RECT  15.84 21.408 15.864 21.6 ;
    END
  END o[68]
  PIN o[69]
    DIRECTION OUTPUT ;
    USE SIGNAL ;
    PORT
      LAYER M5 ;
        RECT  16.032 21.408 16.056 21.6 ;
    END
  END o[69]
  PIN o[6]
    DIRECTION OUTPUT ;
    USE SIGNAL ;
    PORT
      LAYER M5 ;
        RECT  5.328 21.408 5.352 21.6 ;
    END
  END o[6]
  PIN o[70]
    DIRECTION OUTPUT ;
    USE SIGNAL ;
    PORT
      LAYER M5 ;
        RECT  16.176 21.408 16.2 21.6 ;
    END
  END o[70]
  PIN o[71]
    DIRECTION OUTPUT ;
    USE SIGNAL ;
    PORT
      LAYER M5 ;
        RECT  16.368 21.408 16.392 21.6 ;
    END
  END o[71]
  PIN o[72]
    DIRECTION OUTPUT ;
    USE SIGNAL ;
    PORT
      LAYER M5 ;
        RECT  16.512 21.408 16.536 21.6 ;
    END
  END o[72]
  PIN o[73]
    DIRECTION OUTPUT ;
    USE SIGNAL ;
    PORT
      LAYER M5 ;
        RECT  16.704 21.408 16.728 21.6 ;
    END
  END o[73]
  PIN o[74]
    DIRECTION OUTPUT ;
    USE SIGNAL ;
    PORT
      LAYER M5 ;
        RECT  16.848 21.408 16.872 21.6 ;
    END
  END o[74]
  PIN o[75]
    DIRECTION OUTPUT ;
    USE SIGNAL ;
    PORT
      LAYER M5 ;
        RECT  17.04 21.408 17.064 21.6 ;
    END
  END o[75]
  PIN o[76]
    DIRECTION OUTPUT ;
    USE SIGNAL ;
    PORT
      LAYER M5 ;
        RECT  17.184 21.408 17.208 21.6 ;
    END
  END o[76]
  PIN o[77]
    DIRECTION OUTPUT ;
    USE SIGNAL ;
    PORT
      LAYER M5 ;
        RECT  17.376 21.408 17.4 21.6 ;
    END
  END o[77]
  PIN o[78]
    DIRECTION OUTPUT ;
    USE SIGNAL ;
    PORT
      LAYER M5 ;
        RECT  17.52 21.408 17.544 21.6 ;
    END
  END o[78]
  PIN o[79]
    DIRECTION OUTPUT ;
    USE SIGNAL ;
    PORT
      LAYER M5 ;
        RECT  17.712 21.408 17.736 21.6 ;
    END
  END o[79]
  PIN o[7]
    DIRECTION OUTPUT ;
    USE SIGNAL ;
    PORT
      LAYER M5 ;
        RECT  5.472 21.408 5.496 21.6 ;
    END
  END o[7]
  PIN o[80]
    DIRECTION OUTPUT ;
    USE SIGNAL ;
    PORT
      LAYER M5 ;
        RECT  17.856 21.408 17.88 21.6 ;
    END
  END o[80]
  PIN o[81]
    DIRECTION OUTPUT ;
    USE SIGNAL ;
    PORT
      LAYER M5 ;
        RECT  18.048 21.408 18.072 21.6 ;
    END
  END o[81]
  PIN o[82]
    DIRECTION OUTPUT ;
    USE SIGNAL ;
    PORT
      LAYER M5 ;
        RECT  18.24 21.408 18.264 21.6 ;
    END
  END o[82]
  PIN o[83]
    DIRECTION OUTPUT ;
    USE SIGNAL ;
    PORT
      LAYER M5 ;
        RECT  18.384 21.408 18.408 21.6 ;
    END
  END o[83]
  PIN o[84]
    DIRECTION OUTPUT ;
    USE SIGNAL ;
    PORT
      LAYER M5 ;
        RECT  18.576 21.408 18.6 21.6 ;
    END
  END o[84]
  PIN o[85]
    DIRECTION OUTPUT ;
    USE SIGNAL ;
    PORT
      LAYER M5 ;
        RECT  18.72 21.408 18.744 21.6 ;
    END
  END o[85]
  PIN o[86]
    DIRECTION OUTPUT ;
    USE SIGNAL ;
    PORT
      LAYER M5 ;
        RECT  18.912 21.408 18.936 21.6 ;
    END
  END o[86]
  PIN o[87]
    DIRECTION OUTPUT ;
    USE SIGNAL ;
    PORT
      LAYER M5 ;
        RECT  19.056 21.408 19.08 21.6 ;
    END
  END o[87]
  PIN o[88]
    DIRECTION OUTPUT ;
    USE SIGNAL ;
    PORT
      LAYER M5 ;
        RECT  19.248 21.408 19.272 21.6 ;
    END
  END o[88]
  PIN o[89]
    DIRECTION OUTPUT ;
    USE SIGNAL ;
    PORT
      LAYER M5 ;
        RECT  19.392 21.408 19.416 21.6 ;
    END
  END o[89]
  PIN o[8]
    DIRECTION OUTPUT ;
    USE SIGNAL ;
    PORT
      LAYER M5 ;
        RECT  5.664 21.408 5.688 21.6 ;
    END
  END o[8]
  PIN o[90]
    DIRECTION OUTPUT ;
    USE SIGNAL ;
    PORT
      LAYER M5 ;
        RECT  19.584 21.408 19.608 21.6 ;
    END
  END o[90]
  PIN o[91]
    DIRECTION OUTPUT ;
    USE SIGNAL ;
    PORT
      LAYER M5 ;
        RECT  19.728 21.408 19.752 21.6 ;
    END
  END o[91]
  PIN o[92]
    DIRECTION OUTPUT ;
    USE SIGNAL ;
    PORT
      LAYER M5 ;
        RECT  19.92 21.408 19.944 21.6 ;
    END
  END o[92]
  PIN o[93]
    DIRECTION OUTPUT ;
    USE SIGNAL ;
    PORT
      LAYER M5 ;
        RECT  20.064 21.408 20.088 21.6 ;
    END
  END o[93]
  PIN o[94]
    DIRECTION OUTPUT ;
    USE SIGNAL ;
    PORT
      LAYER M5 ;
        RECT  20.256 21.408 20.28 21.6 ;
    END
  END o[94]
  PIN o[95]
    DIRECTION OUTPUT ;
    USE SIGNAL ;
    PORT
      LAYER M5 ;
        RECT  20.4 21.408 20.424 21.6 ;
    END
  END o[95]
  PIN o[96]
    DIRECTION OUTPUT ;
    USE SIGNAL ;
    PORT
      LAYER M5 ;
        RECT  20.592 21.408 20.616 21.6 ;
    END
  END o[96]
  PIN o[97]
    DIRECTION OUTPUT ;
    USE SIGNAL ;
    PORT
      LAYER M5 ;
        RECT  20.784 21.408 20.808 21.6 ;
    END
  END o[97]
  PIN o[98]
    DIRECTION OUTPUT ;
    USE SIGNAL ;
    PORT
      LAYER M5 ;
        RECT  20.928 21.408 20.952 21.6 ;
    END
  END o[98]
  PIN o[99]
    DIRECTION OUTPUT ;
    USE SIGNAL ;
    PORT
      LAYER M5 ;
        RECT  21.12 21.408 21.144 21.6 ;
    END
  END o[99]
  PIN o[9]
    DIRECTION OUTPUT ;
    USE SIGNAL ;
    PORT
      LAYER M5 ;
        RECT  5.856 21.408 5.88 21.6 ;
    END
  END o[9]
  PIN rs
    DIRECTION INPUT ;
    USE SIGNAL ;
    PORT
      LAYER M4 ;
        RECT  0 10.8 0.192 10.824 ;
    END
  END rs
  PIN VDD
    DIRECTION INOUT ;
    USE POWER ;
    PORT
      LAYER M5 ;
        RECT  110.592 2.151 110.712 19.449 ;
        RECT  107.892 2.151 108.012 19.449 ;
        RECT  105.192 2.151 105.312 19.449 ;
        RECT  102.492 2.151 102.612 19.449 ;
        RECT  99.792 2.151 99.912 19.449 ;
        RECT  97.092 2.151 97.212 19.449 ;
        RECT  94.392 2.151 94.512 19.449 ;
        RECT  91.692 2.151 91.812 19.449 ;
        RECT  88.992 2.151 89.112 19.449 ;
        RECT  86.292 2.151 86.412 19.449 ;
        RECT  83.592 2.151 83.712 19.449 ;
        RECT  80.892 2.151 81.012 19.449 ;
        RECT  78.192 2.151 78.312 19.449 ;
        RECT  75.492 2.151 75.612 19.449 ;
        RECT  72.792 2.151 72.912 19.449 ;
        RECT  70.092 2.151 70.212 19.449 ;
        RECT  67.392 2.151 67.512 19.449 ;
        RECT  64.692 2.151 64.812 19.449 ;
        RECT  61.992 2.151 62.112 19.449 ;
        RECT  59.292 2.151 59.412 19.449 ;
        RECT  56.592 2.151 56.712 19.449 ;
        RECT  53.892 2.151 54.012 19.449 ;
        RECT  51.192 2.151 51.312 19.449 ;
        RECT  48.492 2.151 48.612 19.449 ;
        RECT  45.792 2.151 45.912 19.449 ;
        RECT  43.092 2.151 43.212 19.449 ;
        RECT  40.392 2.151 40.512 19.449 ;
        RECT  37.692 2.151 37.812 19.449 ;
        RECT  34.992 2.151 35.112 19.449 ;
        RECT  32.292 2.151 32.412 19.449 ;
        RECT  29.592 2.151 29.712 19.449 ;
        RECT  26.892 2.151 27.012 19.449 ;
        RECT  24.192 2.151 24.312 19.449 ;
        RECT  21.492 2.151 21.612 19.449 ;
        RECT  18.792 2.151 18.912 19.449 ;
        RECT  16.092 2.151 16.212 19.449 ;
        RECT  13.392 2.151 13.512 19.449 ;
        RECT  10.692 2.151 10.812 19.449 ;
        RECT  7.992 2.151 8.112 19.449 ;
        RECT  5.292 2.151 5.412 19.449 ;
        RECT  2.592 2.151 2.712 19.449 ;
    END
  END VDD
  PIN VSS
    DIRECTION INOUT ;
    USE GROUND ;
    PORT
      LAYER M5 ;
        RECT  110.4 2.137 110.52 19.463 ;
        RECT  107.7 2.137 107.82 19.463 ;
        RECT  105 2.137 105.12 19.463 ;
        RECT  102.3 2.137 102.42 19.463 ;
        RECT  99.6 2.137 99.72 19.463 ;
        RECT  96.9 2.137 97.02 19.463 ;
        RECT  94.2 2.137 94.32 19.463 ;
        RECT  91.5 2.137 91.62 19.463 ;
        RECT  88.8 2.137 88.92 19.463 ;
        RECT  86.1 2.137 86.22 19.463 ;
        RECT  83.4 2.137 83.52 19.463 ;
        RECT  80.7 2.137 80.82 19.463 ;
        RECT  78 2.137 78.12 19.463 ;
        RECT  75.3 2.137 75.42 19.463 ;
        RECT  72.6 2.137 72.72 19.463 ;
        RECT  69.9 2.137 70.02 19.463 ;
        RECT  67.2 2.137 67.32 19.463 ;
        RECT  64.5 2.137 64.62 19.463 ;
        RECT  61.8 2.137 61.92 19.463 ;
        RECT  59.1 2.137 59.22 19.463 ;
        RECT  56.4 2.137 56.52 19.463 ;
        RECT  53.7 2.137 53.82 19.463 ;
        RECT  51 2.137 51.12 19.463 ;
        RECT  48.3 2.137 48.42 19.463 ;
        RECT  45.6 2.137 45.72 19.463 ;
        RECT  42.9 2.137 43.02 19.463 ;
        RECT  40.2 2.137 40.32 19.463 ;
        RECT  37.5 2.137 37.62 19.463 ;
        RECT  34.8 2.137 34.92 19.463 ;
        RECT  32.1 2.137 32.22 19.463 ;
        RECT  29.4 2.137 29.52 19.463 ;
        RECT  26.7 2.137 26.82 19.463 ;
        RECT  24 2.137 24.12 19.463 ;
        RECT  21.3 2.137 21.42 19.463 ;
        RECT  18.6 2.137 18.72 19.463 ;
        RECT  15.9 2.137 16.02 19.463 ;
        RECT  13.2 2.137 13.32 19.463 ;
        RECT  10.5 2.137 10.62 19.463 ;
        RECT  7.8 2.137 7.92 19.463 ;
        RECT  5.1 2.137 5.22 19.463 ;
        RECT  2.4 2.137 2.52 19.463 ;
    END
  END VSS
  OBS
    LAYER RVTN ;
     RECT  2.16 2.16 112.32 2.295 ;
     RECT  2.16 2.565 112.32 2.835 ;
     RECT  2.16 3.105 112.32 3.375 ;
     RECT  2.16 3.645 112.32 3.915 ;
     RECT  2.16 4.185 112.32 4.455 ;
     RECT  2.16 4.725 112.32 4.995 ;
     RECT  2.16 5.265 112.32 5.535 ;
     RECT  2.16 5.805 112.32 6.075 ;
     RECT  2.16 6.345 112.32 6.615 ;
     RECT  2.16 6.885 112.32 7.155 ;
     RECT  2.16 7.425 112.32 7.695 ;
     RECT  2.16 7.965 112.32 8.235 ;
     RECT  2.16 8.505 112.32 8.775 ;
     RECT  2.16 9.045 112.32 9.315 ;
     RECT  2.16 9.585 112.32 9.855 ;
     RECT  2.16 10.125 112.32 10.395 ;
     RECT  2.16 10.665 112.32 10.935 ;
     RECT  2.16 11.205 112.32 11.475 ;
     RECT  2.16 11.745 112.32 12.015 ;
     RECT  2.16 12.285 112.32 12.555 ;
     RECT  2.16 12.825 112.32 13.095 ;
     RECT  2.16 13.365 112.32 13.635 ;
     RECT  2.16 13.905 112.32 14.175 ;
     RECT  2.16 14.445 112.32 14.715 ;
     RECT  2.16 14.985 112.32 15.255 ;
     RECT  2.16 15.525 112.32 15.795 ;
     RECT  2.16 16.065 112.32 16.335 ;
     RECT  2.16 16.605 112.32 16.875 ;
     RECT  2.16 17.145 112.32 17.415 ;
     RECT  2.16 17.685 112.32 17.955 ;
     RECT  2.16 18.225 112.32 18.495 ;
     RECT  2.16 18.765 112.32 19.035 ;
     RECT  2.16 19.305 112.32 19.44 ;
    LAYER RVTP ;
     RECT  2.16 2.295 112.32 2.565 ;
     RECT  2.16 2.835 112.32 3.105 ;
     RECT  2.16 3.375 112.32 3.645 ;
     RECT  2.16 3.915 112.32 4.185 ;
     RECT  2.16 4.455 112.32 4.725 ;
     RECT  2.16 4.995 112.32 5.265 ;
     RECT  2.16 5.535 112.32 5.805 ;
     RECT  2.16 6.075 112.32 6.345 ;
     RECT  2.16 6.615 112.32 6.885 ;
     RECT  2.16 7.155 112.32 7.425 ;
     RECT  2.16 7.695 112.32 7.965 ;
     RECT  2.16 8.235 112.32 8.505 ;
     RECT  2.16 8.775 112.32 9.045 ;
     RECT  2.16 9.315 112.32 9.585 ;
     RECT  2.16 9.855 112.32 10.125 ;
     RECT  2.16 10.395 112.32 10.665 ;
     RECT  2.16 10.935 112.32 11.205 ;
     RECT  2.16 11.475 112.32 11.745 ;
     RECT  2.16 12.015 112.32 12.285 ;
     RECT  2.16 12.555 112.32 12.825 ;
     RECT  2.16 13.095 112.32 13.365 ;
     RECT  2.16 13.635 112.32 13.905 ;
     RECT  2.16 14.175 112.32 14.445 ;
     RECT  2.16 14.715 112.32 14.985 ;
     RECT  2.16 15.255 112.32 15.525 ;
     RECT  2.16 15.795 112.32 16.065 ;
     RECT  2.16 16.335 112.32 16.605 ;
     RECT  2.16 16.875 112.32 17.145 ;
     RECT  2.16 17.415 112.32 17.685 ;
     RECT  2.16 17.955 112.32 18.225 ;
     RECT  2.16 18.495 112.32 18.765 ;
     RECT  2.16 19.035 112.32 19.305 ;
    LAYER M1 ;
     RECT  2.16 2.151 112.32 19.449 ;
    LAYER M2 ;
     RECT  0.211 10.908 2.16 10.926 ;
     RECT  2.16 2.151 12.163 19.449 ;
     RECT  12.163 2.106 13.163 19.449 ;
     RECT  13.163 2.151 39.487 19.449 ;
     RECT  39.487 2.106 40.199 19.449 ;
     RECT  40.199 2.151 61.699 19.449 ;
     RECT  61.699 2.106 62.015 19.449 ;
     RECT  62.015 2.151 63.607 19.449 ;
     RECT  63.607 2.106 63.851 19.449 ;
     RECT  63.851 2.151 77.107 19.449 ;
     RECT  77.107 2.106 77.927 19.449 ;
     RECT  77.927 2.151 110.767 19.449 ;
     RECT  110.767 2.106 111.155 19.449 ;
     RECT  111.155 2.151 112.32 19.449 ;
    LAYER M3 ;
     RECT  46.044 0.187 46.062 0.571 ;
     RECT  13.788 1.099 13.806 1.723 ;
     RECT  29.592 0.235 29.61 1.723 ;
     RECT  31.824 0.187 31.842 1.723 ;
     RECT  35.28 1.099 35.298 1.723 ;
     RECT  41.616 0.571 41.634 1.723 ;
     RECT  46.044 0.571 46.314 1.723 ;
     RECT  51.156 0.523 51.174 1.723 ;
     RECT  52.956 0.187 52.974 1.723 ;
     RECT  60.408 0.187 60.426 1.723 ;
     RECT  66.456 0.187 66.474 1.723 ;
     RECT  68.364 0.187 68.382 1.723 ;
     RECT  75.816 0.571 75.834 1.723 ;
     RECT  9.252 1.723 12.726 1.771 ;
     RECT  13.572 1.723 17.154 1.771 ;
     RECT  81.252 1.723 90.918 1.771 ;
     RECT  91.656 1.723 104.49 1.771 ;
     RECT  105.372 1.723 110.106 1.771 ;
     RECT  49.932 1.723 80.514 1.819 ;
     RECT  81.252 1.771 104.49 1.819 ;
     RECT  105.3 1.771 110.106 1.819 ;
     RECT  111.06 1.771 111.078 1.819 ;
     RECT  49.932 1.819 104.49 2.011 ;
     RECT  105.3 1.819 111.078 2.011 ;
     RECT  49.932 2.011 111.078 2.101 ;
     RECT  4.68 1.723 6.966 2.191 ;
     RECT  9.252 1.771 17.154 2.191 ;
     RECT  17.892 1.723 49.194 2.191 ;
     RECT  4.356 2.191 6.966 2.227 ;
     RECT  7.74 1.723 8.406 2.227 ;
     RECT  4.356 2.227 8.406 2.263 ;
     RECT  9.252 2.191 49.194 2.263 ;
     RECT  49.932 2.101 111.15 2.263 ;
     RECT  4.284 2.263 8.406 2.299 ;
     RECT  9.252 2.263 111.15 2.299 ;
     RECT  2.415 2.143 2.505 2.413 ;
     RECT  4.032 2.299 111.15 2.497 ;
     RECT  4.032 2.497 111.402 2.641 ;
     RECT  4.032 2.641 111.726 3.343 ;
     RECT  3.852 3.343 111.726 3.389 ;
     RECT  3.96 3.389 111.726 3.403 ;
     RECT  3.96 3.403 111.762 3.946 ;
     RECT  3.96 3.946 111.798 3.955 ;
     RECT  3.96 3.955 112.194 4.153 ;
     RECT  2.415 2.413 2.697 4.459 ;
     RECT  3.528 4.153 112.194 4.459 ;
     RECT  2.415 4.459 112.194 4.523 ;
     RECT  3.924 4.523 112.194 5.225 ;
     RECT  4.5 5.225 112.194 5.261 ;
     RECT  4.5 5.261 111.87 5.729 ;
     RECT  4.608 5.729 111.87 6.275 ;
     RECT  4.644 6.275 111.87 6.305 ;
     RECT  4.68 6.305 111.87 6.809 ;
     RECT  4.68 6.809 111.798 7.421 ;
     RECT  4.788 7.421 111.798 7.529 ;
     RECT  71.532 7.529 111.798 7.619 ;
     RECT  71.532 7.619 111.582 7.961 ;
     RECT  4.788 7.529 70.65 8.311 ;
     RECT  71.532 7.961 111.186 8.311 ;
     RECT  4.788 8.311 111.186 8.465 ;
     RECT  4.788 8.465 110.862 8.477 ;
     RECT  4.788 8.477 27.054 8.851 ;
     RECT  4.752 8.851 27.054 8.909 ;
     RECT  28.08 8.477 110.862 8.909 ;
     RECT  96.3 8.909 110.862 8.969 ;
     RECT  4.788 8.909 27.054 9.239 ;
     RECT  28.08 8.909 95.526 9.239 ;
     RECT  11.808 9.239 27.054 9.275 ;
     RECT  96.3 8.969 110.79 9.311 ;
     RECT  28.08 9.239 90.63 9.545 ;
     RECT  28.08 9.545 90.594 9.661 ;
     RECT  11.808 9.275 18.897 9.689 ;
     RECT  19.728 9.275 27.054 9.859 ;
     RECT  28.044 9.661 90.594 9.859 ;
     RECT  19.728 9.859 90.594 9.959 ;
     RECT  11.808 9.689 15.138 10.085 ;
     RECT  96.444 9.311 110.79 10.085 ;
     RECT  28.044 9.959 90.594 10.121 ;
     RECT  4.788 9.239 10.89 10.201 ;
     RECT  11.808 10.085 15.066 10.201 ;
     RECT  15.915 9.689 18.897 10.201 ;
     RECT  19.728 9.959 27.054 10.201 ;
     RECT  91.368 9.239 95.526 10.201 ;
     RECT  73.692 10.121 90.594 10.391 ;
     RECT  15.915 10.201 27.054 10.471 ;
     RECT  15.804 10.471 27.054 10.661 ;
     RECT  91.368 10.201 95.634 10.741 ;
     RECT  96.552 10.085 110.79 10.741 ;
     RECT  0.216 10.795 0.234 10.931 ;
     RECT  4.788 10.201 15.066 11.011 ;
     RECT  15.804 10.661 21.762 11.011 ;
     RECT  79.704 10.391 90.594 11.011 ;
     RECT  91.368 10.741 95.778 11.011 ;
     RECT  96.552 10.741 110.898 11.011 ;
     RECT  4.788 11.011 21.762 11.039 ;
     RECT  28.044 10.121 72.897 11.101 ;
     RECT  22.536 10.661 27.054 11.227 ;
     RECT  28.044 11.101 72.954 11.227 ;
     RECT  22.536 11.227 72.954 11.261 ;
     RECT  73.692 10.391 78.966 11.281 ;
     RECT  79.704 11.011 110.898 11.281 ;
     RECT  22.536 11.261 56.754 11.399 ;
     RECT  57.636 11.261 72.954 11.435 ;
     RECT  73.692 11.281 111.15 11.435 ;
     RECT  19.8 11.039 21.762 11.551 ;
     RECT  57.636 11.435 60.606 11.669 ;
     RECT  61.524 11.435 72.954 11.669 ;
     RECT  68.796 11.669 72.954 11.749 ;
     RECT  73.692 11.435 95.778 11.749 ;
     RECT  4.788 11.039 18.897 11.821 ;
     RECT  19.8 11.551 21.798 11.821 ;
     RECT  22.536 11.399 27.054 11.821 ;
     RECT  28.044 11.399 56.754 11.849 ;
     RECT  45.396 11.849 56.754 11.939 ;
     RECT  4.788 11.821 27.054 11.975 ;
     RECT  28.044 11.849 44.586 11.975 ;
     RECT  68.796 11.749 95.778 11.975 ;
     RECT  68.904 11.975 95.778 11.981 ;
     RECT  45.432 11.939 56.754 12.209 ;
     RECT  96.588 11.435 110.697 12.209 ;
     RECT  28.044 11.975 44.55 12.353 ;
     RECT  25.164 11.975 27.054 12.361 ;
     RECT  28.044 12.353 44.514 12.361 ;
     RECT  61.524 11.669 67.842 12.361 ;
     RECT  25.164 12.361 44.514 12.721 ;
     RECT  68.904 11.981 72.954 12.721 ;
     RECT  73.692 11.981 95.778 12.721 ;
     RECT  68.904 12.721 95.778 12.785 ;
     RECT  25.056 12.721 44.514 12.893 ;
     RECT  85.248 12.785 95.778 12.901 ;
     RECT  96.588 12.209 102.597 12.901 ;
     RECT  61.488 12.361 67.842 12.929 ;
     RECT  57.672 11.669 60.606 13.019 ;
     RECT  4.788 11.975 24.297 13.091 ;
     RECT  85.248 12.901 102.597 13.171 ;
     RECT  103.356 12.209 110.697 13.171 ;
     RECT  61.488 12.929 67.626 13.289 ;
     RECT  68.904 12.785 84.438 13.441 ;
     RECT  25.056 12.893 41.67 13.559 ;
     RECT  57.672 13.019 60.534 13.559 ;
     RECT  45.468 12.209 56.754 13.631 ;
     RECT  4.788 13.091 21.762 13.661 ;
     RECT  68.724 13.441 84.438 13.661 ;
     RECT  47.808 13.631 56.754 14.071 ;
     RECT  85.248 13.171 110.697 14.099 ;
     RECT  57.744 13.559 60.534 14.171 ;
     RECT  47.808 14.071 56.862 14.243 ;
     RECT  47.808 14.243 56.79 14.675 ;
     RECT  101.844 14.099 110.697 14.711 ;
     RECT  25.2 13.559 41.67 14.819 ;
     RECT  22.536 13.091 24.297 15.835 ;
     RECT  25.2 14.819 33.858 15.835 ;
     RECT  22.536 15.835 33.858 15.965 ;
     RECT  47.808 14.675 56.754 17.645 ;
     RECT  103.428 14.711 110.697 18.797 ;
     RECT  25.38 15.965 33.858 18.845 ;
     RECT  34.596 14.819 41.67 18.845 ;
     RECT  2.415 4.523 2.697 19.187 ;
     RECT  25.38 18.845 26.997 19.187 ;
     RECT  52.956 17.645 56.754 19.187 ;
     RECT  61.488 13.289 67.554 19.187 ;
     RECT  69.372 13.661 84.438 19.187 ;
     RECT  85.248 14.099 101.07 19.187 ;
     RECT  103.536 18.797 110.697 19.187 ;
     RECT  54.54 19.187 56.754 19.435 ;
     RECT  101.844 14.711 102.597 19.435 ;
     RECT  2.415 19.187 2.505 19.457 ;
     RECT  4.788 13.661 14.886 19.457 ;
     RECT  22.536 15.965 24.498 19.457 ;
     RECT  25.38 19.187 26.805 19.457 ;
     RECT  28.044 18.845 33.858 19.457 ;
     RECT  37.515 18.845 41.67 19.457 ;
     RECT  47.808 17.645 52.146 19.457 ;
     RECT  52.956 19.187 53.805 19.457 ;
     RECT  57.816 14.171 60.534 19.457 ;
     RECT  61.488 19.187 64.605 19.457 ;
     RECT  65.376 19.187 67.554 19.457 ;
     RECT  69.372 19.187 72.705 19.457 ;
     RECT  85.248 19.187 97.005 19.457 ;
     RECT  103.536 19.187 110.505 19.457 ;
     RECT  15.876 13.661 21.762 19.483 ;
     RECT  54.54 19.435 56.79 19.565 ;
     RECT  61.488 19.457 64.206 19.565 ;
     RECT  94.608 19.457 96.822 19.565 ;
     RECT  101.844 19.435 102.726 19.565 ;
     RECT  103.536 19.457 109.926 19.565 ;
     RECT  15.804 19.483 21.762 19.613 ;
     RECT  28.044 19.457 32.022 19.613 ;
     RECT  42.444 12.893 44.514 19.661 ;
     RECT  24.48 19.457 24.498 19.901 ;
     RECT  94.644 19.565 96.822 19.949 ;
     RECT  4.788 19.457 10.206 20.573 ;
     RECT  10.944 19.457 14.886 20.573 ;
     RECT  15.876 19.613 21.762 20.573 ;
     RECT  22.536 19.457 23.49 20.573 ;
     RECT  25.38 19.457 26.298 20.573 ;
     RECT  28.044 19.613 31.698 20.573 ;
     RECT  32.796 19.457 33.858 20.573 ;
     RECT  34.596 18.845 36.774 20.573 ;
     RECT  37.944 19.457 39.51 20.573 ;
     RECT  40.896 19.457 41.67 20.573 ;
     RECT  42.444 19.661 42.894 20.573 ;
     RECT  43.992 19.661 44.514 20.573 ;
     RECT  45.468 13.631 46.926 20.573 ;
     RECT  47.808 19.457 50.634 20.573 ;
     RECT  51.66 19.457 52.146 20.573 ;
     RECT  52.956 19.457 53.298 20.573 ;
     RECT  54.54 19.565 56.754 20.573 ;
     RECT  57.816 19.457 58.446 20.573 ;
     RECT  59.868 19.457 60.534 20.573 ;
     RECT  61.488 19.565 61.794 20.573 ;
     RECT  62.568 19.565 64.206 20.573 ;
     RECT  65.376 19.457 66.618 20.573 ;
     RECT  67.536 19.457 67.554 20.573 ;
     RECT  69.372 19.457 69.39 20.573 ;
     RECT  70.236 19.457 71.982 20.573 ;
     RECT  73.584 19.187 84.438 20.573 ;
     RECT  85.248 19.457 85.986 20.573 ;
     RECT  86.832 19.457 91.206 20.573 ;
     RECT  91.944 19.457 93.762 20.573 ;
     RECT  95.184 19.949 96.822 20.573 ;
     RECT  97.776 19.187 101.07 20.573 ;
     RECT  101.844 19.565 101.934 20.573 ;
     RECT  103.536 19.565 107.19 20.573 ;
     RECT  5.58 20.573 6.21 20.621 ;
     RECT  7.668 20.573 7.794 20.621 ;
     RECT  9.648 20.573 9.666 20.621 ;
     RECT  12.996 20.573 13.014 20.621 ;
     RECT  14.472 20.573 14.742 20.621 ;
     RECT  17.568 20.573 17.838 20.621 ;
     RECT  20.268 20.573 20.286 20.621 ;
     RECT  21.744 20.573 21.762 20.621 ;
     RECT  22.824 20.573 22.842 20.621 ;
     RECT  25.956 20.573 26.298 20.621 ;
     RECT  28.044 20.573 28.062 20.621 ;
     RECT  30.168 20.573 30.186 20.621 ;
     RECT  33.552 20.573 33.606 20.621 ;
     RECT  35.784 20.573 35.802 20.621 ;
     RECT  38.268 20.573 38.574 20.621 ;
     RECT  39.492 20.573 39.51 20.621 ;
     RECT  44.496 20.573 44.514 20.621 ;
     RECT  46.692 20.573 46.71 20.621 ;
     RECT  53.28 20.573 53.298 20.621 ;
     RECT  54.576 20.573 54.666 20.621 ;
     RECT  55.8 20.573 56.214 20.621 ;
     RECT  57.996 20.573 58.014 20.621 ;
     RECT  59.976 20.573 59.994 20.621 ;
     RECT  63.072 20.573 64.206 20.621 ;
     RECT  65.484 20.573 66.258 20.621 ;
     RECT  71.46 20.573 71.478 20.621 ;
     RECT  76.644 20.573 76.662 20.621 ;
     RECT  79.2 20.573 80.19 20.621 ;
     RECT  81.18 20.573 82.674 20.621 ;
     RECT  84.276 20.573 84.438 20.621 ;
     RECT  85.248 20.573 85.806 20.621 ;
     RECT  87.516 20.573 88.398 20.621 ;
     RECT  90.432 20.573 91.098 20.621 ;
     RECT  92.16 20.573 92.538 20.621 ;
     RECT  93.744 20.573 93.762 20.621 ;
     RECT  96.588 20.573 96.822 20.621 ;
     RECT  98.748 20.573 98.766 20.621 ;
     RECT  100.296 20.573 100.638 20.621 ;
     RECT  101.844 20.573 101.862 20.621 ;
     RECT  104.688 20.573 104.778 20.621 ;
     RECT  105.732 20.573 106.758 20.621 ;
     RECT  108.252 19.565 109.926 20.621 ;
     RECT  7.668 20.621 7.686 20.669 ;
     RECT  14.724 20.621 14.742 20.669 ;
     RECT  17.82 20.621 17.838 20.669 ;
     RECT  31.032 20.573 31.302 20.669 ;
     RECT  45.468 20.573 45.486 20.669 ;
     RECT  54.576 20.621 54.594 20.669 ;
     RECT  55.8 20.621 55.818 20.669 ;
     RECT  61.488 20.573 61.506 20.669 ;
     RECT  64.188 20.621 64.206 20.669 ;
     RECT  80.172 20.621 80.19 20.669 ;
     RECT  84.42 20.621 84.438 20.669 ;
     RECT  87.516 20.621 87.93 20.669 ;
     RECT  96.588 20.621 96.606 20.669 ;
     RECT  100.296 20.621 100.602 20.669 ;
     RECT  104.688 20.621 104.706 20.669 ;
     RECT  108.828 20.621 108.846 20.669 ;
     RECT  109.8 20.621 109.818 20.669 ;
     RECT  6.12 20.621 6.21 20.717 ;
     RECT  33.552 20.621 33.57 20.717 ;
     RECT  87.912 20.669 87.93 20.717 ;
     RECT  100.584 20.669 100.602 20.717 ;
     RECT  106.308 20.621 106.326 20.717 ;
     RECT  6.192 20.717 6.21 20.765 ;
     RECT  31.284 20.669 31.302 21.389 ;
     RECT  93.996 21.355 94.014 21.485 ;
     RECT  102.168 21.355 102.186 21.485 ;
    LAYER M4 ;
     RECT  0.156 10.8 0.245 10.824 ;
     RECT  2.408 2.148 2.512 19.452 ;
     RECT  2.512 2.418 2.704 19.182 ;
     RECT  2.704 3.36 3.905 3.384 ;
     RECT  3.905 3.36 3.925 3.432 ;
     RECT  3.925 2.784 3.949 3.432 ;
     RECT  2.704 4.464 3.949 5.208 ;
     RECT  3.949 2.784 4.021 5.208 ;
     RECT  4.021 2.304 4.405 5.208 ;
     RECT  4.405 2.208 4.625 5.208 ;
     RECT  4.453 6.24 4.645 6.264 ;
     RECT  4.625 1.728 4.813 5.208 ;
     RECT  4.813 1.728 5.108 5.256 ;
     RECT  4.645 6.24 5.108 6.84 ;
     RECT  4.309 8.88 5.108 8.904 ;
     RECT  4.981 10.704 5.108 10.728 ;
     RECT  4.748 20.544 5.317 20.568 ;
     RECT  5.108 1.728 5.404 19.452 ;
     RECT  5.404 18.816 5.461 19.452 ;
     RECT  5.461 0.192 5.603 0.216 ;
     RECT  5.461 18.816 5.603 19.56 ;
     RECT  5.317 20.544 5.653 20.616 ;
     RECT  5.603 18.816 5.681 18.84 ;
     RECT  5.653 20.544 5.845 20.712 ;
     RECT  5.845 20.544 6.221 20.76 ;
     RECT  6.221 20.544 6.227 20.616 ;
     RECT  5.404 1.728 6.469 5.592 ;
     RECT  6.469 1.728 6.553 6.312 ;
     RECT  6.517 7.392 6.721 7.416 ;
     RECT  5.404 8.544 6.721 8.904 ;
     RECT  6.721 7.392 7.189 8.904 ;
     RECT  7.189 7.392 7.297 9.672 ;
     RECT  6.553 1.728 7.573 5.832 ;
     RECT  7.297 6.864 7.573 9.672 ;
     RECT  6.227 20.544 7.657 20.568 ;
     RECT  7.573 1.728 7.808 9.672 ;
     RECT  7.333 11.136 7.808 11.16 ;
     RECT  6.661 13.632 7.808 13.656 ;
     RECT  6.853 18.768 7.808 18.792 ;
     RECT  7.657 20.544 7.907 20.664 ;
     RECT  7.808 1.728 7.912 19.452 ;
     RECT  8.005 0.288 8.101 0.312 ;
     RECT  7.912 1.728 8.104 19.182 ;
     RECT  8.101 0.192 8.243 0.312 ;
     RECT  8.104 1.728 8.243 8.376 ;
     RECT  8.104 9.696 8.531 11.4 ;
     RECT  7.907 20.544 9.028 20.568 ;
     RECT  8.531 10.272 9.107 11.4 ;
     RECT  8.104 12.528 9.137 12.552 ;
     RECT  8.104 15.936 9.209 15.96 ;
     RECT  8.243 3.36 9.317 8.376 ;
     RECT  8.243 1.728 9.377 2.328 ;
     RECT  9.317 3.36 9.377 7.416 ;
     RECT  9.028 20.544 9.677 20.616 ;
     RECT  9.107 11.376 10.069 11.4 ;
     RECT  10.069 10.704 10.213 11.4 ;
     RECT  9.397 12.912 10.213 12.936 ;
     RECT  9.565 8.544 10.309 8.568 ;
     RECT  9.541 18.816 10.309 18.84 ;
     RECT  10.309 18.816 10.357 19.56 ;
     RECT  9.677 20.544 10.357 20.568 ;
     RECT  9.377 1.728 10.508 7.416 ;
     RECT  10.309 8.544 10.508 9 ;
     RECT  10.213 10.704 10.508 12.936 ;
     RECT  10.357 18.816 10.508 20.568 ;
     RECT  10.508 1.728 10.595 20.568 ;
     RECT  10.595 1.728 10.612 19.452 ;
     RECT  10.612 1.728 10.804 19.182 ;
     RECT  10.804 1.728 10.937 7.416 ;
     RECT  10.804 8.976 10.937 10.248 ;
     RECT  10.937 1.728 10.973 7.272 ;
     RECT  10.804 17.616 11.117 17.64 ;
     RECT  10.804 11.952 11.153 12.408 ;
     RECT  10.973 2.88 11.693 7.272 ;
     RECT  10.937 9.648 12.017 10.248 ;
     RECT  11.153 12.384 12.085 12.408 ;
     RECT  10.973 1.728 12.265 1.848 ;
     RECT  11.693 2.88 12.265 5.784 ;
     RECT  11.693 7.248 12.277 7.272 ;
     RECT  12.277 7.248 12.409 7.464 ;
     RECT  10.595 20.544 12.613 20.568 ;
     RECT  12.409 7.248 12.769 7.992 ;
     RECT  12.085 12.384 12.949 12.552 ;
     RECT  12.265 1.728 12.977 5.784 ;
     RECT  12.769 6.864 12.977 7.992 ;
     RECT  12.977 1.728 13.208 7.992 ;
     RECT  12.017 9.648 13.208 9.672 ;
     RECT  12.757 10.752 13.208 10.776 ;
     RECT  12.949 11.952 13.208 12.552 ;
     RECT  12.277 17.616 13.208 17.64 ;
     RECT  13.208 1.728 13.477 19.452 ;
     RECT  13.477 1.728 13.504 19.56 ;
     RECT  13.504 19.536 13.619 19.56 ;
     RECT  13.504 1.728 13.777 6.312 ;
     RECT  13.504 11.952 13.997 12.552 ;
     RECT  12.613 20.544 14.293 20.616 ;
     RECT  13.777 1.104 14.339 6.312 ;
     RECT  13.997 12.528 14.429 12.552 ;
     RECT  14.339 1.728 14.485 6.312 ;
     RECT  13.504 7.68 14.485 9.096 ;
     RECT  14.293 20.544 14.753 20.664 ;
     RECT  14.821 16.56 14.905 16.584 ;
     RECT  14.485 1.728 15.301 9.096 ;
     RECT  15.749 19.488 15.788 19.512 ;
     RECT  14.753 20.544 15.788 20.568 ;
     RECT  15.788 19.488 15.875 20.568 ;
     RECT  15.301 1.728 15.908 9.672 ;
     RECT  15.685 11.136 15.908 11.16 ;
     RECT  14.965 13.632 15.908 13.656 ;
     RECT  15.875 19.488 15.908 19.56 ;
     RECT  15.908 1.728 16.204 19.56 ;
     RECT  16.165 0.288 16.355 0.312 ;
     RECT  16.204 1.728 16.355 7.464 ;
     RECT  16.204 19.536 16.355 19.56 ;
     RECT  16.204 8.496 16.499 9.672 ;
     RECT  16.499 8.496 16.697 8.52 ;
     RECT  15.875 20.544 16.804 20.568 ;
     RECT  16.204 11.376 16.985 12.408 ;
     RECT  16.204 13.632 17.021 13.656 ;
     RECT  16.985 11.376 17.315 12.024 ;
     RECT  16.355 1.728 17.353 7.416 ;
     RECT  16.499 9.648 17.453 9.672 ;
     RECT  16.804 20.544 17.804 20.616 ;
     RECT  17.804 20.544 17.891 20.664 ;
     RECT  17.315 11.376 18.229 11.4 ;
     RECT  17.353 1.728 18.469 7.272 ;
     RECT  17.891 20.544 18.469 20.568 ;
     RECT  18.469 1.728 18.608 7.992 ;
     RECT  18.229 10.704 18.608 11.4 ;
     RECT  17.509 13.008 18.608 13.032 ;
     RECT  18.469 19.584 18.608 20.568 ;
     RECT  18.469 0.192 18.755 0.216 ;
     RECT  18.608 1.728 18.755 20.568 ;
     RECT  18.755 1.728 18.904 19.56 ;
     RECT  18.904 19.536 19.043 19.56 ;
     RECT  18.904 17.616 19.073 17.64 ;
     RECT  18.904 1.728 19.619 6.888 ;
     RECT  18.904 10.224 19.793 10.728 ;
     RECT  18.904 7.968 19.829 7.992 ;
     RECT  18.755 20.544 20.053 20.568 ;
     RECT  19.619 1.728 20.153 5.88 ;
     RECT  19.619 6.864 20.153 6.888 ;
     RECT  18.904 9.072 20.153 9.096 ;
     RECT  19.793 10.224 20.153 10.248 ;
     RECT  20.153 3.024 20.261 5.88 ;
     RECT  18.904 11.952 20.389 11.976 ;
     RECT  20.245 13.488 20.389 13.512 ;
     RECT  20.053 20.544 21.109 20.616 ;
     RECT  20.261 3.12 21.149 5.88 ;
     RECT  20.581 8.496 21.157 8.52 ;
     RECT  21.109 19.68 21.157 20.616 ;
     RECT  20.153 1.728 21.308 1.896 ;
     RECT  21.149 3.12 21.308 6.312 ;
     RECT  21.157 7.92 21.308 8.52 ;
     RECT  20.917 10.704 21.308 10.728 ;
     RECT  20.389 11.952 21.308 13.512 ;
     RECT  21.157 19.584 21.308 20.616 ;
     RECT  21.308 1.728 21.604 20.616 ;
     RECT  21.604 19.68 21.635 20.616 ;
     RECT  21.604 10.656 21.665 10.824 ;
     RECT  21.604 11.904 21.701 13.08 ;
     RECT  21.604 1.728 21.737 8.904 ;
     RECT  21.701 11.904 21.989 12.552 ;
     RECT  21.737 8.88 22.853 8.904 ;
     RECT  21.635 20.544 22.853 20.616 ;
     RECT  21.989 11.904 23.125 11.976 ;
     RECT  21.665 10.8 23.461 10.824 ;
     RECT  22.853 20.544 23.501 20.568 ;
     RECT  23.461 10.704 23.653 10.824 ;
     RECT  21.737 1.728 23.893 7.224 ;
     RECT  23.893 1.728 24.008 7.464 ;
     RECT  23.653 10.656 24.008 10.824 ;
     RECT  23.125 11.904 24.008 12.552 ;
     RECT  22.933 13.536 24.008 13.56 ;
     RECT  23.989 19.584 24.008 19.896 ;
     RECT  24.008 1.728 24.304 19.896 ;
     RECT  24.304 19.584 24.419 19.896 ;
     RECT  24.419 19.68 24.467 19.896 ;
     RECT  24.304 1.728 24.515 7.416 ;
     RECT  24.304 15.84 24.515 15.96 ;
     RECT  24.467 19.776 24.515 19.896 ;
     RECT  24.304 8.448 24.653 8.472 ;
     RECT  24.304 10.656 24.797 11.352 ;
     RECT  24.515 1.728 25.157 2.28 ;
     RECT  24.515 15.936 25.229 15.96 ;
     RECT  24.304 13.632 25.337 13.656 ;
     RECT  24.304 9.648 25.669 9.672 ;
     RECT  24.997 20.544 25.945 20.568 ;
     RECT  25.945 20.544 26.309 20.616 ;
     RECT  25.157 1.728 26.341 1.8 ;
     RECT  24.797 11.328 26.341 11.352 ;
     RECT  25.861 13.488 26.533 13.512 ;
     RECT  25.669 9.408 26.581 9.672 ;
     RECT  26.341 1.728 26.708 1.896 ;
     RECT  24.515 3.36 26.708 7.416 ;
     RECT  26.581 8.448 26.708 9.672 ;
     RECT  26.341 11.232 26.708 11.352 ;
     RECT  26.533 12.528 26.708 13.512 ;
     RECT  26.581 19.584 26.708 19.656 ;
     RECT  26.708 1.728 27.004 19.656 ;
     RECT  27.004 18.816 27.203 19.656 ;
     RECT  27.203 18.816 27.353 18.84 ;
     RECT  27.004 6.816 27.497 8.472 ;
     RECT  27.004 13.632 27.497 13.656 ;
     RECT  27.004 12.528 27.821 12.552 ;
     RECT  27.004 1.728 27.827 5.832 ;
     RECT  27.877 20.544 28.021 20.568 ;
     RECT  27.497 7.968 28.037 8.472 ;
     RECT  28.021 20.544 28.108 20.616 ;
     RECT  27.827 3.36 28.321 5.832 ;
     RECT  27.497 6.816 28.321 6.888 ;
     RECT  27.004 10.8 28.361 11.4 ;
     RECT  27.827 1.728 28.397 2.28 ;
     RECT  28.321 3.36 28.741 6.888 ;
     RECT  28.361 11.376 29.221 11.4 ;
     RECT  28.037 8.352 29.269 8.472 ;
     RECT  28.108 20.544 29.269 20.568 ;
     RECT  28.397 1.728 29.408 1.848 ;
     RECT  28.741 3.36 29.408 7.368 ;
     RECT  29.269 8.352 29.408 8.52 ;
     RECT  29.221 11.376 29.408 11.976 ;
     RECT  28.549 17.616 29.408 17.64 ;
     RECT  29.269 19.584 29.408 20.568 ;
     RECT  29.408 1.728 29.459 20.568 ;
     RECT  29.459 1.728 29.512 19.452 ;
     RECT  29.512 1.728 29.704 19.182 ;
     RECT  29.459 20.544 29.749 20.568 ;
     RECT  29.704 3.36 29.765 6.888 ;
     RECT  29.765 3.36 29.873 5.832 ;
     RECT  29.581 0.24 29.939 0.264 ;
     RECT  29.704 8.496 29.987 9.288 ;
     RECT  29.765 6.864 30.025 6.888 ;
     RECT  29.873 3.36 30.089 5.496 ;
     RECT  29.704 18.768 30.125 18.792 ;
     RECT  29.749 20.544 30.196 20.616 ;
     RECT  29.704 11.136 30.305 11.976 ;
     RECT  29.987 8.496 30.413 8.52 ;
     RECT  30.196 20.544 30.757 20.664 ;
     RECT  29.704 13.632 30.881 13.656 ;
     RECT  30.089 3.648 31.237 5.496 ;
     RECT  29.704 1.728 31.273 1.848 ;
     RECT  30.757 20.544 31.313 21.384 ;
     RECT  31.237 3.6 31.484 5.496 ;
     RECT  31.273 1.728 31.489 1.896 ;
     RECT  31.484 3.6 31.628 5.736 ;
     RECT  31.285 12.528 31.765 12.552 ;
     RECT  30.949 9.936 31.909 9.96 ;
     RECT  30.305 11.136 31.909 11.16 ;
     RECT  31.909 19.536 31.949 19.56 ;
     RECT  31.909 9.936 31.957 11.16 ;
     RECT  31.949 18.864 31.993 19.56 ;
     RECT  31.313 20.544 31.993 20.568 ;
     RECT  30.757 0.192 32.003 0.216 ;
     RECT  31.628 3.6 32.065 6.12 ;
     RECT  31.429 7.392 32.065 7.416 ;
     RECT  31.489 1.728 32.108 2.28 ;
     RECT  32.065 3.6 32.108 7.416 ;
     RECT  31.957 9.072 32.108 11.16 ;
     RECT  31.765 12.528 32.108 12.936 ;
     RECT  31.993 18.864 32.108 20.568 ;
     RECT  32.108 1.728 32.147 20.568 ;
     RECT  32.147 1.728 32.339 19.56 ;
     RECT  32.339 1.728 32.404 19.182 ;
     RECT  32.404 1.728 32.825 1.848 ;
     RECT  32.404 3.408 33.059 6.072 ;
     RECT  32.147 20.544 33.109 20.568 ;
     RECT  32.404 7.392 33.149 7.416 ;
     RECT  32.404 9.072 33.149 10.632 ;
     RECT  33.149 9.648 33.185 10.632 ;
     RECT  33.185 9.648 33.329 9.96 ;
     RECT  33.109 20.544 33.493 20.616 ;
     RECT  33.493 20.544 33.581 20.712 ;
     RECT  33.581 20.544 33.617 20.616 ;
     RECT  32.404 11.952 33.653 11.976 ;
     RECT  32.825 1.728 33.829 1.752 ;
     RECT  32.404 13.536 33.833 13.56 ;
     RECT  33.829 1.728 34.501 1.8 ;
     RECT  33.059 3.648 34.549 6.072 ;
     RECT  34.309 7.392 34.549 7.416 ;
     RECT  34.501 1.728 34.808 1.848 ;
     RECT  34.549 3.648 34.808 7.416 ;
     RECT  33.329 9.936 34.808 9.96 ;
     RECT  33.973 11.376 34.808 11.4 ;
     RECT  34.501 12.48 34.808 12.504 ;
     RECT  34.645 13.632 34.808 13.656 ;
     RECT  34.808 1.728 34.837 19.452 ;
     RECT  33.617 20.544 34.837 20.568 ;
     RECT  34.837 1.728 35.104 20.568 ;
     RECT  35.104 19.584 35.173 20.568 ;
     RECT  35.104 1.728 35.219 2.904 ;
     RECT  35.173 19.584 35.219 20.616 ;
     RECT  35.219 1.728 35.269 1.848 ;
     RECT  35.269 1.104 35.363 1.848 ;
     RECT  35.104 13.488 35.489 13.656 ;
     RECT  35.104 7.296 35.785 7.464 ;
     RECT  35.219 20.544 35.813 20.616 ;
     RECT  35.785 7.296 36.029 7.32 ;
     RECT  35.104 9.408 36.181 9.432 ;
     RECT  35.219 2.88 36.461 2.904 ;
     RECT  35.104 11.952 36.517 11.976 ;
     RECT  35.363 1.728 36.668 1.848 ;
     RECT  35.813 20.544 36.785 20.568 ;
     RECT  36.181 9.072 36.853 9.432 ;
     RECT  37.045 7.344 37.069 7.368 ;
     RECT  36.517 11.04 37.189 11.976 ;
     RECT  35.489 13.488 37.189 13.512 ;
     RECT  37.069 7.344 37.333 7.464 ;
     RECT  37.333 19.584 37.381 19.608 ;
     RECT  36.668 1.728 37.508 2.28 ;
     RECT  35.104 3.888 37.508 5.496 ;
     RECT  37.333 7.2 37.508 7.464 ;
     RECT  36.853 9.072 37.508 9.624 ;
     RECT  37.189 11.04 37.508 13.512 ;
     RECT  37.381 18.816 37.508 19.608 ;
     RECT  37.508 1.728 37.571 19.608 ;
     RECT  37.571 1.728 37.804 19.56 ;
     RECT  37.804 19.536 37.955 19.56 ;
     RECT  37.804 1.728 38.117 1.848 ;
     RECT  37.861 20.544 38.197 20.568 ;
     RECT  37.804 3.888 38.261 7.416 ;
     RECT  37.804 11.952 38.261 11.976 ;
     RECT  37.804 10.752 38.477 10.776 ;
     RECT  38.197 20.544 39.269 20.616 ;
     RECT  39.269 20.592 39.521 20.616 ;
     RECT  38.117 1.728 39.553 1.8 ;
     RECT  39.061 9.936 39.589 10.728 ;
     RECT  38.261 3.888 39.733 6.312 ;
     RECT  38.261 7.392 39.733 7.416 ;
     RECT  39.733 3.888 39.913 7.416 ;
     RECT  39.913 3.408 40.021 7.416 ;
     RECT  40.021 19.584 40.049 19.608 ;
     RECT  39.553 1.728 40.208 1.848 ;
     RECT  40.021 3.408 40.208 7.992 ;
     RECT  39.589 9.072 40.208 10.728 ;
     RECT  39.397 11.952 40.208 11.976 ;
     RECT  39.925 13.056 40.208 13.08 ;
     RECT  40.049 18.768 40.208 19.608 ;
     RECT  40.208 1.728 40.307 19.608 ;
     RECT  40.307 1.728 40.312 19.452 ;
     RECT  40.312 1.728 40.504 19.182 ;
     RECT  40.504 7.392 40.565 9.096 ;
     RECT  40.504 1.728 40.643 6.312 ;
     RECT  40.504 11.328 40.745 11.976 ;
     RECT  40.643 1.728 40.787 2.28 ;
     RECT  40.565 7.392 40.889 8.904 ;
     RECT  40.504 13.056 40.961 13.08 ;
     RECT  40.889 7.392 41.645 7.8 ;
     RECT  40.745 11.328 41.645 11.4 ;
     RECT  41.605 0.576 41.689 0.6 ;
     RECT  40.787 1.728 42.109 1.8 ;
     RECT  40.889 8.88 42.277 8.904 ;
     RECT  40.643 3.408 42.757 6.312 ;
     RECT  40.405 20.544 42.757 20.568 ;
     RECT  42.757 19.632 42.805 20.568 ;
     RECT  42.109 1.728 42.908 1.848 ;
     RECT  42.757 3.408 42.908 6.84 ;
     RECT  42.277 7.872 42.908 8.904 ;
     RECT  41.797 10.176 42.908 10.2 ;
     RECT  41.645 11.376 42.908 11.4 ;
     RECT  42.613 12.528 42.908 12.552 ;
     RECT  40.504 14.208 42.908 14.232 ;
     RECT  42.805 19.536 42.908 20.568 ;
     RECT  42.908 1.728 43.204 20.568 ;
     RECT  43.204 2.88 43.331 5.784 ;
     RECT  43.204 19.536 43.331 20.568 ;
     RECT  43.331 19.632 43.372 20.568 ;
     RECT  43.204 12.528 43.409 13.56 ;
     RECT  43.409 12.528 43.445 12.552 ;
     RECT  43.409 13.536 43.661 13.56 ;
     RECT  43.204 17.616 43.805 17.64 ;
     RECT  43.204 6.816 44.201 6.84 ;
     RECT  43.204 1.728 44.272 1.8 ;
     RECT  43.372 20.544 44.341 20.568 ;
     RECT  43.204 8.496 44.485 8.52 ;
     RECT  44.485 8.496 44.489 9.096 ;
     RECT  43.204 10.8 44.561 11.352 ;
     RECT  43.331 2.88 44.881 5.592 ;
     RECT  44.341 20.544 45.349 20.616 ;
     RECT  44.881 2.88 45.493 5.736 ;
     RECT  44.821 13.056 45.493 13.08 ;
     RECT  45.349 20.544 45.497 20.664 ;
     RECT  44.272 1.728 45.608 1.848 ;
     RECT  45.493 2.88 45.608 6.12 ;
     RECT  44.489 8.976 45.608 9.096 ;
     RECT  44.561 11.04 45.608 11.352 ;
     RECT  45.493 12.528 45.608 13.08 ;
     RECT  45.608 1.728 45.685 19.452 ;
     RECT  45.497 20.544 45.685 20.568 ;
     RECT  45.685 1.728 45.904 20.568 ;
     RECT  45.904 19.584 46.019 20.568 ;
     RECT  46.019 19.68 46.067 20.568 ;
     RECT  45.904 12.528 46.181 12.552 ;
     RECT  46.033 0.192 46.259 0.216 ;
     RECT  45.904 17.616 46.397 17.64 ;
     RECT  45.904 7.776 46.433 7.8 ;
     RECT  46.067 20.544 46.652 20.568 ;
     RECT  45.904 8.88 46.721 9.672 ;
     RECT  46.652 20.544 46.739 20.616 ;
     RECT  45.904 2.88 46.892 2.904 ;
     RECT  45.904 4.224 46.892 6.12 ;
     RECT  46.285 0.576 46.931 0.6 ;
     RECT  46.892 2.88 47.077 6.12 ;
     RECT  46.721 8.88 47.701 9 ;
     RECT  46.885 12.384 48.133 12.408 ;
     RECT  47.557 18.816 48.133 18.84 ;
     RECT  46.739 20.544 48.133 20.568 ;
     RECT  47.893 7.392 48.181 7.416 ;
     RECT  45.904 1.728 48.308 1.848 ;
     RECT  47.077 2.88 48.308 6.264 ;
     RECT  48.181 7.344 48.308 7.416 ;
     RECT  47.701 8.496 48.308 9 ;
     RECT  47.365 10.224 48.308 10.248 ;
     RECT  48.133 12.336 48.308 12.408 ;
     RECT  48.133 18.816 48.308 20.568 ;
     RECT  48.308 1.728 48.419 20.568 ;
     RECT  48.419 1.728 48.604 19.182 ;
     RECT  48.604 1.728 48.773 7.416 ;
     RECT  48.604 18.816 49.025 18.84 ;
     RECT  48.604 8.976 49.061 9 ;
     RECT  48.604 12.336 49.241 12.36 ;
     RECT  48.773 1.728 49.765 7.272 ;
     RECT  49.765 1.728 49.909 7.944 ;
     RECT  49.573 12.48 50.245 12.504 ;
     RECT  50.773 18.816 50.869 18.84 ;
     RECT  48.419 20.544 50.869 20.568 ;
     RECT  49.909 1.728 51.008 8.904 ;
     RECT  50.245 12.48 51.008 13.08 ;
     RECT  50.869 18.816 51.008 20.568 ;
     RECT  51.008 1.728 51.011 20.568 ;
     RECT  51.011 1.728 51.304 19.56 ;
     RECT  51.304 12.864 51.365 12.888 ;
     RECT  51.304 19.536 51.443 19.56 ;
     RECT  51.145 0.528 51.827 0.552 ;
     RECT  51.304 10.224 52.229 11.4 ;
     RECT  51.304 3.024 52.265 7.896 ;
     RECT  51.304 17.616 52.337 17.64 ;
     RECT  52.265 7.872 52.453 7.896 ;
     RECT  52.265 3.024 52.499 6.888 ;
     RECT  51.011 20.544 52.645 20.568 ;
     RECT  52.229 10.224 52.661 10.248 ;
     RECT  52.645 20.544 52.985 20.616 ;
     RECT  52.945 0.192 53.171 0.216 ;
     RECT  52.453 7.872 53.317 8.52 ;
     RECT  51.304 1.728 53.477 1.8 ;
     RECT  52.229 11.376 53.509 11.4 ;
     RECT  53.477 1.728 53.708 1.848 ;
     RECT  52.499 3.408 53.708 6.888 ;
     RECT  53.317 7.872 53.708 9.096 ;
     RECT  53.509 11.136 53.708 11.4 ;
     RECT  52.789 12.48 53.708 12.504 ;
     RECT  52.981 15.84 53.708 15.864 ;
     RECT  53.557 17.616 53.708 17.64 ;
     RECT  53.557 19.584 53.708 19.608 ;
     RECT  53.557 0.288 53.891 0.312 ;
     RECT  53.708 1.728 53.989 19.608 ;
     RECT  52.985 20.592 53.989 20.616 ;
     RECT  53.989 1.728 54.004 20.616 ;
     RECT  54.004 12.48 54.029 12.504 ;
     RECT  54.004 19.584 54.131 20.616 ;
     RECT  54.004 15.84 54.173 15.864 ;
     RECT  54.131 20.544 54.325 20.616 ;
     RECT  54.004 11.136 54.461 11.16 ;
     RECT  54.004 1.728 54.997 1.8 ;
     RECT  54.997 1.728 55.093 1.848 ;
     RECT  55.093 1.152 55.235 1.848 ;
     RECT  54.004 3.408 55.357 7.416 ;
     RECT  55.525 13.056 55.669 13.08 ;
     RECT  54.325 20.544 55.829 20.664 ;
     RECT  55.829 20.544 56.225 20.616 ;
     RECT  56.225 20.544 56.329 20.568 ;
     RECT  55.235 1.728 56.408 1.848 ;
     RECT  55.357 3.12 56.408 7.416 ;
     RECT  54.004 8.496 56.408 9.096 ;
     RECT  56.197 11.232 56.408 11.256 ;
     RECT  55.669 12.384 56.408 13.08 ;
     RECT  54.997 14.208 56.408 14.232 ;
     RECT  56.329 19.584 56.408 20.568 ;
     RECT  56.408 1.728 56.435 20.568 ;
     RECT  56.435 1.728 56.704 19.56 ;
     RECT  56.704 3.12 56.801 8.52 ;
     RECT  56.704 19.44 56.812 19.56 ;
     RECT  56.812 19.44 56.845 19.464 ;
     RECT  56.704 11.232 57.089 11.4 ;
     RECT  56.801 3.6 57.277 8.52 ;
     RECT  56.435 20.544 57.733 20.568 ;
     RECT  57.277 3.6 57.877 6.648 ;
     RECT  57.277 7.872 57.917 8.52 ;
     RECT  57.733 20.544 58.025 20.616 ;
     RECT  56.704 12.528 58.405 12.552 ;
     RECT  58.025 20.544 58.457 20.568 ;
     RECT  57.089 11.376 58.597 11.4 ;
     RECT  58.405 12.528 58.597 13.08 ;
     RECT  56.704 1.728 58.885 1.848 ;
     RECT  58.597 11.376 58.885 13.08 ;
     RECT  58.885 1.728 58.933 2.184 ;
     RECT  58.885 11.376 58.933 13.128 ;
     RECT  58.933 1.728 59.108 2.28 ;
     RECT  57.877 3.408 59.108 6.648 ;
     RECT  57.917 7.92 59.108 8.52 ;
     RECT  58.933 10.704 59.108 13.128 ;
     RECT  57.877 14.64 59.108 14.664 ;
     RECT  58.981 19.584 59.108 19.608 ;
     RECT  59.108 1.728 59.404 19.608 ;
     RECT  59.404 3.408 59.573 7.992 ;
     RECT  59.404 10.704 59.681 11.976 ;
     RECT  59.404 18.816 59.699 19.608 ;
     RECT  59.699 18.912 59.861 18.936 ;
     RECT  59.681 11.232 59.933 11.976 ;
     RECT  59.749 20.544 59.941 20.568 ;
     RECT  59.933 11.232 59.969 11.4 ;
     RECT  59.404 1.728 59.987 2.28 ;
     RECT  59.941 20.544 60.028 20.616 ;
     RECT  59.404 9.648 60.329 9.672 ;
     RECT  59.573 7.392 60.653 7.992 ;
     RECT  60.397 0.192 60.803 0.216 ;
     RECT  60.613 14.016 61.141 14.04 ;
     RECT  60.028 20.544 61.285 20.568 ;
     RECT  61.285 20.544 61.517 20.664 ;
     RECT  59.987 1.728 61.621 1.848 ;
     RECT  61.621 1.728 61.669 2.28 ;
     RECT  59.573 3.408 61.669 6.312 ;
     RECT  61.669 1.728 61.808 6.312 ;
     RECT  60.653 7.92 61.808 7.992 ;
     RECT  61.621 10.176 61.808 10.2 ;
     RECT  59.969 11.376 61.808 11.4 ;
     RECT  61.141 13.056 61.808 14.04 ;
     RECT  61.808 1.728 61.916 19.452 ;
     RECT  61.916 1.728 62.104 19.56 ;
     RECT  62.104 2.784 62.165 6.12 ;
     RECT  62.104 19.44 62.237 19.56 ;
     RECT  62.237 19.44 62.281 19.464 ;
     RECT  62.104 7.392 62.309 7.992 ;
     RECT  62.104 9.408 62.489 10.2 ;
     RECT  61.517 20.544 62.596 20.568 ;
     RECT  62.489 9.408 62.777 9.96 ;
     RECT  62.104 12.48 63.101 12.504 ;
     RECT  62.104 1.728 63.125 1.8 ;
     RECT  63.125 1.728 63.269 1.848 ;
     RECT  62.165 3.072 63.269 6.12 ;
     RECT  63.269 1.728 63.353 6.12 ;
     RECT  63.301 18.768 63.389 18.792 ;
     RECT  62.596 20.544 63.641 20.616 ;
     RECT  63.641 20.592 63.685 20.616 ;
     RECT  63.685 20.592 63.713 20.664 ;
     RECT  63.353 3.072 63.809 6.12 ;
     RECT  62.309 7.392 63.809 7.416 ;
     RECT  63.713 20.64 64.217 20.664 ;
     RECT  62.777 9.936 64.357 9.96 ;
     RECT  63.809 3.072 64.501 7.416 ;
     RECT  63.353 1.728 64.508 1.848 ;
     RECT  64.501 3.024 64.508 7.416 ;
     RECT  64.165 8.496 64.508 8.52 ;
     RECT  64.357 9.936 64.508 10.104 ;
     RECT  64.021 11.952 64.508 11.976 ;
     RECT  63.829 13.056 64.508 13.08 ;
     RECT  64.501 19.584 64.508 19.608 ;
     RECT  64.508 1.728 64.693 19.608 ;
     RECT  64.693 1.728 64.804 20.616 ;
     RECT  64.804 19.584 64.931 20.616 ;
     RECT  64.931 19.68 64.979 20.616 ;
     RECT  64.804 10.752 65.045 11.304 ;
     RECT  64.804 1.728 65.507 6.312 ;
     RECT  65.507 1.728 65.621 4.104 ;
     RECT  65.507 5.136 65.651 6.312 ;
     RECT  65.045 11.28 65.765 11.304 ;
     RECT  64.804 12.384 65.765 12.408 ;
     RECT  64.804 14.208 65.945 14.232 ;
     RECT  66.113 7.44 66.197 7.464 ;
     RECT  64.979 20.544 66.275 20.616 ;
     RECT  66.445 0.192 66.755 0.216 ;
     RECT  65.621 3.312 66.913 4.104 ;
     RECT  65.651 5.136 66.913 6.12 ;
     RECT  66.373 9.408 67.045 9.432 ;
     RECT  65.621 1.728 67.208 1.848 ;
     RECT  66.913 3.312 67.208 6.12 ;
     RECT  66.901 7.92 67.208 7.944 ;
     RECT  67.045 9.408 67.208 10.104 ;
     RECT  66.565 12.48 67.208 12.504 ;
     RECT  66.709 17.616 67.208 17.64 ;
     RECT  67.208 1.728 67.381 19.452 ;
     RECT  67.381 1.728 67.504 19.56 ;
     RECT  66.275 20.544 67.565 20.568 ;
     RECT  67.504 7.344 67.601 7.944 ;
     RECT  67.504 19.536 67.667 19.56 ;
     RECT  67.504 9.072 67.889 10.824 ;
     RECT  67.504 3.312 67.925 6.312 ;
     RECT  68.353 0.192 68.437 0.216 ;
     RECT  67.925 3.36 68.533 6.312 ;
     RECT  67.601 7.344 68.533 7.368 ;
     RECT  67.889 10.8 68.581 10.824 ;
     RECT  67.504 13.056 68.753 13.656 ;
     RECT  67.504 1.728 68.821 2.232 ;
     RECT  67.889 9.072 69.109 9.384 ;
     RECT  68.821 1.728 69.253 2.28 ;
     RECT  68.533 3.36 69.253 7.368 ;
     RECT  68.753 13.056 69.445 13.08 ;
     RECT  69.253 1.728 69.493 7.368 ;
     RECT  69.109 8.496 69.493 9.384 ;
     RECT  68.581 10.8 69.733 11.4 ;
     RECT  69.253 18.816 69.733 18.84 ;
     RECT  68.917 20.544 69.733 20.568 ;
     RECT  69.733 10.8 69.781 11.976 ;
     RECT  69.493 1.728 69.908 9.384 ;
     RECT  69.781 10.704 69.908 11.976 ;
     RECT  69.445 13.008 69.908 13.08 ;
     RECT  69.733 18.816 69.908 20.568 ;
     RECT  69.908 1.728 69.971 20.568 ;
     RECT  69.971 1.728 70.204 19.56 ;
     RECT  70.204 7.968 70.265 8.52 ;
     RECT  70.204 19.536 70.355 19.56 ;
     RECT  70.265 7.968 70.525 8.472 ;
     RECT  70.204 1.728 70.595 6.888 ;
     RECT  70.595 1.728 70.733 6.648 ;
     RECT  70.525 8.304 70.877 8.472 ;
     RECT  70.204 10.512 70.877 10.728 ;
     RECT  70.733 2.832 71.093 6.648 ;
     RECT  70.877 10.704 71.129 10.728 ;
     RECT  70.204 11.952 71.129 11.976 ;
     RECT  71.093 2.832 71.267 6.264 ;
     RECT  69.971 20.544 71.317 20.568 ;
     RECT  71.317 20.544 71.489 20.616 ;
     RECT  70.877 8.304 71.893 8.328 ;
     RECT  71.489 20.544 71.993 20.568 ;
     RECT  71.989 13.488 72.133 13.512 ;
     RECT  70.733 1.728 72.325 1.848 ;
     RECT  71.797 14.784 72.373 14.808 ;
     RECT  71.461 11.376 72.421 11.4 ;
     RECT  72.133 12.528 72.421 13.512 ;
     RECT  72.373 19.68 72.421 19.704 ;
     RECT  71.893 8.304 72.469 9.096 ;
     RECT  72.325 1.728 72.608 2.232 ;
     RECT  71.267 3.36 72.608 6.264 ;
     RECT  72.469 7.968 72.608 9.096 ;
     RECT  72.469 10.08 72.608 10.104 ;
     RECT  72.421 11.376 72.608 13.512 ;
     RECT  72.373 14.784 72.608 15.336 ;
     RECT  72.421 19.584 72.608 19.704 ;
     RECT  72.608 1.728 72.851 19.704 ;
     RECT  72.851 1.728 72.904 19.182 ;
     RECT  72.904 15.312 73.073 15.336 ;
     RECT  72.904 3.408 73.289 9.048 ;
     RECT  72.904 11.952 73.433 11.976 ;
     RECT  72.904 10.08 73.577 10.2 ;
     RECT  72.904 1.728 74.005 1.8 ;
     RECT  73.289 3.408 74.041 8.52 ;
     RECT  74.041 3.264 74.153 8.52 ;
     RECT  74.153 7.152 74.297 8.52 ;
     RECT  73.577 10.176 74.677 10.2 ;
     RECT  74.869 18.816 75.149 18.84 ;
     RECT  75.013 9.072 75.157 9.096 ;
     RECT  74.677 10.176 75.157 11.16 ;
     RECT  75.149 18.816 75.164 19.464 ;
     RECT  74.005 1.728 75.308 1.848 ;
     RECT  74.153 3.264 75.308 6.12 ;
     RECT  74.297 7.152 75.308 7.992 ;
     RECT  75.157 9.072 75.308 11.16 ;
     RECT  74.005 12.528 75.308 12.552 ;
     RECT  75.164 18.816 75.308 19.56 ;
     RECT  75.308 1.728 75.604 19.56 ;
     RECT  75.604 19.536 75.731 19.56 ;
     RECT  75.604 9.504 75.845 11.976 ;
     RECT  75.845 9.504 75.917 10.248 ;
     RECT  75.805 0.576 75.923 0.6 ;
     RECT  73.477 20.544 76.021 20.568 ;
     RECT  75.845 11.952 76.205 11.976 ;
     RECT  75.604 1.728 76.277 1.848 ;
     RECT  75.604 17.616 76.313 17.64 ;
     RECT  76.277 1.728 76.595 1.8 ;
     RECT  76.021 20.544 76.673 20.616 ;
     RECT  75.604 8.496 76.997 8.52 ;
     RECT  75.604 6.816 77.077 7.176 ;
     RECT  75.604 3.408 77.209 5.736 ;
     RECT  77.077 6.816 77.209 7.992 ;
     RECT  75.917 10.224 77.221 10.248 ;
     RECT  76.595 1.728 77.716 1.752 ;
     RECT  77.716 1.728 77.893 1.8 ;
     RECT  77.893 1.728 78.008 1.896 ;
     RECT  77.209 3.408 78.008 7.992 ;
     RECT  77.221 9.408 78.008 10.248 ;
     RECT  77.413 11.232 78.008 11.256 ;
     RECT  76.741 13.056 78.008 13.08 ;
     RECT  77.557 18.192 78.008 18.216 ;
     RECT  78.008 1.728 78.085 19.452 ;
     RECT  76.673 20.544 78.085 20.568 ;
     RECT  78.085 1.728 78.304 20.568 ;
     RECT  78.304 1.728 78.365 2.04 ;
     RECT  78.304 19.584 78.419 20.568 ;
     RECT  78.304 7.152 78.689 7.416 ;
     RECT  78.419 20.544 78.757 20.568 ;
     RECT  78.304 11.232 78.797 11.256 ;
     RECT  78.304 10.224 79.265 10.248 ;
     RECT  78.365 1.728 79.621 1.848 ;
     RECT  79.621 1.728 79.765 1.896 ;
     RECT  78.304 3.12 79.765 6.024 ;
     RECT  78.689 7.152 79.765 7.176 ;
     RECT  79.765 1.728 79.813 6.024 ;
     RECT  79.765 7.152 79.813 7.368 ;
     RECT  78.757 20.544 80.101 20.616 ;
     RECT  80.101 20.544 80.201 20.664 ;
     RECT  79.285 9.408 80.581 9.432 ;
     RECT  80.549 19.488 80.588 19.512 ;
     RECT  80.201 20.544 80.588 20.616 ;
     RECT  80.588 19.488 80.675 20.616 ;
     RECT  79.813 1.728 80.708 7.368 ;
     RECT  80.581 8.496 80.708 9.432 ;
     RECT  79.429 11.04 80.708 11.064 ;
     RECT  78.304 13.632 80.708 13.656 ;
     RECT  80.708 1.728 80.812 19.452 ;
     RECT  80.812 1.728 81.004 19.182 ;
     RECT  81.004 1.728 81.322 6.12 ;
     RECT  81.004 13.488 81.389 13.656 ;
     RECT  81.322 1.728 81.685 1.848 ;
     RECT  81.004 7.152 81.749 7.368 ;
     RECT  81.004 8.544 81.793 8.568 ;
     RECT  81.004 11.376 82.165 11.4 ;
     RECT  81.389 13.488 82.217 13.512 ;
     RECT  81.322 2.832 82.249 6.12 ;
     RECT  81.749 7.152 82.249 7.176 ;
     RECT  82.165 10.8 82.325 11.4 ;
     RECT  80.675 20.544 82.729 20.616 ;
     RECT  81.685 1.728 82.828 1.752 ;
     RECT  82.325 10.8 82.837 10.824 ;
     RECT  82.309 12.48 82.981 12.504 ;
     RECT  82.249 2.832 83.173 7.176 ;
     RECT  82.652 8.736 83.269 8.76 ;
     RECT  83.249 19.44 83.276 19.464 ;
     RECT  82.828 1.728 83.285 1.8 ;
     RECT  83.173 2.832 83.285 7.416 ;
     RECT  83.276 19.44 83.363 19.56 ;
     RECT  83.285 1.728 83.408 7.416 ;
     RECT  83.269 8.496 83.408 8.76 ;
     RECT  82.837 10.752 83.408 10.824 ;
     RECT  82.981 11.952 83.408 12.504 ;
     RECT  83.363 19.44 83.408 19.452 ;
     RECT  83.408 1.728 83.512 19.452 ;
     RECT  83.512 1.728 83.704 19.182 ;
     RECT  83.704 11.952 83.765 12.936 ;
     RECT  82.729 20.544 83.845 20.568 ;
     RECT  83.845 20.544 84.181 20.616 ;
     RECT  83.704 3.984 84.305 8.52 ;
     RECT  84.181 20.544 84.449 20.664 ;
     RECT  83.704 1.728 84.733 2.904 ;
     RECT  84.733 1.728 84.841 2.952 ;
     RECT  84.305 3.984 84.841 6.216 ;
     RECT  84.305 7.968 84.845 8.52 ;
     RECT  84.841 1.728 85.477 6.216 ;
     RECT  85.093 10.8 85.525 10.824 ;
     RECT  85.477 1.728 85.633 6.312 ;
     RECT  83.765 12.912 85.717 12.936 ;
     RECT  85.045 18.816 86.053 18.84 ;
     RECT  84.449 20.544 86.053 20.616 ;
     RECT  85.633 1.728 86.108 6.648 ;
     RECT  84.845 7.968 86.108 7.992 ;
     RECT  84.709 9.648 86.108 9.672 ;
     RECT  85.525 10.8 86.108 11.256 ;
     RECT  85.717 12.912 86.108 13.08 ;
     RECT  86.053 18.816 86.108 20.616 ;
     RECT  86.108 1.728 86.404 20.616 ;
     RECT  86.404 7.968 86.579 8.52 ;
     RECT  86.404 19.536 86.579 20.616 ;
     RECT  86.579 19.536 86.627 19.56 ;
     RECT  86.579 8.496 86.897 8.52 ;
     RECT  86.404 10.224 86.969 10.248 ;
     RECT  86.404 1.728 87.155 6.648 ;
     RECT  87.155 3.312 87.244 6.648 ;
     RECT  86.579 20.544 87.397 20.616 ;
     RECT  87.397 20.544 87.589 20.664 ;
     RECT  86.404 13.056 87.733 13.512 ;
     RECT  87.589 20.544 87.941 20.712 ;
     RECT  87.244 3.408 88.172 6.648 ;
     RECT  88.172 3.408 88.213 6.696 ;
     RECT  87.941 20.544 88.451 20.616 ;
     RECT  88.213 3.408 88.693 7.56 ;
     RECT  88.451 20.544 88.693 20.568 ;
     RECT  87.155 1.728 88.808 2.328 ;
     RECT  88.693 3.408 88.808 7.992 ;
     RECT  88.261 11.952 88.808 11.976 ;
     RECT  87.733 13.056 88.808 13.656 ;
     RECT  88.693 19.584 88.808 20.568 ;
     RECT  88.808 1.728 88.835 20.568 ;
     RECT  88.835 1.728 89.104 19.56 ;
     RECT  89.104 18.816 89.267 19.56 ;
     RECT  89.104 11.376 89.273 11.976 ;
     RECT  89.267 18.816 89.489 18.84 ;
     RECT  89.104 9.648 89.597 9.672 ;
     RECT  89.104 1.728 90.133 1.848 ;
     RECT  88.835 20.544 90.133 20.568 ;
     RECT  89.104 3.408 90.236 6.648 ;
     RECT  90.133 1.728 90.277 2.28 ;
     RECT  90.236 3.408 90.277 6.744 ;
     RECT  89.104 7.968 90.277 7.992 ;
     RECT  90.277 1.728 90.332 6.744 ;
     RECT  90.332 1.728 90.373 6.84 ;
     RECT  90.277 7.968 90.373 8.232 ;
     RECT  89.273 11.376 90.425 11.4 ;
     RECT  90.373 1.728 90.613 8.232 ;
     RECT  90.133 20.544 91.381 20.616 ;
     RECT  90.613 1.728 91.508 9.096 ;
     RECT  90.805 10.176 91.508 10.2 ;
     RECT  91.141 12.48 91.508 12.504 ;
     RECT  90.469 13.632 91.508 13.656 ;
     RECT  91.381 19.584 91.508 20.616 ;
     RECT  91.508 1.728 91.523 20.616 ;
     RECT  91.523 1.728 91.804 19.56 ;
     RECT  91.804 1.728 91.865 9.144 ;
     RECT  91.804 10.176 91.865 10.2 ;
     RECT  91.804 18.816 91.955 19.56 ;
     RECT  91.865 1.728 92.053 6.888 ;
     RECT  92.053 1.728 92.243 6.84 ;
     RECT  91.804 12.48 92.261 12.504 ;
     RECT  91.865 7.92 92.297 9.144 ;
     RECT  91.955 18.816 92.333 18.84 ;
     RECT  92.243 1.728 92.579 6.36 ;
     RECT  92.297 7.92 93.301 9.048 ;
     RECT  91.523 20.544 93.395 20.616 ;
     RECT  92.579 1.728 93.548 6.312 ;
     RECT  93.301 7.632 93.589 9.048 ;
     RECT  93.589 7.632 93.685 9.144 ;
     RECT  93.395 20.592 93.773 20.616 ;
     RECT  93.548 1.728 93.949 6.36 ;
     RECT  93.685 7.632 93.949 9.384 ;
     RECT  93.941 21.36 94.025 21.48 ;
     RECT  94.025 21.36 94.067 21.384 ;
     RECT  93.877 11.232 94.069 11.256 ;
     RECT  93.949 1.728 94.208 9.384 ;
     RECT  94.069 11.232 94.208 11.976 ;
     RECT  93.157 13.056 94.208 13.08 ;
     RECT  94.069 19.584 94.208 19.608 ;
     RECT  94.208 1.728 94.357 19.608 ;
     RECT  94.357 1.728 94.504 19.944 ;
     RECT  94.504 1.728 94.601 9.384 ;
     RECT  94.504 18.768 94.637 19.944 ;
     RECT  94.504 17.616 94.673 17.64 ;
     RECT  94.637 19.92 94.673 19.944 ;
     RECT  94.637 18.768 94.684 18.888 ;
     RECT  94.069 0.288 94.883 0.312 ;
     RECT  94.504 11.232 95.213 11.976 ;
     RECT  95.213 11.376 95.429 11.976 ;
     RECT  94.601 1.728 95.681 8.904 ;
     RECT  95.749 13.104 95.893 13.128 ;
     RECT  95.681 1.728 95.933 2.712 ;
     RECT  95.029 20.544 96.421 20.568 ;
     RECT  96.421 20.544 96.565 20.616 ;
     RECT  96.565 20.544 96.652 20.664 ;
     RECT  95.681 3.888 96.757 8.904 ;
     RECT  96.652 20.544 96.833 20.616 ;
     RECT  96.833 20.544 96.901 20.568 ;
     RECT  95.933 1.728 96.908 2.328 ;
     RECT  96.757 3.888 96.908 9.624 ;
     RECT  95.429 11.376 96.908 11.4 ;
     RECT  95.893 13.104 96.908 13.656 ;
     RECT  96.901 19.584 96.908 20.568 ;
     RECT  96.908 1.728 97.204 20.568 ;
     RECT  97.204 18.816 97.427 20.568 ;
     RECT  97.204 1.728 97.475 11.4 ;
     RECT  97.427 18.816 97.481 18.84 ;
     RECT  97.204 12.528 97.517 12.552 ;
     RECT  97.475 1.728 97.805 10.296 ;
     RECT  97.805 8.448 98.051 10.296 ;
     RECT  98.051 8.448 98.525 9.96 ;
     RECT  97.427 20.544 98.732 20.568 ;
     RECT  98.732 20.544 98.819 20.616 ;
     RECT  97.805 1.728 98.845 7.464 ;
     RECT  97.475 11.376 99.1 11.4 ;
     RECT  99.1 11.328 99.301 11.4 ;
     RECT  98.819 20.544 99.493 20.568 ;
     RECT  98.845 1.728 99.608 7.992 ;
     RECT  98.525 9.024 99.608 9.96 ;
     RECT  99.301 11.232 99.608 11.4 ;
     RECT  98.581 14.208 99.608 14.232 ;
     RECT  99.493 19.584 99.608 20.568 ;
     RECT  99.608 1.728 99.683 20.568 ;
     RECT  99.683 1.728 99.712 19.452 ;
     RECT  99.712 1.728 99.904 19.182 ;
     RECT  99.904 11.232 99.929 11.256 ;
     RECT  99.683 20.544 99.973 20.568 ;
     RECT  99.973 20.544 100.117 20.616 ;
     RECT  99.904 9.024 100.289 9.624 ;
     RECT  100.117 20.544 100.453 20.664 ;
     RECT  100.289 9.6 100.613 9.624 ;
     RECT  100.453 20.544 100.613 20.712 ;
     RECT  99.904 15.36 100.937 15.384 ;
     RECT  99.904 7.68 100.969 7.752 ;
     RECT  99.904 1.728 101.113 6.408 ;
     RECT  100.969 7.392 101.113 7.752 ;
     RECT  101.113 1.728 101.653 7.752 ;
     RECT  101.317 11.232 101.845 11.256 ;
     RECT  100.613 20.544 101.945 20.616 ;
     RECT  101.845 10.704 102.085 11.256 ;
     RECT  101.948 18.816 102.085 18.84 ;
     RECT  101.653 1.728 102.133 8.52 ;
     RECT  100.981 9.648 102.133 9.672 ;
     RECT  102.113 21.36 102.197 21.48 ;
     RECT  102.197 21.36 102.227 21.384 ;
     RECT  102.133 1.728 102.308 9.672 ;
     RECT  102.085 10.704 102.308 11.976 ;
     RECT  102.085 18.816 102.308 19.608 ;
     RECT  102.308 1.728 102.371 19.608 ;
     RECT  102.371 1.728 102.604 19.56 ;
     RECT  102.604 18.768 102.748 19.56 ;
     RECT  102.604 1.728 102.773 9.144 ;
     RECT  102.748 18.768 102.781 19.464 ;
     RECT  102.773 9.072 102.881 9.144 ;
     RECT  102.881 9.12 103.187 9.144 ;
     RECT  102.781 18.768 103.457 18.792 ;
     RECT  102.773 1.728 103.493 7.992 ;
     RECT  103.493 1.728 103.817 7.896 ;
     RECT  102.604 10.224 103.861 11.976 ;
     RECT  103.861 10.224 103.925 12.504 ;
     RECT  103.484 20.544 104.389 20.568 ;
     RECT  104.389 20.544 104.533 20.616 ;
     RECT  104.533 20.544 104.717 20.664 ;
     RECT  103.817 1.728 104.869 7.752 ;
     RECT  104.725 18.816 104.869 18.84 ;
     RECT  104.717 20.544 104.869 20.616 ;
     RECT  104.869 1.728 105.008 7.992 ;
     RECT  103.925 11.04 105.008 12.504 ;
     RECT  104.869 18.816 105.008 20.616 ;
     RECT  105.008 1.728 105.304 20.616 ;
     RECT  105.304 1.728 105.443 7.992 ;
     RECT  105.304 19.536 105.443 20.616 ;
     RECT  105.443 7.968 105.689 7.992 ;
     RECT  105.443 20.544 106.213 20.616 ;
     RECT  106.213 20.544 106.337 20.712 ;
     RECT  105.443 1.728 106.405 6.84 ;
     RECT  105.304 11.376 106.445 11.4 ;
     RECT  106.405 1.728 106.451 6.888 ;
     RECT  105.304 12.528 106.597 13.128 ;
     RECT  106.597 12.528 106.697 13.56 ;
     RECT  106.337 20.544 106.769 20.616 ;
     RECT  106.451 5.664 106.933 6.888 ;
     RECT  106.765 7.968 106.933 7.992 ;
     RECT  106.451 1.728 107.413 4.68 ;
     RECT  106.933 5.664 107.413 7.992 ;
     RECT  107.549 19.44 107.564 19.464 ;
     RECT  107.413 1.728 107.708 7.992 ;
     RECT  107.413 10.08 107.708 10.104 ;
     RECT  107.269 11.232 107.708 11.256 ;
     RECT  106.741 12.384 107.708 12.408 ;
     RECT  106.697 13.536 107.708 13.56 ;
     RECT  107.564 19.44 107.708 19.56 ;
     RECT  107.708 1.728 108.004 19.56 ;
     RECT  106.769 20.544 108.085 20.568 ;
     RECT  108.004 19.536 108.131 19.56 ;
     RECT  108.004 1.728 108.289 7.368 ;
     RECT  108.004 17.616 108.317 17.64 ;
     RECT  108.289 5.616 108.323 7.368 ;
     RECT  108.289 1.728 108.361 4.584 ;
     RECT  108.004 8.496 108.389 10.104 ;
     RECT  108.085 20.544 108.613 20.616 ;
     RECT  108.389 8.496 108.649 9.96 ;
     RECT  108.649 8.496 108.865 8.568 ;
     RECT  108.323 5.712 109.321 7.368 ;
     RECT  108.361 1.728 109.333 4.536 ;
     RECT  109.321 5.616 109.333 7.368 ;
     RECT  108.865 8.496 109.361 8.52 ;
     RECT  108.613 20.544 109.757 20.664 ;
     RECT  109.333 1.728 109.813 7.368 ;
     RECT  109.757 20.592 109.829 20.664 ;
     RECT  109.829 20.592 109.937 20.616 ;
     RECT  109.813 1.728 110.117 8.328 ;
     RECT  110.117 1.776 110.408 8.328 ;
     RECT  108.649 9.936 110.408 9.96 ;
     RECT  110.408 1.776 110.512 19.452 ;
     RECT  110.512 1.776 110.704 19.182 ;
     RECT  110.704 1.776 110.801 5.064 ;
     RECT  110.801 1.776 110.909 3.96 ;
     RECT  110.909 1.776 111.089 3.432 ;
     RECT  110.704 6.672 111.125 6.696 ;
     RECT  110.801 5.04 111.197 5.064 ;
     RECT  111.089 2.736 111.341 3.432 ;
     RECT  111.341 3.408 111.773 3.432 ;
    LAYER M5 ;
     RECT  4.32 0.144 110.184 1.763 ;
     RECT  4.32 1.763 32.808 1.811 ;
     RECT  33.84 1.763 46.728 1.811 ;
     RECT  47.712 1.763 76.584 1.811 ;
     RECT  77.76 1.763 110.184 1.811 ;
     RECT  26.352 1.811 32.808 1.859 ;
     RECT  34.512 1.811 38.088 1.859 ;
     RECT  39.6 1.811 40.776 1.859 ;
     RECT  42.144 1.811 43.212 1.859 ;
     RECT  44.352 1.811 46.728 1.859 ;
     RECT  47.712 1.811 51.312 1.859 ;
     RECT  53.52 1.811 60.648 1.859 ;
     RECT  63.168 1.811 63.336 1.859 ;
     RECT  64.368 1.811 65.544 1.859 ;
     RECT  66.576 1.811 70.632 1.859 ;
     RECT  71.664 1.811 72.912 1.859 ;
     RECT  74.016 1.811 76.248 1.859 ;
     RECT  77.904 1.811 110.184 1.859 ;
     RECT  4.32 1.811 25.08 1.907 ;
     RECT  26.352 1.859 28.344 1.907 ;
     RECT  31.296 1.859 32.412 1.907 ;
     RECT  77.904 1.859 78.312 1.907 ;
     RECT  79.632 1.859 81.288 1.907 ;
     RECT  82.512 1.859 110.184 2.137 ;
     RECT  2.4 2.137 2.52 2.151 ;
     RECT  82.512 2.137 110.52 2.151 ;
     RECT  64.5 1.859 65.544 2.243 ;
     RECT  72.336 1.859 72.912 2.243 ;
     RECT  31.632 1.907 32.412 2.291 ;
     RECT  36.72 1.859 37.812 2.291 ;
     RECT  40.2 1.859 40.776 2.291 ;
     RECT  48.3 1.859 51.312 2.291 ;
     RECT  58.896 1.859 59.976 2.291 ;
     RECT  61.632 1.811 62.112 2.291 ;
     RECT  4.32 1.907 20.088 2.339 ;
     RECT  48.3 2.291 49.608 2.339 ;
     RECT  63.312 1.859 63.336 2.339 ;
     RECT  82.512 2.151 110.712 2.339 ;
     RECT  4.32 2.339 14.184 2.773 ;
     RECT  67.2 1.859 70.632 2.821 ;
     RECT  79.776 1.907 81.288 2.821 ;
     RECT  34.8 1.859 35.208 2.869 ;
     RECT  42.9 1.859 43.212 2.869 ;
     RECT  99.024 2.339 108.456 2.915 ;
     RECT  64.5 2.243 64.968 3.061 ;
     RECT  21.3 1.907 25.08 3.109 ;
     RECT  78 1.907 78.312 3.109 ;
     RECT  79.776 2.821 81.384 3.109 ;
     RECT  21.168 3.109 25.08 3.205 ;
     RECT  67.2 2.821 71.256 3.301 ;
     RECT  2.4 2.151 2.712 3.349 ;
     RECT  3.936 2.773 14.184 3.349 ;
     RECT  78 3.109 81.384 3.349 ;
     RECT  15.9 2.339 19.032 3.397 ;
     RECT  20.208 3.205 25.08 3.397 ;
     RECT  26.7 1.907 28.344 3.397 ;
     RECT  32.1 2.291 32.412 3.397 ;
     RECT  42.9 2.869 43.944 3.397 ;
     RECT  45.6 1.859 45.912 3.397 ;
     RECT  48.3 2.339 49.56 3.397 ;
     RECT  51 2.291 51.312 3.397 ;
     RECT  53.568 1.859 55.128 3.397 ;
     RECT  109.536 2.339 110.712 3.397 ;
     RECT  53.568 3.397 55.224 3.491 ;
     RECT  55.104 3.491 55.224 3.539 ;
     RECT  20.208 3.397 28.344 3.589 ;
     RECT  32.1 3.397 33.048 3.589 ;
     RECT  40.2 2.291 40.632 3.589 ;
     RECT  29.4 1.859 29.712 3.637 ;
     RECT  75.3 1.859 75.612 3.637 ;
     RECT  42.72 3.397 43.944 3.685 ;
     RECT  109.488 3.397 110.712 3.685 ;
     RECT  2.4 3.349 14.184 3.733 ;
     RECT  15.264 3.397 19.032 3.733 ;
     RECT  52.464 3.013 52.488 3.733 ;
     RECT  53.568 3.491 54.12 3.733 ;
     RECT  78 3.349 81.48 3.733 ;
     RECT  82.512 2.339 87.624 3.733 ;
     RECT  40.2 3.589 40.68 3.877 ;
     RECT  37.5 2.291 37.812 3.925 ;
     RECT  48.3 3.397 49.608 3.925 ;
     RECT  50.688 3.397 51.312 3.925 ;
     RECT  55.2 3.539 55.224 3.925 ;
     RECT  56.208 1.859 57.24 3.925 ;
     RECT  75.3 3.637 75.768 3.925 ;
     RECT  66.336 3.301 71.256 4.019 ;
     RECT  78 3.733 87.624 4.019 ;
     RECT  99.024 2.915 108.312 4.019 ;
     RECT  2.4 3.733 19.032 4.067 ;
     RECT  79.776 4.019 87.192 4.067 ;
     RECT  20.208 3.589 28.392 4.115 ;
     RECT  66.336 4.019 67.512 4.115 ;
     RECT  88.8 2.339 98.04 4.115 ;
     RECT  99.024 4.019 105.432 4.115 ;
     RECT  22.656 4.115 28.392 4.117 ;
     RECT  29.4 3.637 30.312 4.117 ;
     RECT  69.216 4.019 71.256 4.117 ;
     RECT  72.6 2.243 72.912 4.117 ;
     RECT  106.512 4.019 108.312 4.117 ;
     RECT  109.44 3.685 110.712 4.117 ;
     RECT  22.656 4.117 30.312 4.163 ;
     RECT  55.2 3.925 57.24 4.213 ;
     RECT  58.896 2.291 59.412 4.213 ;
     RECT  61.68 2.291 62.112 4.213 ;
     RECT  45.024 3.397 45.912 4.259 ;
     RECT  46.944 3.397 46.968 4.259 ;
     RECT  75.024 3.925 75.768 4.259 ;
     RECT  63.552 3.061 64.968 4.451 ;
     RECT  61.056 4.213 62.112 4.453 ;
     RECT  45.504 4.259 45.912 4.501 ;
     RECT  63.84 4.451 64.968 4.501 ;
     RECT  96.096 4.115 98.04 4.501 ;
     RECT  99.024 4.115 103.704 4.501 ;
     RECT  2.4 4.067 18.912 4.595 ;
     RECT  55.2 4.213 59.412 4.595 ;
     RECT  79.824 4.067 87.192 4.595 ;
     RECT  88.8 4.115 95.016 4.595 ;
     RECT  76.944 3.397 76.968 4.691 ;
     RECT  88.8 4.595 94.968 4.691 ;
     RECT  31.344 3.589 33.048 4.693 ;
     RECT  88.8 4.691 89.112 4.693 ;
     RECT  22.656 4.163 25.128 4.739 ;
     RECT  20.208 4.115 21.612 4.741 ;
     RECT  79.824 4.595 87.144 4.883 ;
     RECT  37.104 3.925 37.812 4.885 ;
     RECT  2.4 4.595 17.112 4.979 ;
     RECT  56.4 4.595 59.412 4.979 ;
     RECT  52.464 3.733 54.12 4.981 ;
     RECT  55.2 4.595 55.416 4.981 ;
     RECT  67.2 4.115 67.512 4.981 ;
     RECT  26.7 4.163 30.312 5.027 ;
     RECT  37.104 4.885 38.088 5.027 ;
     RECT  42.48 3.685 43.944 5.027 ;
     RECT  79.824 4.883 86.412 5.027 ;
     RECT  34.8 2.869 35.352 5.029 ;
     RECT  48.3 3.925 51.312 5.077 ;
     RECT  67.2 4.981 67.656 5.077 ;
     RECT  69.216 4.117 72.912 5.077 ;
     RECT  106.512 4.117 110.712 5.077 ;
     RECT  58.896 4.979 59.412 5.125 ;
     RECT  26.7 5.027 29.976 5.171 ;
     RECT  31.344 4.693 33.144 5.171 ;
     RECT  56.4 4.979 57.864 5.171 ;
     RECT  96.096 4.501 103.704 5.171 ;
     RECT  104.832 4.115 105.432 5.171 ;
     RECT  61.056 4.453 62.616 5.173 ;
     RECT  2.4 4.979 3.432 5.219 ;
     RECT  20.112 4.741 21.612 5.219 ;
     RECT  22.656 4.739 24.744 5.219 ;
     RECT  31.536 5.171 33.144 5.219 ;
     RECT  63.84 4.501 65.496 5.221 ;
     RECT  60.864 5.173 62.616 5.411 ;
     RECT  61.056 5.411 62.616 5.459 ;
     RECT  75.3 4.259 75.768 5.459 ;
     RECT  45.504 4.501 46.776 5.507 ;
     RECT  45.504 5.507 45.912 5.555 ;
     RECT  79.824 5.027 83.928 5.555 ;
     RECT  42.768 5.027 43.32 5.603 ;
     RECT  52.464 4.981 55.416 5.603 ;
     RECT  22.656 5.219 24.312 5.605 ;
     RECT  39.696 3.877 40.68 5.605 ;
     RECT  88.512 4.693 89.112 5.605 ;
     RECT  104.88 5.171 105.432 5.605 ;
     RECT  106.416 5.077 110.712 5.605 ;
     RECT  5.1 4.979 17.112 5.747 ;
     RECT  31.536 5.219 32.412 5.747 ;
     RECT  48.3 5.077 51.432 5.747 ;
     RECT  52.464 5.603 54.696 5.747 ;
     RECT  58.896 5.125 59.592 5.747 ;
     RECT  67.2 5.077 72.912 5.747 ;
     RECT  75.3 5.459 75.72 5.747 ;
     RECT  78 4.019 78.6 5.747 ;
     RECT  96.096 5.171 97.212 5.747 ;
     RECT  50.112 5.747 51.432 5.749 ;
     RECT  52.464 5.747 52.488 5.749 ;
     RECT  10.224 5.747 17.112 5.795 ;
     RECT  21.12 5.219 21.612 5.795 ;
     RECT  42.9 5.603 43.32 5.795 ;
     RECT  78 5.747 78.504 5.843 ;
     RECT  18.192 4.595 18.912 5.845 ;
     RECT  19.968 5.509 19.992 5.845 ;
     RECT  72.48 5.747 72.912 5.845 ;
     RECT  74.064 4.645 74.088 5.845 ;
     RECT  12.288 5.795 17.112 5.891 ;
     RECT  67.2 5.747 71.016 5.989 ;
     RECT  50.112 5.749 52.488 6.035 ;
     RECT  66.672 5.989 71.016 6.035 ;
     RECT  63.84 5.221 65.64 6.085 ;
     RECT  66.672 6.035 67.608 6.085 ;
     RECT  31.68 5.747 32.412 6.131 ;
     RECT  63.84 6.085 67.608 6.131 ;
     RECT  5.1 5.747 9.096 6.229 ;
     RECT  69.504 6.035 71.016 6.275 ;
     RECT  79.824 5.555 83.88 6.275 ;
     RECT  4.464 6.229 9.096 6.323 ;
     RECT  18.192 5.845 19.992 6.323 ;
     RECT  21.168 5.795 21.612 6.323 ;
     RECT  39.312 5.605 40.68 6.323 ;
     RECT  50.112 6.035 51.768 6.323 ;
     RECT  53.472 5.747 54.696 6.323 ;
     RECT  61.056 5.459 62.112 6.323 ;
     RECT  63.84 6.131 66.168 6.323 ;
     RECT  67.2 6.131 67.608 6.323 ;
     RECT  98.448 5.171 103.704 6.323 ;
     RECT  6.816 6.323 9.096 6.371 ;
     RECT  104.88 5.605 110.712 6.419 ;
     RECT  85.296 5.027 86.412 6.613 ;
     RECT  18.6 6.323 19.992 6.659 ;
     RECT  50.784 6.323 51.768 6.659 ;
     RECT  53.7 6.323 54.696 6.659 ;
     RECT  56.4 5.171 57.432 6.659 ;
     RECT  10.224 5.795 10.812 6.805 ;
     RECT  42.9 5.795 43.212 6.805 ;
     RECT  75.3 5.747 75.612 6.805 ;
     RECT  96.288 5.747 97.212 6.805 ;
     RECT  19.968 6.659 19.992 6.899 ;
     RECT  22.608 5.605 24.312 6.899 ;
     RECT  28.416 5.171 29.976 6.899 ;
     RECT  63.84 6.323 64.812 6.899 ;
     RECT  69.504 6.275 70.584 6.899 ;
     RECT  80.7 6.275 83.88 6.899 ;
     RECT  101.376 6.323 103.704 6.899 ;
     RECT  102.096 6.899 103.608 6.947 ;
     RECT  22.8 6.899 24.312 7.187 ;
     RECT  72.48 5.845 74.088 7.187 ;
     RECT  9.648 6.805 10.812 7.237 ;
     RECT  12.288 5.891 16.488 7.237 ;
     RECT  48.3 5.747 48.612 7.237 ;
     RECT  96.288 6.805 97.32 7.285 ;
     RECT  23.904 7.187 24.312 7.333 ;
     RECT  37.104 5.027 37.812 7.333 ;
     RECT  48.3 7.237 49.272 7.333 ;
     RECT  67.2 6.323 67.512 7.333 ;
     RECT  80.7 6.899 83.712 7.333 ;
     RECT  96.048 7.285 97.32 7.333 ;
     RECT  6.816 6.371 8.52 7.381 ;
     RECT  9.648 7.237 17.4 7.381 ;
     RECT  23.904 7.333 24.696 7.381 ;
     RECT  26.7 5.171 27.012 7.381 ;
     RECT  32.1 6.131 32.412 7.381 ;
     RECT  34.8 5.029 35.736 7.381 ;
     RECT  48.192 7.333 49.272 7.381 ;
     RECT  58.896 5.747 59.412 7.381 ;
     RECT  61.8 6.323 62.112 7.381 ;
     RECT  78 5.843 78.312 7.381 ;
     RECT  96.048 7.333 97.464 7.381 ;
     RECT  98.448 6.323 100.344 7.381 ;
     RECT  102.096 6.947 103.176 7.427 ;
     RECT  6.528 7.381 17.4 7.475 ;
     RECT  23.904 7.381 25.368 7.475 ;
     RECT  34.32 7.381 35.736 7.475 ;
     RECT  66.144 6.323 66.168 7.475 ;
     RECT  88.224 5.605 89.112 7.571 ;
     RECT  90.288 4.691 94.968 7.571 ;
     RECT  51 6.659 51.768 7.717 ;
     RECT  96.048 7.381 100.344 7.763 ;
     RECT  39.744 6.323 40.512 7.765 ;
     RECT  45.6 5.555 45.912 7.765 ;
     RECT  42.768 6.805 43.212 7.861 ;
     RECT  50.592 7.717 51.768 7.861 ;
     RECT  56.4 6.659 57.24 7.861 ;
     RECT  21.3 6.323 21.612 7.909 ;
     RECT  47.904 7.381 49.272 7.909 ;
     RECT  50.592 7.861 52.008 7.909 ;
     RECT  58.896 7.381 60.12 7.909 ;
     RECT  61.8 7.381 62.856 7.909 ;
     RECT  67.2 7.333 68.28 7.909 ;
     RECT  91.344 7.571 94.968 7.909 ;
     RECT  96.048 7.763 99.912 7.909 ;
     RECT  18.6 6.659 18.912 7.957 ;
     RECT  26.7 7.381 27.144 7.957 ;
     RECT  58.752 7.909 60.12 7.957 ;
     RECT  61.488 7.909 62.856 7.957 ;
     RECT  74.064 7.187 74.088 7.957 ;
     RECT  75.3 6.805 75.912 7.957 ;
     RECT  78 7.381 78.456 7.957 ;
     RECT  79.776 7.333 83.712 7.957 ;
     RECT  85.296 6.613 86.568 7.957 ;
     RECT  105 6.419 110.712 7.957 ;
     RECT  6.528 7.475 11.784 8.003 ;
     RECT  13.104 7.475 17.4 8.003 ;
     RECT  72.48 7.187 73.032 8.003 ;
     RECT  79.776 7.957 86.568 8.003 ;
     RECT  91.344 7.909 99.912 8.003 ;
     RECT  91.344 8.003 98.28 8.051 ;
     RECT  93.456 8.051 98.28 8.099 ;
     RECT  74.064 7.957 75.912 8.243 ;
     RECT  90.288 7.571 90.312 8.243 ;
     RECT  69.504 6.899 70.488 8.293 ;
     RECT  42.48 7.861 43.212 8.341 ;
     RECT  26.7 7.957 27.384 8.437 ;
     RECT  28.752 6.899 29.976 8.437 ;
     RECT  53.7 6.659 54.12 8.437 ;
     RECT  102.192 7.427 103.176 8.437 ;
     RECT  21.168 7.909 21.612 8.485 ;
     RECT  42.288 8.341 43.212 8.485 ;
     RECT  47.904 7.909 52.008 8.485 ;
     RECT  53.136 8.437 54.12 8.485 ;
     RECT  55.344 7.381 55.368 8.485 ;
     RECT  56.4 7.861 57.432 8.485 ;
     RECT  58.752 7.957 62.856 8.485 ;
     RECT  64.5 6.899 64.812 8.485 ;
     RECT  66.912 7.909 68.28 8.485 ;
     RECT  69.504 8.293 70.968 8.485 ;
     RECT  72.6 8.003 73.032 8.485 ;
     RECT  74.352 8.243 75.912 8.485 ;
     RECT  77.088 7.957 78.456 8.485 ;
     RECT  102.096 8.437 103.176 8.485 ;
     RECT  7.8 8.003 11.784 8.579 ;
     RECT  79.776 8.003 84.552 8.579 ;
     RECT  82.704 8.579 84.552 8.771 ;
     RECT  4.464 6.323 5.544 8.869 ;
     RECT  6.528 8.003 6.552 8.869 ;
     RECT  20.592 8.485 21.612 8.869 ;
     RECT  22.8 7.187 22.824 8.869 ;
     RECT  45.6 7.765 46.008 8.869 ;
     RECT  45.6 8.869 46.392 8.965 ;
     RECT  47.712 8.485 55.368 8.965 ;
     RECT  72.6 8.485 73.176 9.013 ;
     RECT  93.504 8.099 98.28 9.013 ;
     RECT  99.6 8.003 99.912 9.013 ;
     RECT  18.48 7.957 18.912 9.061 ;
     RECT  34.32 7.475 35.688 9.061 ;
     RECT  37.056 7.333 37.812 9.061 ;
     RECT  39.744 7.765 41.16 9.061 ;
     RECT  42.288 8.485 43.704 9.061 ;
     RECT  45.024 8.965 55.368 9.061 ;
     RECT  66.912 8.485 70.968 9.061 ;
     RECT  72.336 9.013 73.176 9.061 ;
     RECT  91.344 8.051 92.232 9.061 ;
     RECT  90.624 9.061 92.232 9.155 ;
     RECT  101.664 8.485 103.176 9.155 ;
     RECT  26.592 8.437 29.976 9.299 ;
     RECT  24 7.475 25.368 9.397 ;
     RECT  26.592 9.299 29.712 9.397 ;
     RECT  66.912 9.061 73.176 9.397 ;
     RECT  74.352 8.485 78.456 9.397 ;
     RECT  79.776 8.579 81.144 9.397 ;
     RECT  4.32 8.869 6.552 9.637 ;
     RECT  7.8 8.579 9.096 9.637 ;
     RECT  31.44 7.381 32.412 9.637 ;
     RECT  83.184 8.771 84.552 9.637 ;
     RECT  88.704 7.571 89.112 9.637 ;
     RECT  101.664 9.155 102.888 9.637 ;
     RECT  31.44 9.637 32.808 9.925 ;
     RECT  34.32 9.061 37.812 9.925 ;
     RECT  39.6 9.061 41.16 9.925 ;
     RECT  56.4 8.485 62.856 9.925 ;
     RECT  39.072 9.925 41.16 10.165 ;
     RECT  42.288 9.061 55.368 10.165 ;
     RECT  66.384 9.397 73.176 10.165 ;
     RECT  18.48 9.061 19.416 10.213 ;
     RECT  86.1 8.003 86.52 10.213 ;
     RECT  100.992 9.637 102.888 10.213 ;
     RECT  20.592 8.869 22.824 10.645 ;
     RECT  24 9.397 29.712 10.645 ;
     RECT  10.272 8.579 11.784 10.693 ;
     RECT  13.2 8.003 17.4 10.693 ;
     RECT  18.48 10.213 19.608 10.693 ;
     RECT  13.2 10.693 19.608 10.741 ;
     RECT  30.96 9.925 37.812 10.741 ;
     RECT  64.176 8.485 64.812 10.741 ;
     RECT  83.184 9.637 84.744 10.741 ;
     RECT  82.848 10.741 84.744 10.789 ;
     RECT  100.992 10.213 103.032 11.029 ;
     RECT  20.592 10.645 29.712 11.125 ;
     RECT  30.96 10.741 37.944 11.125 ;
     RECT  39.072 10.165 55.368 11.221 ;
     RECT  56.4 9.925 63 11.221 ;
     RECT  82.176 10.789 84.744 11.221 ;
     RECT  86.1 10.213 86.568 11.221 ;
     RECT  64.176 10.741 64.92 11.269 ;
     RECT  74.352 9.397 81.144 11.365 ;
     RECT  82.176 11.221 86.568 11.365 ;
     RECT  88.704 9.637 89.304 11.365 ;
     RECT  100.992 11.029 103.224 11.365 ;
     RECT  104.88 7.957 110.712 11.365 ;
     RECT  12.768 10.741 19.608 11.941 ;
     RECT  20.592 11.125 37.944 11.941 ;
     RECT  64.176 11.269 65.4 11.941 ;
     RECT  88.704 11.365 89.64 11.941 ;
     RECT  10.08 10.693 11.784 12.517 ;
     RECT  12.768 11.941 37.944 12.517 ;
     RECT  66.384 10.165 73.368 12.517 ;
     RECT  74.352 11.365 86.568 12.517 ;
     RECT  4.32 9.637 9.096 12.901 ;
     RECT  10.08 12.517 37.944 12.901 ;
     RECT  39.072 11.221 63 13.045 ;
     RECT  64.032 11.941 65.4 13.045 ;
     RECT  66.384 12.517 86.568 13.045 ;
     RECT  93.504 9.013 99.912 13.045 ;
     RECT  66.384 13.045 87.096 13.621 ;
     RECT  88.272 11.941 89.64 13.621 ;
     RECT  90.624 9.155 92.184 13.621 ;
     RECT  93.168 13.045 99.912 15.349 ;
     RECT  100.992 11.365 110.712 15.349 ;
     RECT  2.4 5.219 2.712 19.449 ;
     RECT  93.168 15.349 110.712 19.449 ;
     RECT  2.4 19.449 2.52 19.463 ;
     RECT  66.384 13.621 92.184 19.463 ;
     RECT  93.168 19.449 110.52 19.463 ;
     RECT  4.32 12.901 37.944 19.571 ;
     RECT  4.32 19.571 37.752 20.533 ;
     RECT  39.072 13.045 65.4 20.533 ;
     RECT  66.384 19.463 83.352 20.533 ;
     RECT  84.384 19.463 92.184 20.533 ;
     RECT  93.168 19.463 99.672 20.533 ;
     RECT  100.656 19.463 110.184 20.533 ;
     RECT  4.32 20.533 110.184 21.456 ;
     RECT  93.984 21.456 94.008 21.491 ;
     RECT  102.144 21.456 102.168 21.491 ;
  END
END hbfd_rly_624_SN_fc
END LIBRARY
